VERSION 5.8 ;
BUSBITCHARS "[]" ;
DIVIDERCHAR "/" ;
UNITS
    DATABASE MICRONS 1000 ;
END UNITS

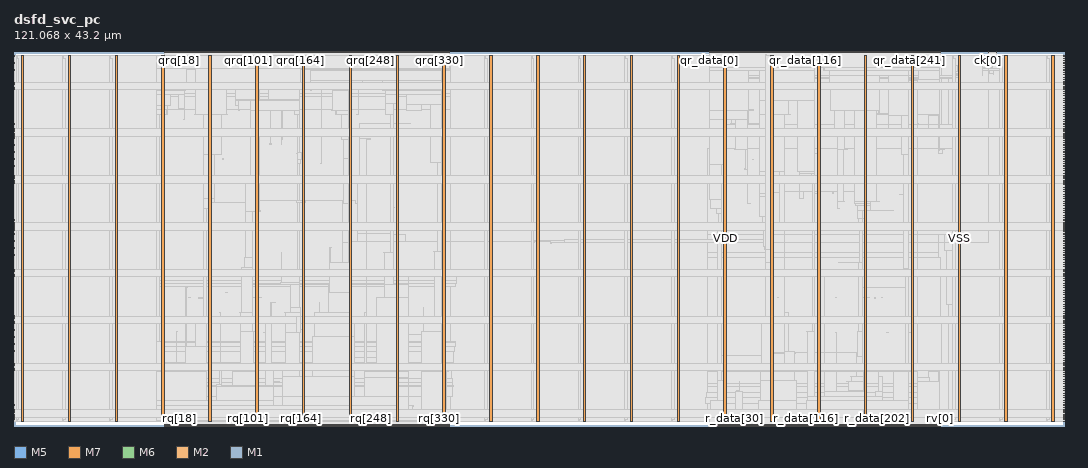
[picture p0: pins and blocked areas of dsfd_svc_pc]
MACRO dsfd_svc_pc
  FOREIGN dsfd_svc_pc 0 0 ;
  CLASS BLOCK ;
  SIZE 121.068 BY 43.2 ;
  PIN ck[0]
    DIRECTION INPUT ;
    USE SIGNAL ;
    PORT
      LAYER M5 ;
        RECT  112.32 43.008 112.344 43.2 ;
    END
  END ck[0]
  PIN qr_beat[0]
    DIRECTION OUTPUT ;
    USE SIGNAL ;
    PORT
      LAYER M5 ;
        RECT  106.368 43.008 106.392 43.2 ;
    END
  END qr_beat[0]
  PIN qr_beat[1]
    DIRECTION OUTPUT ;
    USE SIGNAL ;
    PORT
      LAYER M5 ;
        RECT  106.464 43.008 106.488 43.2 ;
    END
  END qr_beat[1]
  PIN qr_beat[2]
    DIRECTION OUTPUT ;
    USE SIGNAL ;
    PORT
      LAYER M5 ;
        RECT  106.56 43.008 106.584 43.2 ;
    END
  END qr_beat[2]
  PIN qr_beat[3]
    DIRECTION OUTPUT ;
    USE SIGNAL ;
    PORT
      LAYER M5 ;
        RECT  106.656 43.008 106.68 43.2 ;
    END
  END qr_beat[3]
  PIN qr_data[0]
    DIRECTION OUTPUT ;
    USE SIGNAL ;
    PORT
      LAYER M5 ;
        RECT  80.16 43.008 80.184 43.2 ;
    END
  END qr_data[0]
  PIN qr_data[100]
    DIRECTION OUTPUT ;
    USE SIGNAL ;
    PORT
      LAYER M5 ;
        RECT  89.76 43.008 89.784 43.2 ;
    END
  END qr_data[100]
  PIN qr_data[101]
    DIRECTION OUTPUT ;
    USE SIGNAL ;
    PORT
      LAYER M5 ;
        RECT  89.856 43.008 89.88 43.2 ;
    END
  END qr_data[101]
  PIN qr_data[102]
    DIRECTION OUTPUT ;
    USE SIGNAL ;
    PORT
      LAYER M5 ;
        RECT  89.952 43.008 89.976 43.2 ;
    END
  END qr_data[102]
  PIN qr_data[103]
    DIRECTION OUTPUT ;
    USE SIGNAL ;
    PORT
      LAYER M5 ;
        RECT  90.048 43.008 90.072 43.2 ;
    END
  END qr_data[103]
  PIN qr_data[104]
    DIRECTION OUTPUT ;
    USE SIGNAL ;
    PORT
      LAYER M5 ;
        RECT  90.144 43.008 90.168 43.2 ;
    END
  END qr_data[104]
  PIN qr_data[105]
    DIRECTION OUTPUT ;
    USE SIGNAL ;
    PORT
      LAYER M5 ;
        RECT  90.24 43.008 90.264 43.2 ;
    END
  END qr_data[105]
  PIN qr_data[106]
    DIRECTION OUTPUT ;
    USE SIGNAL ;
    PORT
      LAYER M5 ;
        RECT  90.336 43.008 90.36 43.2 ;
    END
  END qr_data[106]
  PIN qr_data[107]
    DIRECTION OUTPUT ;
    USE SIGNAL ;
    PORT
      LAYER M5 ;
        RECT  90.432 43.008 90.456 43.2 ;
    END
  END qr_data[107]
  PIN qr_data[108]
    DIRECTION OUTPUT ;
    USE SIGNAL ;
    PORT
      LAYER M5 ;
        RECT  90.528 43.008 90.552 43.2 ;
    END
  END qr_data[108]
  PIN qr_data[109]
    DIRECTION OUTPUT ;
    USE SIGNAL ;
    PORT
      LAYER M5 ;
        RECT  90.624 43.008 90.648 43.2 ;
    END
  END qr_data[109]
  PIN qr_data[10]
    DIRECTION OUTPUT ;
    USE SIGNAL ;
    PORT
      LAYER M5 ;
        RECT  81.12 43.008 81.144 43.2 ;
    END
  END qr_data[10]
  PIN qr_data[110]
    DIRECTION OUTPUT ;
    USE SIGNAL ;
    PORT
      LAYER M5 ;
        RECT  90.72 43.008 90.744 43.2 ;
    END
  END qr_data[110]
  PIN qr_data[111]
    DIRECTION OUTPUT ;
    USE SIGNAL ;
    PORT
      LAYER M5 ;
        RECT  90.816 43.008 90.84 43.2 ;
    END
  END qr_data[111]
  PIN qr_data[112]
    DIRECTION OUTPUT ;
    USE SIGNAL ;
    PORT
      LAYER M5 ;
        RECT  90.912 43.008 90.936 43.2 ;
    END
  END qr_data[112]
  PIN qr_data[113]
    DIRECTION OUTPUT ;
    USE SIGNAL ;
    PORT
      LAYER M5 ;
        RECT  91.008 43.008 91.032 43.2 ;
    END
  END qr_data[113]
  PIN qr_data[114]
    DIRECTION OUTPUT ;
    USE SIGNAL ;
    PORT
      LAYER M5 ;
        RECT  91.104 43.008 91.128 43.2 ;
    END
  END qr_data[114]
  PIN qr_data[115]
    DIRECTION OUTPUT ;
    USE SIGNAL ;
    PORT
      LAYER M5 ;
        RECT  91.2 43.008 91.224 43.2 ;
    END
  END qr_data[115]
  PIN qr_data[116]
    DIRECTION OUTPUT ;
    USE SIGNAL ;
    PORT
      LAYER M5 ;
        RECT  91.296 43.008 91.32 43.2 ;
    END
  END qr_data[116]
  PIN qr_data[117]
    DIRECTION OUTPUT ;
    USE SIGNAL ;
    PORT
      LAYER M5 ;
        RECT  91.392 43.008 91.416 43.2 ;
    END
  END qr_data[117]
  PIN qr_data[118]
    DIRECTION OUTPUT ;
    USE SIGNAL ;
    PORT
      LAYER M5 ;
        RECT  91.488 43.008 91.512 43.2 ;
    END
  END qr_data[118]
  PIN qr_data[119]
    DIRECTION OUTPUT ;
    USE SIGNAL ;
    PORT
      LAYER M5 ;
        RECT  91.584 43.008 91.608 43.2 ;
    END
  END qr_data[119]
  PIN qr_data[11]
    DIRECTION OUTPUT ;
    USE SIGNAL ;
    PORT
      LAYER M5 ;
        RECT  81.216 43.008 81.24 43.2 ;
    END
  END qr_data[11]
  PIN qr_data[120]
    DIRECTION OUTPUT ;
    USE SIGNAL ;
    PORT
      LAYER M5 ;
        RECT  91.68 43.008 91.704 43.2 ;
    END
  END qr_data[120]
  PIN qr_data[121]
    DIRECTION OUTPUT ;
    USE SIGNAL ;
    PORT
      LAYER M5 ;
        RECT  91.776 43.008 91.8 43.2 ;
    END
  END qr_data[121]
  PIN qr_data[122]
    DIRECTION OUTPUT ;
    USE SIGNAL ;
    PORT
      LAYER M5 ;
        RECT  91.872 43.008 91.896 43.2 ;
    END
  END qr_data[122]
  PIN qr_data[123]
    DIRECTION OUTPUT ;
    USE SIGNAL ;
    PORT
      LAYER M5 ;
        RECT  91.968 43.008 91.992 43.2 ;
    END
  END qr_data[123]
  PIN qr_data[124]
    DIRECTION OUTPUT ;
    USE SIGNAL ;
    PORT
      LAYER M5 ;
        RECT  92.064 43.008 92.088 43.2 ;
    END
  END qr_data[124]
  PIN qr_data[125]
    DIRECTION OUTPUT ;
    USE SIGNAL ;
    PORT
      LAYER M5 ;
        RECT  92.16 43.008 92.184 43.2 ;
    END
  END qr_data[125]
  PIN qr_data[126]
    DIRECTION OUTPUT ;
    USE SIGNAL ;
    PORT
      LAYER M5 ;
        RECT  92.256 43.008 92.28 43.2 ;
    END
  END qr_data[126]
  PIN qr_data[127]
    DIRECTION OUTPUT ;
    USE SIGNAL ;
    PORT
      LAYER M5 ;
        RECT  92.352 43.008 92.376 43.2 ;
    END
  END qr_data[127]
  PIN qr_data[128]
    DIRECTION OUTPUT ;
    USE SIGNAL ;
    PORT
      LAYER M5 ;
        RECT  92.448 43.008 92.472 43.2 ;
    END
  END qr_data[128]
  PIN qr_data[129]
    DIRECTION OUTPUT ;
    USE SIGNAL ;
    PORT
      LAYER M5 ;
        RECT  92.544 43.008 92.568 43.2 ;
    END
  END qr_data[129]
  PIN qr_data[12]
    DIRECTION OUTPUT ;
    USE SIGNAL ;
    PORT
      LAYER M5 ;
        RECT  81.312 43.008 81.336 43.2 ;
    END
  END qr_data[12]
  PIN qr_data[130]
    DIRECTION OUTPUT ;
    USE SIGNAL ;
    PORT
      LAYER M5 ;
        RECT  92.64 43.008 92.664 43.2 ;
    END
  END qr_data[130]
  PIN qr_data[131]
    DIRECTION OUTPUT ;
    USE SIGNAL ;
    PORT
      LAYER M5 ;
        RECT  92.736 43.008 92.76 43.2 ;
    END
  END qr_data[131]
  PIN qr_data[132]
    DIRECTION OUTPUT ;
    USE SIGNAL ;
    PORT
      LAYER M5 ;
        RECT  92.832 43.008 92.856 43.2 ;
    END
  END qr_data[132]
  PIN qr_data[133]
    DIRECTION OUTPUT ;
    USE SIGNAL ;
    PORT
      LAYER M5 ;
        RECT  92.928 43.008 92.952 43.2 ;
    END
  END qr_data[133]
  PIN qr_data[134]
    DIRECTION OUTPUT ;
    USE SIGNAL ;
    PORT
      LAYER M5 ;
        RECT  93.024 43.008 93.048 43.2 ;
    END
  END qr_data[134]
  PIN qr_data[135]
    DIRECTION OUTPUT ;
    USE SIGNAL ;
    PORT
      LAYER M5 ;
        RECT  93.12 43.008 93.144 43.2 ;
    END
  END qr_data[135]
  PIN qr_data[136]
    DIRECTION OUTPUT ;
    USE SIGNAL ;
    PORT
      LAYER M5 ;
        RECT  93.216 43.008 93.24 43.2 ;
    END
  END qr_data[136]
  PIN qr_data[137]
    DIRECTION OUTPUT ;
    USE SIGNAL ;
    PORT
      LAYER M5 ;
        RECT  93.312 43.008 93.336 43.2 ;
    END
  END qr_data[137]
  PIN qr_data[138]
    DIRECTION OUTPUT ;
    USE SIGNAL ;
    PORT
      LAYER M5 ;
        RECT  93.408 43.008 93.432 43.2 ;
    END
  END qr_data[138]
  PIN qr_data[139]
    DIRECTION OUTPUT ;
    USE SIGNAL ;
    PORT
      LAYER M5 ;
        RECT  93.504 43.008 93.528 43.2 ;
    END
  END qr_data[139]
  PIN qr_data[13]
    DIRECTION OUTPUT ;
    USE SIGNAL ;
    PORT
      LAYER M5 ;
        RECT  81.408 43.008 81.432 43.2 ;
    END
  END qr_data[13]
  PIN qr_data[140]
    DIRECTION OUTPUT ;
    USE SIGNAL ;
    PORT
      LAYER M5 ;
        RECT  93.6 43.008 93.624 43.2 ;
    END
  END qr_data[140]
  PIN qr_data[141]
    DIRECTION OUTPUT ;
    USE SIGNAL ;
    PORT
      LAYER M5 ;
        RECT  93.696 43.008 93.72 43.2 ;
    END
  END qr_data[141]
  PIN qr_data[142]
    DIRECTION OUTPUT ;
    USE SIGNAL ;
    PORT
      LAYER M5 ;
        RECT  93.792 43.008 93.816 43.2 ;
    END
  END qr_data[142]
  PIN qr_data[143]
    DIRECTION OUTPUT ;
    USE SIGNAL ;
    PORT
      LAYER M5 ;
        RECT  93.888 43.008 93.912 43.2 ;
    END
  END qr_data[143]
  PIN qr_data[144]
    DIRECTION OUTPUT ;
    USE SIGNAL ;
    PORT
      LAYER M5 ;
        RECT  93.984 43.008 94.008 43.2 ;
    END
  END qr_data[144]
  PIN qr_data[145]
    DIRECTION OUTPUT ;
    USE SIGNAL ;
    PORT
      LAYER M5 ;
        RECT  94.08 43.008 94.104 43.2 ;
    END
  END qr_data[145]
  PIN qr_data[146]
    DIRECTION OUTPUT ;
    USE SIGNAL ;
    PORT
      LAYER M5 ;
        RECT  94.176 43.008 94.2 43.2 ;
    END
  END qr_data[146]
  PIN qr_data[147]
    DIRECTION OUTPUT ;
    USE SIGNAL ;
    PORT
      LAYER M5 ;
        RECT  94.272 43.008 94.296 43.2 ;
    END
  END qr_data[147]
  PIN qr_data[148]
    DIRECTION OUTPUT ;
    USE SIGNAL ;
    PORT
      LAYER M5 ;
        RECT  94.368 43.008 94.392 43.2 ;
    END
  END qr_data[148]
  PIN qr_data[149]
    DIRECTION OUTPUT ;
    USE SIGNAL ;
    PORT
      LAYER M5 ;
        RECT  94.464 43.008 94.488 43.2 ;
    END
  END qr_data[149]
  PIN qr_data[14]
    DIRECTION OUTPUT ;
    USE SIGNAL ;
    PORT
      LAYER M5 ;
        RECT  81.504 43.008 81.528 43.2 ;
    END
  END qr_data[14]
  PIN qr_data[150]
    DIRECTION OUTPUT ;
    USE SIGNAL ;
    PORT
      LAYER M5 ;
        RECT  94.56 43.008 94.584 43.2 ;
    END
  END qr_data[150]
  PIN qr_data[151]
    DIRECTION OUTPUT ;
    USE SIGNAL ;
    PORT
      LAYER M5 ;
        RECT  94.656 43.008 94.68 43.2 ;
    END
  END qr_data[151]
  PIN qr_data[152]
    DIRECTION OUTPUT ;
    USE SIGNAL ;
    PORT
      LAYER M5 ;
        RECT  94.752 43.008 94.776 43.2 ;
    END
  END qr_data[152]
  PIN qr_data[153]
    DIRECTION OUTPUT ;
    USE SIGNAL ;
    PORT
      LAYER M5 ;
        RECT  94.848 43.008 94.872 43.2 ;
    END
  END qr_data[153]
  PIN qr_data[154]
    DIRECTION OUTPUT ;
    USE SIGNAL ;
    PORT
      LAYER M5 ;
        RECT  94.944 43.008 94.968 43.2 ;
    END
  END qr_data[154]
  PIN qr_data[155]
    DIRECTION OUTPUT ;
    USE SIGNAL ;
    PORT
      LAYER M5 ;
        RECT  95.04 43.008 95.064 43.2 ;
    END
  END qr_data[155]
  PIN qr_data[156]
    DIRECTION OUTPUT ;
    USE SIGNAL ;
    PORT
      LAYER M5 ;
        RECT  95.136 43.008 95.16 43.2 ;
    END
  END qr_data[156]
  PIN qr_data[157]
    DIRECTION OUTPUT ;
    USE SIGNAL ;
    PORT
      LAYER M5 ;
        RECT  95.232 43.008 95.256 43.2 ;
    END
  END qr_data[157]
  PIN qr_data[158]
    DIRECTION OUTPUT ;
    USE SIGNAL ;
    PORT
      LAYER M5 ;
        RECT  95.328 43.008 95.352 43.2 ;
    END
  END qr_data[158]
  PIN qr_data[159]
    DIRECTION OUTPUT ;
    USE SIGNAL ;
    PORT
      LAYER M5 ;
        RECT  95.424 43.008 95.448 43.2 ;
    END
  END qr_data[159]
  PIN qr_data[15]
    DIRECTION OUTPUT ;
    USE SIGNAL ;
    PORT
      LAYER M5 ;
        RECT  81.6 43.008 81.624 43.2 ;
    END
  END qr_data[15]
  PIN qr_data[160]
    DIRECTION OUTPUT ;
    USE SIGNAL ;
    PORT
      LAYER M5 ;
        RECT  95.52 43.008 95.544 43.2 ;
    END
  END qr_data[160]
  PIN qr_data[161]
    DIRECTION OUTPUT ;
    USE SIGNAL ;
    PORT
      LAYER M5 ;
        RECT  95.616 43.008 95.64 43.2 ;
    END
  END qr_data[161]
  PIN qr_data[162]
    DIRECTION OUTPUT ;
    USE SIGNAL ;
    PORT
      LAYER M5 ;
        RECT  95.712 43.008 95.736 43.2 ;
    END
  END qr_data[162]
  PIN qr_data[163]
    DIRECTION OUTPUT ;
    USE SIGNAL ;
    PORT
      LAYER M5 ;
        RECT  95.808 43.008 95.832 43.2 ;
    END
  END qr_data[163]
  PIN qr_data[164]
    DIRECTION OUTPUT ;
    USE SIGNAL ;
    PORT
      LAYER M5 ;
        RECT  95.904 43.008 95.928 43.2 ;
    END
  END qr_data[164]
  PIN qr_data[165]
    DIRECTION OUTPUT ;
    USE SIGNAL ;
    PORT
      LAYER M5 ;
        RECT  96 43.008 96.024 43.2 ;
    END
  END qr_data[165]
  PIN qr_data[166]
    DIRECTION OUTPUT ;
    USE SIGNAL ;
    PORT
      LAYER M5 ;
        RECT  96.096 43.008 96.12 43.2 ;
    END
  END qr_data[166]
  PIN qr_data[167]
    DIRECTION OUTPUT ;
    USE SIGNAL ;
    PORT
      LAYER M5 ;
        RECT  96.192 43.008 96.216 43.2 ;
    END
  END qr_data[167]
  PIN qr_data[168]
    DIRECTION OUTPUT ;
    USE SIGNAL ;
    PORT
      LAYER M5 ;
        RECT  96.288 43.008 96.312 43.2 ;
    END
  END qr_data[168]
  PIN qr_data[169]
    DIRECTION OUTPUT ;
    USE SIGNAL ;
    PORT
      LAYER M5 ;
        RECT  96.384 43.008 96.408 43.2 ;
    END
  END qr_data[169]
  PIN qr_data[16]
    DIRECTION OUTPUT ;
    USE SIGNAL ;
    PORT
      LAYER M5 ;
        RECT  81.696 43.008 81.72 43.2 ;
    END
  END qr_data[16]
  PIN qr_data[170]
    DIRECTION OUTPUT ;
    USE SIGNAL ;
    PORT
      LAYER M5 ;
        RECT  96.48 43.008 96.504 43.2 ;
    END
  END qr_data[170]
  PIN qr_data[171]
    DIRECTION OUTPUT ;
    USE SIGNAL ;
    PORT
      LAYER M5 ;
        RECT  96.576 43.008 96.6 43.2 ;
    END
  END qr_data[171]
  PIN qr_data[172]
    DIRECTION OUTPUT ;
    USE SIGNAL ;
    PORT
      LAYER M5 ;
        RECT  96.672 43.008 96.696 43.2 ;
    END
  END qr_data[172]
  PIN qr_data[173]
    DIRECTION OUTPUT ;
    USE SIGNAL ;
    PORT
      LAYER M5 ;
        RECT  96.768 43.008 96.792 43.2 ;
    END
  END qr_data[173]
  PIN qr_data[174]
    DIRECTION OUTPUT ;
    USE SIGNAL ;
    PORT
      LAYER M5 ;
        RECT  96.864 43.008 96.888 43.2 ;
    END
  END qr_data[174]
  PIN qr_data[175]
    DIRECTION OUTPUT ;
    USE SIGNAL ;
    PORT
      LAYER M5 ;
        RECT  96.96 43.008 96.984 43.2 ;
    END
  END qr_data[175]
  PIN qr_data[176]
    DIRECTION OUTPUT ;
    USE SIGNAL ;
    PORT
      LAYER M5 ;
        RECT  97.056 43.008 97.08 43.2 ;
    END
  END qr_data[176]
  PIN qr_data[177]
    DIRECTION OUTPUT ;
    USE SIGNAL ;
    PORT
      LAYER M5 ;
        RECT  97.152 43.008 97.176 43.2 ;
    END
  END qr_data[177]
  PIN qr_data[178]
    DIRECTION OUTPUT ;
    USE SIGNAL ;
    PORT
      LAYER M5 ;
        RECT  97.248 43.008 97.272 43.2 ;
    END
  END qr_data[178]
  PIN qr_data[179]
    DIRECTION OUTPUT ;
    USE SIGNAL ;
    PORT
      LAYER M5 ;
        RECT  97.344 43.008 97.368 43.2 ;
    END
  END qr_data[179]
  PIN qr_data[17]
    DIRECTION OUTPUT ;
    USE SIGNAL ;
    PORT
      LAYER M5 ;
        RECT  81.792 43.008 81.816 43.2 ;
    END
  END qr_data[17]
  PIN qr_data[180]
    DIRECTION OUTPUT ;
    USE SIGNAL ;
    PORT
      LAYER M5 ;
        RECT  97.44 43.008 97.464 43.2 ;
    END
  END qr_data[180]
  PIN qr_data[181]
    DIRECTION OUTPUT ;
    USE SIGNAL ;
    PORT
      LAYER M5 ;
        RECT  97.536 43.008 97.56 43.2 ;
    END
  END qr_data[181]
  PIN qr_data[182]
    DIRECTION OUTPUT ;
    USE SIGNAL ;
    PORT
      LAYER M5 ;
        RECT  97.632 43.008 97.656 43.2 ;
    END
  END qr_data[182]
  PIN qr_data[183]
    DIRECTION OUTPUT ;
    USE SIGNAL ;
    PORT
      LAYER M5 ;
        RECT  97.728 43.008 97.752 43.2 ;
    END
  END qr_data[183]
  PIN qr_data[184]
    DIRECTION OUTPUT ;
    USE SIGNAL ;
    PORT
      LAYER M5 ;
        RECT  97.824 43.008 97.848 43.2 ;
    END
  END qr_data[184]
  PIN qr_data[185]
    DIRECTION OUTPUT ;
    USE SIGNAL ;
    PORT
      LAYER M5 ;
        RECT  97.92 43.008 97.944 43.2 ;
    END
  END qr_data[185]
  PIN qr_data[186]
    DIRECTION OUTPUT ;
    USE SIGNAL ;
    PORT
      LAYER M5 ;
        RECT  98.016 43.008 98.04 43.2 ;
    END
  END qr_data[186]
  PIN qr_data[187]
    DIRECTION OUTPUT ;
    USE SIGNAL ;
    PORT
      LAYER M5 ;
        RECT  98.112 43.008 98.136 43.2 ;
    END
  END qr_data[187]
  PIN qr_data[188]
    DIRECTION OUTPUT ;
    USE SIGNAL ;
    PORT
      LAYER M5 ;
        RECT  98.208 43.008 98.232 43.2 ;
    END
  END qr_data[188]
  PIN qr_data[189]
    DIRECTION OUTPUT ;
    USE SIGNAL ;
    PORT
      LAYER M5 ;
        RECT  98.304 43.008 98.328 43.2 ;
    END
  END qr_data[189]
  PIN qr_data[18]
    DIRECTION OUTPUT ;
    USE SIGNAL ;
    PORT
      LAYER M5 ;
        RECT  81.888 43.008 81.912 43.2 ;
    END
  END qr_data[18]
  PIN qr_data[190]
    DIRECTION OUTPUT ;
    USE SIGNAL ;
    PORT
      LAYER M5 ;
        RECT  98.4 43.008 98.424 43.2 ;
    END
  END qr_data[190]
  PIN qr_data[191]
    DIRECTION OUTPUT ;
    USE SIGNAL ;
    PORT
      LAYER M5 ;
        RECT  98.496 43.008 98.52 43.2 ;
    END
  END qr_data[191]
  PIN qr_data[192]
    DIRECTION OUTPUT ;
    USE SIGNAL ;
    PORT
      LAYER M5 ;
        RECT  98.592 43.008 98.616 43.2 ;
    END
  END qr_data[192]
  PIN qr_data[193]
    DIRECTION OUTPUT ;
    USE SIGNAL ;
    PORT
      LAYER M5 ;
        RECT  98.688 43.008 98.712 43.2 ;
    END
  END qr_data[193]
  PIN qr_data[194]
    DIRECTION OUTPUT ;
    USE SIGNAL ;
    PORT
      LAYER M5 ;
        RECT  98.784 43.008 98.808 43.2 ;
    END
  END qr_data[194]
  PIN qr_data[195]
    DIRECTION OUTPUT ;
    USE SIGNAL ;
    PORT
      LAYER M5 ;
        RECT  98.88 43.008 98.904 43.2 ;
    END
  END qr_data[195]
  PIN qr_data[196]
    DIRECTION OUTPUT ;
    USE SIGNAL ;
    PORT
      LAYER M5 ;
        RECT  98.976 43.008 99 43.2 ;
    END
  END qr_data[196]
  PIN qr_data[197]
    DIRECTION OUTPUT ;
    USE SIGNAL ;
    PORT
      LAYER M5 ;
        RECT  99.072 43.008 99.096 43.2 ;
    END
  END qr_data[197]
  PIN qr_data[198]
    DIRECTION OUTPUT ;
    USE SIGNAL ;
    PORT
      LAYER M5 ;
        RECT  99.168 43.008 99.192 43.2 ;
    END
  END qr_data[198]
  PIN qr_data[199]
    DIRECTION OUTPUT ;
    USE SIGNAL ;
    PORT
      LAYER M5 ;
        RECT  99.264 43.008 99.288 43.2 ;
    END
  END qr_data[199]
  PIN qr_data[19]
    DIRECTION OUTPUT ;
    USE SIGNAL ;
    PORT
      LAYER M5 ;
        RECT  81.984 43.008 82.008 43.2 ;
    END
  END qr_data[19]
  PIN qr_data[1]
    DIRECTION OUTPUT ;
    USE SIGNAL ;
    PORT
      LAYER M5 ;
        RECT  80.256 43.008 80.28 43.2 ;
    END
  END qr_data[1]
  PIN qr_data[200]
    DIRECTION OUTPUT ;
    USE SIGNAL ;
    PORT
      LAYER M5 ;
        RECT  99.36 43.008 99.384 43.2 ;
    END
  END qr_data[200]
  PIN qr_data[201]
    DIRECTION OUTPUT ;
    USE SIGNAL ;
    PORT
      LAYER M5 ;
        RECT  99.456 43.008 99.48 43.2 ;
    END
  END qr_data[201]
  PIN qr_data[202]
    DIRECTION OUTPUT ;
    USE SIGNAL ;
    PORT
      LAYER M5 ;
        RECT  99.552 43.008 99.576 43.2 ;
    END
  END qr_data[202]
  PIN qr_data[203]
    DIRECTION OUTPUT ;
    USE SIGNAL ;
    PORT
      LAYER M5 ;
        RECT  99.648 43.008 99.672 43.2 ;
    END
  END qr_data[203]
  PIN qr_data[204]
    DIRECTION OUTPUT ;
    USE SIGNAL ;
    PORT
      LAYER M5 ;
        RECT  99.744 43.008 99.768 43.2 ;
    END
  END qr_data[204]
  PIN qr_data[205]
    DIRECTION OUTPUT ;
    USE SIGNAL ;
    PORT
      LAYER M5 ;
        RECT  99.84 43.008 99.864 43.2 ;
    END
  END qr_data[205]
  PIN qr_data[206]
    DIRECTION OUTPUT ;
    USE SIGNAL ;
    PORT
      LAYER M5 ;
        RECT  99.936 43.008 99.96 43.2 ;
    END
  END qr_data[206]
  PIN qr_data[207]
    DIRECTION OUTPUT ;
    USE SIGNAL ;
    PORT
      LAYER M5 ;
        RECT  100.032 43.008 100.056 43.2 ;
    END
  END qr_data[207]
  PIN qr_data[208]
    DIRECTION OUTPUT ;
    USE SIGNAL ;
    PORT
      LAYER M5 ;
        RECT  100.128 43.008 100.152 43.2 ;
    END
  END qr_data[208]
  PIN qr_data[209]
    DIRECTION OUTPUT ;
    USE SIGNAL ;
    PORT
      LAYER M5 ;
        RECT  100.224 43.008 100.248 43.2 ;
    END
  END qr_data[209]
  PIN qr_data[20]
    DIRECTION OUTPUT ;
    USE SIGNAL ;
    PORT
      LAYER M5 ;
        RECT  82.08 43.008 82.104 43.2 ;
    END
  END qr_data[20]
  PIN qr_data[210]
    DIRECTION OUTPUT ;
    USE SIGNAL ;
    PORT
      LAYER M5 ;
        RECT  100.32 43.008 100.344 43.2 ;
    END
  END qr_data[210]
  PIN qr_data[211]
    DIRECTION OUTPUT ;
    USE SIGNAL ;
    PORT
      LAYER M5 ;
        RECT  100.416 43.008 100.44 43.2 ;
    END
  END qr_data[211]
  PIN qr_data[212]
    DIRECTION OUTPUT ;
    USE SIGNAL ;
    PORT
      LAYER M5 ;
        RECT  100.512 43.008 100.536 43.2 ;
    END
  END qr_data[212]
  PIN qr_data[213]
    DIRECTION OUTPUT ;
    USE SIGNAL ;
    PORT
      LAYER M5 ;
        RECT  100.608 43.008 100.632 43.2 ;
    END
  END qr_data[213]
  PIN qr_data[214]
    DIRECTION OUTPUT ;
    USE SIGNAL ;
    PORT
      LAYER M5 ;
        RECT  100.704 43.008 100.728 43.2 ;
    END
  END qr_data[214]
  PIN qr_data[215]
    DIRECTION OUTPUT ;
    USE SIGNAL ;
    PORT
      LAYER M5 ;
        RECT  100.8 43.008 100.824 43.2 ;
    END
  END qr_data[215]
  PIN qr_data[216]
    DIRECTION OUTPUT ;
    USE SIGNAL ;
    PORT
      LAYER M5 ;
        RECT  100.896 43.008 100.92 43.2 ;
    END
  END qr_data[216]
  PIN qr_data[217]
    DIRECTION OUTPUT ;
    USE SIGNAL ;
    PORT
      LAYER M5 ;
        RECT  100.992 43.008 101.016 43.2 ;
    END
  END qr_data[217]
  PIN qr_data[218]
    DIRECTION OUTPUT ;
    USE SIGNAL ;
    PORT
      LAYER M5 ;
        RECT  101.088 43.008 101.112 43.2 ;
    END
  END qr_data[218]
  PIN qr_data[219]
    DIRECTION OUTPUT ;
    USE SIGNAL ;
    PORT
      LAYER M5 ;
        RECT  101.184 43.008 101.208 43.2 ;
    END
  END qr_data[219]
  PIN qr_data[21]
    DIRECTION OUTPUT ;
    USE SIGNAL ;
    PORT
      LAYER M5 ;
        RECT  82.176 43.008 82.2 43.2 ;
    END
  END qr_data[21]
  PIN qr_data[220]
    DIRECTION OUTPUT ;
    USE SIGNAL ;
    PORT
      LAYER M5 ;
        RECT  101.28 43.008 101.304 43.2 ;
    END
  END qr_data[220]
  PIN qr_data[221]
    DIRECTION OUTPUT ;
    USE SIGNAL ;
    PORT
      LAYER M5 ;
        RECT  101.376 43.008 101.4 43.2 ;
    END
  END qr_data[221]
  PIN qr_data[222]
    DIRECTION OUTPUT ;
    USE SIGNAL ;
    PORT
      LAYER M5 ;
        RECT  101.472 43.008 101.496 43.2 ;
    END
  END qr_data[222]
  PIN qr_data[223]
    DIRECTION OUTPUT ;
    USE SIGNAL ;
    PORT
      LAYER M5 ;
        RECT  101.568 43.008 101.592 43.2 ;
    END
  END qr_data[223]
  PIN qr_data[224]
    DIRECTION OUTPUT ;
    USE SIGNAL ;
    PORT
      LAYER M5 ;
        RECT  101.664 43.008 101.688 43.2 ;
    END
  END qr_data[224]
  PIN qr_data[225]
    DIRECTION OUTPUT ;
    USE SIGNAL ;
    PORT
      LAYER M5 ;
        RECT  101.76 43.008 101.784 43.2 ;
    END
  END qr_data[225]
  PIN qr_data[226]
    DIRECTION OUTPUT ;
    USE SIGNAL ;
    PORT
      LAYER M5 ;
        RECT  101.856 43.008 101.88 43.2 ;
    END
  END qr_data[226]
  PIN qr_data[227]
    DIRECTION OUTPUT ;
    USE SIGNAL ;
    PORT
      LAYER M5 ;
        RECT  101.952 43.008 101.976 43.2 ;
    END
  END qr_data[227]
  PIN qr_data[228]
    DIRECTION OUTPUT ;
    USE SIGNAL ;
    PORT
      LAYER M5 ;
        RECT  102.048 43.008 102.072 43.2 ;
    END
  END qr_data[228]
  PIN qr_data[229]
    DIRECTION OUTPUT ;
    USE SIGNAL ;
    PORT
      LAYER M5 ;
        RECT  102.144 43.008 102.168 43.2 ;
    END
  END qr_data[229]
  PIN qr_data[22]
    DIRECTION OUTPUT ;
    USE SIGNAL ;
    PORT
      LAYER M5 ;
        RECT  82.272 43.008 82.296 43.2 ;
    END
  END qr_data[22]
  PIN qr_data[230]
    DIRECTION OUTPUT ;
    USE SIGNAL ;
    PORT
      LAYER M5 ;
        RECT  102.24 43.008 102.264 43.2 ;
    END
  END qr_data[230]
  PIN qr_data[231]
    DIRECTION OUTPUT ;
    USE SIGNAL ;
    PORT
      LAYER M5 ;
        RECT  102.336 43.008 102.36 43.2 ;
    END
  END qr_data[231]
  PIN qr_data[232]
    DIRECTION OUTPUT ;
    USE SIGNAL ;
    PORT
      LAYER M5 ;
        RECT  102.432 43.008 102.456 43.2 ;
    END
  END qr_data[232]
  PIN qr_data[233]
    DIRECTION OUTPUT ;
    USE SIGNAL ;
    PORT
      LAYER M5 ;
        RECT  102.528 43.008 102.552 43.2 ;
    END
  END qr_data[233]
  PIN qr_data[234]
    DIRECTION OUTPUT ;
    USE SIGNAL ;
    PORT
      LAYER M5 ;
        RECT  102.624 43.008 102.648 43.2 ;
    END
  END qr_data[234]
  PIN qr_data[235]
    DIRECTION OUTPUT ;
    USE SIGNAL ;
    PORT
      LAYER M5 ;
        RECT  102.72 43.008 102.744 43.2 ;
    END
  END qr_data[235]
  PIN qr_data[236]
    DIRECTION OUTPUT ;
    USE SIGNAL ;
    PORT
      LAYER M5 ;
        RECT  102.816 43.008 102.84 43.2 ;
    END
  END qr_data[236]
  PIN qr_data[237]
    DIRECTION OUTPUT ;
    USE SIGNAL ;
    PORT
      LAYER M5 ;
        RECT  102.912 43.008 102.936 43.2 ;
    END
  END qr_data[237]
  PIN qr_data[238]
    DIRECTION OUTPUT ;
    USE SIGNAL ;
    PORT
      LAYER M5 ;
        RECT  103.008 43.008 103.032 43.2 ;
    END
  END qr_data[238]
  PIN qr_data[239]
    DIRECTION OUTPUT ;
    USE SIGNAL ;
    PORT
      LAYER M5 ;
        RECT  103.104 43.008 103.128 43.2 ;
    END
  END qr_data[239]
  PIN qr_data[23]
    DIRECTION OUTPUT ;
    USE SIGNAL ;
    PORT
      LAYER M5 ;
        RECT  82.368 43.008 82.392 43.2 ;
    END
  END qr_data[23]
  PIN qr_data[240]
    DIRECTION OUTPUT ;
    USE SIGNAL ;
    PORT
      LAYER M5 ;
        RECT  103.2 43.008 103.224 43.2 ;
    END
  END qr_data[240]
  PIN qr_data[241]
    DIRECTION OUTPUT ;
    USE SIGNAL ;
    PORT
      LAYER M5 ;
        RECT  103.296 43.008 103.32 43.2 ;
    END
  END qr_data[241]
  PIN qr_data[242]
    DIRECTION OUTPUT ;
    USE SIGNAL ;
    PORT
      LAYER M5 ;
        RECT  103.392 43.008 103.416 43.2 ;
    END
  END qr_data[242]
  PIN qr_data[243]
    DIRECTION OUTPUT ;
    USE SIGNAL ;
    PORT
      LAYER M5 ;
        RECT  103.488 43.008 103.512 43.2 ;
    END
  END qr_data[243]
  PIN qr_data[244]
    DIRECTION OUTPUT ;
    USE SIGNAL ;
    PORT
      LAYER M5 ;
        RECT  103.584 43.008 103.608 43.2 ;
    END
  END qr_data[244]
  PIN qr_data[245]
    DIRECTION OUTPUT ;
    USE SIGNAL ;
    PORT
      LAYER M5 ;
        RECT  103.68 43.008 103.704 43.2 ;
    END
  END qr_data[245]
  PIN qr_data[246]
    DIRECTION OUTPUT ;
    USE SIGNAL ;
    PORT
      LAYER M5 ;
        RECT  103.776 43.008 103.8 43.2 ;
    END
  END qr_data[246]
  PIN qr_data[247]
    DIRECTION OUTPUT ;
    USE SIGNAL ;
    PORT
      LAYER M5 ;
        RECT  103.872 43.008 103.896 43.2 ;
    END
  END qr_data[247]
  PIN qr_data[248]
    DIRECTION OUTPUT ;
    USE SIGNAL ;
    PORT
      LAYER M5 ;
        RECT  103.968 43.008 103.992 43.2 ;
    END
  END qr_data[248]
  PIN qr_data[249]
    DIRECTION OUTPUT ;
    USE SIGNAL ;
    PORT
      LAYER M5 ;
        RECT  104.064 43.008 104.088 43.2 ;
    END
  END qr_data[249]
  PIN qr_data[24]
    DIRECTION OUTPUT ;
    USE SIGNAL ;
    PORT
      LAYER M5 ;
        RECT  82.464 43.008 82.488 43.2 ;
    END
  END qr_data[24]
  PIN qr_data[250]
    DIRECTION OUTPUT ;
    USE SIGNAL ;
    PORT
      LAYER M5 ;
        RECT  104.16 43.008 104.184 43.2 ;
    END
  END qr_data[250]
  PIN qr_data[251]
    DIRECTION OUTPUT ;
    USE SIGNAL ;
    PORT
      LAYER M5 ;
        RECT  104.256 43.008 104.28 43.2 ;
    END
  END qr_data[251]
  PIN qr_data[252]
    DIRECTION OUTPUT ;
    USE SIGNAL ;
    PORT
      LAYER M5 ;
        RECT  104.352 43.008 104.376 43.2 ;
    END
  END qr_data[252]
  PIN qr_data[253]
    DIRECTION OUTPUT ;
    USE SIGNAL ;
    PORT
      LAYER M5 ;
        RECT  104.448 43.008 104.472 43.2 ;
    END
  END qr_data[253]
  PIN qr_data[254]
    DIRECTION OUTPUT ;
    USE SIGNAL ;
    PORT
      LAYER M5 ;
        RECT  104.544 43.008 104.568 43.2 ;
    END
  END qr_data[254]
  PIN qr_data[255]
    DIRECTION OUTPUT ;
    USE SIGNAL ;
    PORT
      LAYER M5 ;
        RECT  104.64 43.008 104.664 43.2 ;
    END
  END qr_data[255]
  PIN qr_data[25]
    DIRECTION OUTPUT ;
    USE SIGNAL ;
    PORT
      LAYER M5 ;
        RECT  82.56 43.008 82.584 43.2 ;
    END
  END qr_data[25]
  PIN qr_data[26]
    DIRECTION OUTPUT ;
    USE SIGNAL ;
    PORT
      LAYER M5 ;
        RECT  82.656 43.008 82.68 43.2 ;
    END
  END qr_data[26]
  PIN qr_data[27]
    DIRECTION OUTPUT ;
    USE SIGNAL ;
    PORT
      LAYER M5 ;
        RECT  82.752 43.008 82.776 43.2 ;
    END
  END qr_data[27]
  PIN qr_data[28]
    DIRECTION OUTPUT ;
    USE SIGNAL ;
    PORT
      LAYER M5 ;
        RECT  82.848 43.008 82.872 43.2 ;
    END
  END qr_data[28]
  PIN qr_data[29]
    DIRECTION OUTPUT ;
    USE SIGNAL ;
    PORT
      LAYER M5 ;
        RECT  82.944 43.008 82.968 43.2 ;
    END
  END qr_data[29]
  PIN qr_data[2]
    DIRECTION OUTPUT ;
    USE SIGNAL ;
    PORT
      LAYER M5 ;
        RECT  80.352 43.008 80.376 43.2 ;
    END
  END qr_data[2]
  PIN qr_data[30]
    DIRECTION OUTPUT ;
    USE SIGNAL ;
    PORT
      LAYER M5 ;
        RECT  83.04 43.008 83.064 43.2 ;
    END
  END qr_data[30]
  PIN qr_data[31]
    DIRECTION OUTPUT ;
    USE SIGNAL ;
    PORT
      LAYER M5 ;
        RECT  83.136 43.008 83.16 43.2 ;
    END
  END qr_data[31]
  PIN qr_data[32]
    DIRECTION OUTPUT ;
    USE SIGNAL ;
    PORT
      LAYER M5 ;
        RECT  83.232 43.008 83.256 43.2 ;
    END
  END qr_data[32]
  PIN qr_data[33]
    DIRECTION OUTPUT ;
    USE SIGNAL ;
    PORT
      LAYER M5 ;
        RECT  83.328 43.008 83.352 43.2 ;
    END
  END qr_data[33]
  PIN qr_data[34]
    DIRECTION OUTPUT ;
    USE SIGNAL ;
    PORT
      LAYER M5 ;
        RECT  83.424 43.008 83.448 43.2 ;
    END
  END qr_data[34]
  PIN qr_data[35]
    DIRECTION OUTPUT ;
    USE SIGNAL ;
    PORT
      LAYER M5 ;
        RECT  83.52 43.008 83.544 43.2 ;
    END
  END qr_data[35]
  PIN qr_data[36]
    DIRECTION OUTPUT ;
    USE SIGNAL ;
    PORT
      LAYER M5 ;
        RECT  83.616 43.008 83.64 43.2 ;
    END
  END qr_data[36]
  PIN qr_data[37]
    DIRECTION OUTPUT ;
    USE SIGNAL ;
    PORT
      LAYER M5 ;
        RECT  83.712 43.008 83.736 43.2 ;
    END
  END qr_data[37]
  PIN qr_data[38]
    DIRECTION OUTPUT ;
    USE SIGNAL ;
    PORT
      LAYER M5 ;
        RECT  83.808 43.008 83.832 43.2 ;
    END
  END qr_data[38]
  PIN qr_data[39]
    DIRECTION OUTPUT ;
    USE SIGNAL ;
    PORT
      LAYER M5 ;
        RECT  83.904 43.008 83.928 43.2 ;
    END
  END qr_data[39]
  PIN qr_data[3]
    DIRECTION OUTPUT ;
    USE SIGNAL ;
    PORT
      LAYER M5 ;
        RECT  80.448 43.008 80.472 43.2 ;
    END
  END qr_data[3]
  PIN qr_data[40]
    DIRECTION OUTPUT ;
    USE SIGNAL ;
    PORT
      LAYER M5 ;
        RECT  84 43.008 84.024 43.2 ;
    END
  END qr_data[40]
  PIN qr_data[41]
    DIRECTION OUTPUT ;
    USE SIGNAL ;
    PORT
      LAYER M5 ;
        RECT  84.096 43.008 84.12 43.2 ;
    END
  END qr_data[41]
  PIN qr_data[42]
    DIRECTION OUTPUT ;
    USE SIGNAL ;
    PORT
      LAYER M5 ;
        RECT  84.192 43.008 84.216 43.2 ;
    END
  END qr_data[42]
  PIN qr_data[43]
    DIRECTION OUTPUT ;
    USE SIGNAL ;
    PORT
      LAYER M5 ;
        RECT  84.288 43.008 84.312 43.2 ;
    END
  END qr_data[43]
  PIN qr_data[44]
    DIRECTION OUTPUT ;
    USE SIGNAL ;
    PORT
      LAYER M5 ;
        RECT  84.384 43.008 84.408 43.2 ;
    END
  END qr_data[44]
  PIN qr_data[45]
    DIRECTION OUTPUT ;
    USE SIGNAL ;
    PORT
      LAYER M5 ;
        RECT  84.48 43.008 84.504 43.2 ;
    END
  END qr_data[45]
  PIN qr_data[46]
    DIRECTION OUTPUT ;
    USE SIGNAL ;
    PORT
      LAYER M5 ;
        RECT  84.576 43.008 84.6 43.2 ;
    END
  END qr_data[46]
  PIN qr_data[47]
    DIRECTION OUTPUT ;
    USE SIGNAL ;
    PORT
      LAYER M5 ;
        RECT  84.672 43.008 84.696 43.2 ;
    END
  END qr_data[47]
  PIN qr_data[48]
    DIRECTION OUTPUT ;
    USE SIGNAL ;
    PORT
      LAYER M5 ;
        RECT  84.768 43.008 84.792 43.2 ;
    END
  END qr_data[48]
  PIN qr_data[49]
    DIRECTION OUTPUT ;
    USE SIGNAL ;
    PORT
      LAYER M5 ;
        RECT  84.864 43.008 84.888 43.2 ;
    END
  END qr_data[49]
  PIN qr_data[4]
    DIRECTION OUTPUT ;
    USE SIGNAL ;
    PORT
      LAYER M5 ;
        RECT  80.544 43.008 80.568 43.2 ;
    END
  END qr_data[4]
  PIN qr_data[50]
    DIRECTION OUTPUT ;
    USE SIGNAL ;
    PORT
      LAYER M5 ;
        RECT  84.96 43.008 84.984 43.2 ;
    END
  END qr_data[50]
  PIN qr_data[51]
    DIRECTION OUTPUT ;
    USE SIGNAL ;
    PORT
      LAYER M5 ;
        RECT  85.056 43.008 85.08 43.2 ;
    END
  END qr_data[51]
  PIN qr_data[52]
    DIRECTION OUTPUT ;
    USE SIGNAL ;
    PORT
      LAYER M5 ;
        RECT  85.152 43.008 85.176 43.2 ;
    END
  END qr_data[52]
  PIN qr_data[53]
    DIRECTION OUTPUT ;
    USE SIGNAL ;
    PORT
      LAYER M5 ;
        RECT  85.248 43.008 85.272 43.2 ;
    END
  END qr_data[53]
  PIN qr_data[54]
    DIRECTION OUTPUT ;
    USE SIGNAL ;
    PORT
      LAYER M5 ;
        RECT  85.344 43.008 85.368 43.2 ;
    END
  END qr_data[54]
  PIN qr_data[55]
    DIRECTION OUTPUT ;
    USE SIGNAL ;
    PORT
      LAYER M5 ;
        RECT  85.44 43.008 85.464 43.2 ;
    END
  END qr_data[55]
  PIN qr_data[56]
    DIRECTION OUTPUT ;
    USE SIGNAL ;
    PORT
      LAYER M5 ;
        RECT  85.536 43.008 85.56 43.2 ;
    END
  END qr_data[56]
  PIN qr_data[57]
    DIRECTION OUTPUT ;
    USE SIGNAL ;
    PORT
      LAYER M5 ;
        RECT  85.632 43.008 85.656 43.2 ;
    END
  END qr_data[57]
  PIN qr_data[58]
    DIRECTION OUTPUT ;
    USE SIGNAL ;
    PORT
      LAYER M5 ;
        RECT  85.728 43.008 85.752 43.2 ;
    END
  END qr_data[58]
  PIN qr_data[59]
    DIRECTION OUTPUT ;
    USE SIGNAL ;
    PORT
      LAYER M5 ;
        RECT  85.824 43.008 85.848 43.2 ;
    END
  END qr_data[59]
  PIN qr_data[5]
    DIRECTION OUTPUT ;
    USE SIGNAL ;
    PORT
      LAYER M5 ;
        RECT  80.64 43.008 80.664 43.2 ;
    END
  END qr_data[5]
  PIN qr_data[60]
    DIRECTION OUTPUT ;
    USE SIGNAL ;
    PORT
      LAYER M5 ;
        RECT  85.92 43.008 85.944 43.2 ;
    END
  END qr_data[60]
  PIN qr_data[61]
    DIRECTION OUTPUT ;
    USE SIGNAL ;
    PORT
      LAYER M5 ;
        RECT  86.016 43.008 86.04 43.2 ;
    END
  END qr_data[61]
  PIN qr_data[62]
    DIRECTION OUTPUT ;
    USE SIGNAL ;
    PORT
      LAYER M5 ;
        RECT  86.112 43.008 86.136 43.2 ;
    END
  END qr_data[62]
  PIN qr_data[63]
    DIRECTION OUTPUT ;
    USE SIGNAL ;
    PORT
      LAYER M5 ;
        RECT  86.208 43.008 86.232 43.2 ;
    END
  END qr_data[63]
  PIN qr_data[64]
    DIRECTION OUTPUT ;
    USE SIGNAL ;
    PORT
      LAYER M5 ;
        RECT  86.304 43.008 86.328 43.2 ;
    END
  END qr_data[64]
  PIN qr_data[65]
    DIRECTION OUTPUT ;
    USE SIGNAL ;
    PORT
      LAYER M5 ;
        RECT  86.4 43.008 86.424 43.2 ;
    END
  END qr_data[65]
  PIN qr_data[66]
    DIRECTION OUTPUT ;
    USE SIGNAL ;
    PORT
      LAYER M5 ;
        RECT  86.496 43.008 86.52 43.2 ;
    END
  END qr_data[66]
  PIN qr_data[67]
    DIRECTION OUTPUT ;
    USE SIGNAL ;
    PORT
      LAYER M5 ;
        RECT  86.592 43.008 86.616 43.2 ;
    END
  END qr_data[67]
  PIN qr_data[68]
    DIRECTION OUTPUT ;
    USE SIGNAL ;
    PORT
      LAYER M5 ;
        RECT  86.688 43.008 86.712 43.2 ;
    END
  END qr_data[68]
  PIN qr_data[69]
    DIRECTION OUTPUT ;
    USE SIGNAL ;
    PORT
      LAYER M5 ;
        RECT  86.784 43.008 86.808 43.2 ;
    END
  END qr_data[69]
  PIN qr_data[6]
    DIRECTION OUTPUT ;
    USE SIGNAL ;
    PORT
      LAYER M5 ;
        RECT  80.736 43.008 80.76 43.2 ;
    END
  END qr_data[6]
  PIN qr_data[70]
    DIRECTION OUTPUT ;
    USE SIGNAL ;
    PORT
      LAYER M5 ;
        RECT  86.88 43.008 86.904 43.2 ;
    END
  END qr_data[70]
  PIN qr_data[71]
    DIRECTION OUTPUT ;
    USE SIGNAL ;
    PORT
      LAYER M5 ;
        RECT  86.976 43.008 87 43.2 ;
    END
  END qr_data[71]
  PIN qr_data[72]
    DIRECTION OUTPUT ;
    USE SIGNAL ;
    PORT
      LAYER M5 ;
        RECT  87.072 43.008 87.096 43.2 ;
    END
  END qr_data[72]
  PIN qr_data[73]
    DIRECTION OUTPUT ;
    USE SIGNAL ;
    PORT
      LAYER M5 ;
        RECT  87.168 43.008 87.192 43.2 ;
    END
  END qr_data[73]
  PIN qr_data[74]
    DIRECTION OUTPUT ;
    USE SIGNAL ;
    PORT
      LAYER M5 ;
        RECT  87.264 43.008 87.288 43.2 ;
    END
  END qr_data[74]
  PIN qr_data[75]
    DIRECTION OUTPUT ;
    USE SIGNAL ;
    PORT
      LAYER M5 ;
        RECT  87.36 43.008 87.384 43.2 ;
    END
  END qr_data[75]
  PIN qr_data[76]
    DIRECTION OUTPUT ;
    USE SIGNAL ;
    PORT
      LAYER M5 ;
        RECT  87.456 43.008 87.48 43.2 ;
    END
  END qr_data[76]
  PIN qr_data[77]
    DIRECTION OUTPUT ;
    USE SIGNAL ;
    PORT
      LAYER M5 ;
        RECT  87.552 43.008 87.576 43.2 ;
    END
  END qr_data[77]
  PIN qr_data[78]
    DIRECTION OUTPUT ;
    USE SIGNAL ;
    PORT
      LAYER M5 ;
        RECT  87.648 43.008 87.672 43.2 ;
    END
  END qr_data[78]
  PIN qr_data[79]
    DIRECTION OUTPUT ;
    USE SIGNAL ;
    PORT
      LAYER M5 ;
        RECT  87.744 43.008 87.768 43.2 ;
    END
  END qr_data[79]
  PIN qr_data[7]
    DIRECTION OUTPUT ;
    USE SIGNAL ;
    PORT
      LAYER M5 ;
        RECT  80.832 43.008 80.856 43.2 ;
    END
  END qr_data[7]
  PIN qr_data[80]
    DIRECTION OUTPUT ;
    USE SIGNAL ;
    PORT
      LAYER M5 ;
        RECT  87.84 43.008 87.864 43.2 ;
    END
  END qr_data[80]
  PIN qr_data[81]
    DIRECTION OUTPUT ;
    USE SIGNAL ;
    PORT
      LAYER M5 ;
        RECT  87.936 43.008 87.96 43.2 ;
    END
  END qr_data[81]
  PIN qr_data[82]
    DIRECTION OUTPUT ;
    USE SIGNAL ;
    PORT
      LAYER M5 ;
        RECT  88.032 43.008 88.056 43.2 ;
    END
  END qr_data[82]
  PIN qr_data[83]
    DIRECTION OUTPUT ;
    USE SIGNAL ;
    PORT
      LAYER M5 ;
        RECT  88.128 43.008 88.152 43.2 ;
    END
  END qr_data[83]
  PIN qr_data[84]
    DIRECTION OUTPUT ;
    USE SIGNAL ;
    PORT
      LAYER M5 ;
        RECT  88.224 43.008 88.248 43.2 ;
    END
  END qr_data[84]
  PIN qr_data[85]
    DIRECTION OUTPUT ;
    USE SIGNAL ;
    PORT
      LAYER M5 ;
        RECT  88.32 43.008 88.344 43.2 ;
    END
  END qr_data[85]
  PIN qr_data[86]
    DIRECTION OUTPUT ;
    USE SIGNAL ;
    PORT
      LAYER M5 ;
        RECT  88.416 43.008 88.44 43.2 ;
    END
  END qr_data[86]
  PIN qr_data[87]
    DIRECTION OUTPUT ;
    USE SIGNAL ;
    PORT
      LAYER M5 ;
        RECT  88.512 43.008 88.536 43.2 ;
    END
  END qr_data[87]
  PIN qr_data[88]
    DIRECTION OUTPUT ;
    USE SIGNAL ;
    PORT
      LAYER M5 ;
        RECT  88.608 43.008 88.632 43.2 ;
    END
  END qr_data[88]
  PIN qr_data[89]
    DIRECTION OUTPUT ;
    USE SIGNAL ;
    PORT
      LAYER M5 ;
        RECT  88.704 43.008 88.728 43.2 ;
    END
  END qr_data[89]
  PIN qr_data[8]
    DIRECTION OUTPUT ;
    USE SIGNAL ;
    PORT
      LAYER M5 ;
        RECT  80.928 43.008 80.952 43.2 ;
    END
  END qr_data[8]
  PIN qr_data[90]
    DIRECTION OUTPUT ;
    USE SIGNAL ;
    PORT
      LAYER M5 ;
        RECT  88.8 43.008 88.824 43.2 ;
    END
  END qr_data[90]
  PIN qr_data[91]
    DIRECTION OUTPUT ;
    USE SIGNAL ;
    PORT
      LAYER M5 ;
        RECT  88.896 43.008 88.92 43.2 ;
    END
  END qr_data[91]
  PIN qr_data[92]
    DIRECTION OUTPUT ;
    USE SIGNAL ;
    PORT
      LAYER M5 ;
        RECT  88.992 43.008 89.016 43.2 ;
    END
  END qr_data[92]
  PIN qr_data[93]
    DIRECTION OUTPUT ;
    USE SIGNAL ;
    PORT
      LAYER M5 ;
        RECT  89.088 43.008 89.112 43.2 ;
    END
  END qr_data[93]
  PIN qr_data[94]
    DIRECTION OUTPUT ;
    USE SIGNAL ;
    PORT
      LAYER M5 ;
        RECT  89.184 43.008 89.208 43.2 ;
    END
  END qr_data[94]
  PIN qr_data[95]
    DIRECTION OUTPUT ;
    USE SIGNAL ;
    PORT
      LAYER M5 ;
        RECT  89.28 43.008 89.304 43.2 ;
    END
  END qr_data[95]
  PIN qr_data[96]
    DIRECTION OUTPUT ;
    USE SIGNAL ;
    PORT
      LAYER M5 ;
        RECT  89.376 43.008 89.4 43.2 ;
    END
  END qr_data[96]
  PIN qr_data[97]
    DIRECTION OUTPUT ;
    USE SIGNAL ;
    PORT
      LAYER M5 ;
        RECT  89.472 43.008 89.496 43.2 ;
    END
  END qr_data[97]
  PIN qr_data[98]
    DIRECTION OUTPUT ;
    USE SIGNAL ;
    PORT
      LAYER M5 ;
        RECT  89.568 43.008 89.592 43.2 ;
    END
  END qr_data[98]
  PIN qr_data[99]
    DIRECTION OUTPUT ;
    USE SIGNAL ;
    PORT
      LAYER M5 ;
        RECT  89.664 43.008 89.688 43.2 ;
    END
  END qr_data[99]
  PIN qr_data[9]
    DIRECTION OUTPUT ;
    USE SIGNAL ;
    PORT
      LAYER M5 ;
        RECT  81.024 43.008 81.048 43.2 ;
    END
  END qr_data[9]
  PIN qr_tag[0]
    DIRECTION OUTPUT ;
    USE SIGNAL ;
    PORT
      LAYER M5 ;
        RECT  104.736 43.008 104.76 43.2 ;
    END
  END qr_tag[0]
  PIN qr_tag[10]
    DIRECTION OUTPUT ;
    USE SIGNAL ;
    PORT
      LAYER M5 ;
        RECT  105.696 43.008 105.72 43.2 ;
    END
  END qr_tag[10]
  PIN qr_tag[11]
    DIRECTION OUTPUT ;
    USE SIGNAL ;
    PORT
      LAYER M5 ;
        RECT  105.792 43.008 105.816 43.2 ;
    END
  END qr_tag[11]
  PIN qr_tag[12]
    DIRECTION OUTPUT ;
    USE SIGNAL ;
    PORT
      LAYER M5 ;
        RECT  105.888 43.008 105.912 43.2 ;
    END
  END qr_tag[12]
  PIN qr_tag[13]
    DIRECTION OUTPUT ;
    USE SIGNAL ;
    PORT
      LAYER M5 ;
        RECT  105.984 43.008 106.008 43.2 ;
    END
  END qr_tag[13]
  PIN qr_tag[14]
    DIRECTION OUTPUT ;
    USE SIGNAL ;
    PORT
      LAYER M5 ;
        RECT  106.08 43.008 106.104 43.2 ;
    END
  END qr_tag[14]
  PIN qr_tag[15]
    DIRECTION OUTPUT ;
    USE SIGNAL ;
    PORT
      LAYER M5 ;
        RECT  106.176 43.008 106.2 43.2 ;
    END
  END qr_tag[15]
  PIN qr_tag[16]
    DIRECTION OUTPUT ;
    USE SIGNAL ;
    PORT
      LAYER M5 ;
        RECT  106.272 43.008 106.296 43.2 ;
    END
  END qr_tag[16]
  PIN qr_tag[1]
    DIRECTION OUTPUT ;
    USE SIGNAL ;
    PORT
      LAYER M5 ;
        RECT  104.832 43.008 104.856 43.2 ;
    END
  END qr_tag[1]
  PIN qr_tag[2]
    DIRECTION OUTPUT ;
    USE SIGNAL ;
    PORT
      LAYER M5 ;
        RECT  104.928 43.008 104.952 43.2 ;
    END
  END qr_tag[2]
  PIN qr_tag[3]
    DIRECTION OUTPUT ;
    USE SIGNAL ;
    PORT
      LAYER M5 ;
        RECT  105.024 43.008 105.048 43.2 ;
    END
  END qr_tag[3]
  PIN qr_tag[4]
    DIRECTION OUTPUT ;
    USE SIGNAL ;
    PORT
      LAYER M5 ;
        RECT  105.12 43.008 105.144 43.2 ;
    END
  END qr_tag[4]
  PIN qr_tag[5]
    DIRECTION OUTPUT ;
    USE SIGNAL ;
    PORT
      LAYER M5 ;
        RECT  105.216 43.008 105.24 43.2 ;
    END
  END qr_tag[5]
  PIN qr_tag[6]
    DIRECTION OUTPUT ;
    USE SIGNAL ;
    PORT
      LAYER M5 ;
        RECT  105.312 43.008 105.336 43.2 ;
    END
  END qr_tag[6]
  PIN qr_tag[7]
    DIRECTION OUTPUT ;
    USE SIGNAL ;
    PORT
      LAYER M5 ;
        RECT  105.408 43.008 105.432 43.2 ;
    END
  END qr_tag[7]
  PIN qr_tag[8]
    DIRECTION OUTPUT ;
    USE SIGNAL ;
    PORT
      LAYER M5 ;
        RECT  105.504 43.008 105.528 43.2 ;
    END
  END qr_tag[8]
  PIN qr_tag[9]
    DIRECTION OUTPUT ;
    USE SIGNAL ;
    PORT
      LAYER M5 ;
        RECT  105.6 43.008 105.624 43.2 ;
    END
  END qr_tag[9]
  PIN qrk[0]
    DIRECTION OUTPUT ;
    USE SIGNAL ;
    PORT
      LAYER M5 ;
        RECT  50.064 43.008 50.088 43.2 ;
    END
  END qrk[0]
  PIN qrq[0]
    DIRECTION INPUT ;
    USE SIGNAL ;
    PORT
      LAYER M5 ;
        RECT  17.328 43.008 17.352 43.2 ;
    END
  END qrq[0]
  PIN qrq[100]
    DIRECTION INPUT ;
    USE SIGNAL ;
    PORT
      LAYER M5 ;
        RECT  26.928 43.008 26.952 43.2 ;
    END
  END qrq[100]
  PIN qrq[101]
    DIRECTION INPUT ;
    USE SIGNAL ;
    PORT
      LAYER M5 ;
        RECT  27.024 43.008 27.048 43.2 ;
    END
  END qrq[101]
  PIN qrq[102]
    DIRECTION INPUT ;
    USE SIGNAL ;
    PORT
      LAYER M5 ;
        RECT  27.12 43.008 27.144 43.2 ;
    END
  END qrq[102]
  PIN qrq[103]
    DIRECTION INPUT ;
    USE SIGNAL ;
    PORT
      LAYER M5 ;
        RECT  27.216 43.008 27.24 43.2 ;
    END
  END qrq[103]
  PIN qrq[104]
    DIRECTION INPUT ;
    USE SIGNAL ;
    PORT
      LAYER M5 ;
        RECT  27.312 43.008 27.336 43.2 ;
    END
  END qrq[104]
  PIN qrq[105]
    DIRECTION INPUT ;
    USE SIGNAL ;
    PORT
      LAYER M5 ;
        RECT  27.408 43.008 27.432 43.2 ;
    END
  END qrq[105]
  PIN qrq[106]
    DIRECTION INPUT ;
    USE SIGNAL ;
    PORT
      LAYER M5 ;
        RECT  27.504 43.008 27.528 43.2 ;
    END
  END qrq[106]
  PIN qrq[107]
    DIRECTION INPUT ;
    USE SIGNAL ;
    PORT
      LAYER M5 ;
        RECT  27.6 43.008 27.624 43.2 ;
    END
  END qrq[107]
  PIN qrq[108]
    DIRECTION INPUT ;
    USE SIGNAL ;
    PORT
      LAYER M5 ;
        RECT  27.696 43.008 27.72 43.2 ;
    END
  END qrq[108]
  PIN qrq[109]
    DIRECTION INPUT ;
    USE SIGNAL ;
    PORT
      LAYER M5 ;
        RECT  27.792 43.008 27.816 43.2 ;
    END
  END qrq[109]
  PIN qrq[10]
    DIRECTION INPUT ;
    USE SIGNAL ;
    PORT
      LAYER M5 ;
        RECT  18.288 43.008 18.312 43.2 ;
    END
  END qrq[10]
  PIN qrq[110]
    DIRECTION INPUT ;
    USE SIGNAL ;
    PORT
      LAYER M5 ;
        RECT  27.888 43.008 27.912 43.2 ;
    END
  END qrq[110]
  PIN qrq[111]
    DIRECTION INPUT ;
    USE SIGNAL ;
    PORT
      LAYER M5 ;
        RECT  27.984 43.008 28.008 43.2 ;
    END
  END qrq[111]
  PIN qrq[112]
    DIRECTION INPUT ;
    USE SIGNAL ;
    PORT
      LAYER M5 ;
        RECT  28.08 43.008 28.104 43.2 ;
    END
  END qrq[112]
  PIN qrq[113]
    DIRECTION INPUT ;
    USE SIGNAL ;
    PORT
      LAYER M5 ;
        RECT  28.176 43.008 28.2 43.2 ;
    END
  END qrq[113]
  PIN qrq[114]
    DIRECTION INPUT ;
    USE SIGNAL ;
    PORT
      LAYER M5 ;
        RECT  28.272 43.008 28.296 43.2 ;
    END
  END qrq[114]
  PIN qrq[115]
    DIRECTION INPUT ;
    USE SIGNAL ;
    PORT
      LAYER M5 ;
        RECT  28.368 43.008 28.392 43.2 ;
    END
  END qrq[115]
  PIN qrq[116]
    DIRECTION INPUT ;
    USE SIGNAL ;
    PORT
      LAYER M5 ;
        RECT  28.464 43.008 28.488 43.2 ;
    END
  END qrq[116]
  PIN qrq[117]
    DIRECTION INPUT ;
    USE SIGNAL ;
    PORT
      LAYER M5 ;
        RECT  28.56 43.008 28.584 43.2 ;
    END
  END qrq[117]
  PIN qrq[118]
    DIRECTION INPUT ;
    USE SIGNAL ;
    PORT
      LAYER M5 ;
        RECT  28.656 43.008 28.68 43.2 ;
    END
  END qrq[118]
  PIN qrq[119]
    DIRECTION INPUT ;
    USE SIGNAL ;
    PORT
      LAYER M5 ;
        RECT  28.752 43.008 28.776 43.2 ;
    END
  END qrq[119]
  PIN qrq[11]
    DIRECTION INPUT ;
    USE SIGNAL ;
    PORT
      LAYER M5 ;
        RECT  18.384 43.008 18.408 43.2 ;
    END
  END qrq[11]
  PIN qrq[120]
    DIRECTION INPUT ;
    USE SIGNAL ;
    PORT
      LAYER M5 ;
        RECT  28.848 43.008 28.872 43.2 ;
    END
  END qrq[120]
  PIN qrq[121]
    DIRECTION INPUT ;
    USE SIGNAL ;
    PORT
      LAYER M5 ;
        RECT  28.944 43.008 28.968 43.2 ;
    END
  END qrq[121]
  PIN qrq[122]
    DIRECTION INPUT ;
    USE SIGNAL ;
    PORT
      LAYER M5 ;
        RECT  29.04 43.008 29.064 43.2 ;
    END
  END qrq[122]
  PIN qrq[123]
    DIRECTION INPUT ;
    USE SIGNAL ;
    PORT
      LAYER M5 ;
        RECT  29.136 43.008 29.16 43.2 ;
    END
  END qrq[123]
  PIN qrq[124]
    DIRECTION INPUT ;
    USE SIGNAL ;
    PORT
      LAYER M5 ;
        RECT  29.232 43.008 29.256 43.2 ;
    END
  END qrq[124]
  PIN qrq[125]
    DIRECTION INPUT ;
    USE SIGNAL ;
    PORT
      LAYER M5 ;
        RECT  29.328 43.008 29.352 43.2 ;
    END
  END qrq[125]
  PIN qrq[126]
    DIRECTION INPUT ;
    USE SIGNAL ;
    PORT
      LAYER M5 ;
        RECT  29.424 43.008 29.448 43.2 ;
    END
  END qrq[126]
  PIN qrq[127]
    DIRECTION INPUT ;
    USE SIGNAL ;
    PORT
      LAYER M5 ;
        RECT  29.52 43.008 29.544 43.2 ;
    END
  END qrq[127]
  PIN qrq[128]
    DIRECTION INPUT ;
    USE SIGNAL ;
    PORT
      LAYER M5 ;
        RECT  29.616 43.008 29.64 43.2 ;
    END
  END qrq[128]
  PIN qrq[129]
    DIRECTION INPUT ;
    USE SIGNAL ;
    PORT
      LAYER M5 ;
        RECT  29.712 43.008 29.736 43.2 ;
    END
  END qrq[129]
  PIN qrq[12]
    DIRECTION INPUT ;
    USE SIGNAL ;
    PORT
      LAYER M5 ;
        RECT  18.48 43.008 18.504 43.2 ;
    END
  END qrq[12]
  PIN qrq[130]
    DIRECTION INPUT ;
    USE SIGNAL ;
    PORT
      LAYER M5 ;
        RECT  29.808 43.008 29.832 43.2 ;
    END
  END qrq[130]
  PIN qrq[131]
    DIRECTION INPUT ;
    USE SIGNAL ;
    PORT
      LAYER M5 ;
        RECT  29.904 43.008 29.928 43.2 ;
    END
  END qrq[131]
  PIN qrq[132]
    DIRECTION INPUT ;
    USE SIGNAL ;
    PORT
      LAYER M5 ;
        RECT  30 43.008 30.024 43.2 ;
    END
  END qrq[132]
  PIN qrq[133]
    DIRECTION INPUT ;
    USE SIGNAL ;
    PORT
      LAYER M5 ;
        RECT  30.096 43.008 30.12 43.2 ;
    END
  END qrq[133]
  PIN qrq[134]
    DIRECTION INPUT ;
    USE SIGNAL ;
    PORT
      LAYER M5 ;
        RECT  30.192 43.008 30.216 43.2 ;
    END
  END qrq[134]
  PIN qrq[135]
    DIRECTION INPUT ;
    USE SIGNAL ;
    PORT
      LAYER M5 ;
        RECT  30.288 43.008 30.312 43.2 ;
    END
  END qrq[135]
  PIN qrq[136]
    DIRECTION INPUT ;
    USE SIGNAL ;
    PORT
      LAYER M5 ;
        RECT  30.384 43.008 30.408 43.2 ;
    END
  END qrq[136]
  PIN qrq[137]
    DIRECTION INPUT ;
    USE SIGNAL ;
    PORT
      LAYER M5 ;
        RECT  30.48 43.008 30.504 43.2 ;
    END
  END qrq[137]
  PIN qrq[138]
    DIRECTION INPUT ;
    USE SIGNAL ;
    PORT
      LAYER M5 ;
        RECT  30.576 43.008 30.6 43.2 ;
    END
  END qrq[138]
  PIN qrq[139]
    DIRECTION INPUT ;
    USE SIGNAL ;
    PORT
      LAYER M5 ;
        RECT  30.672 43.008 30.696 43.2 ;
    END
  END qrq[139]
  PIN qrq[13]
    DIRECTION INPUT ;
    USE SIGNAL ;
    PORT
      LAYER M5 ;
        RECT  18.576 43.008 18.6 43.2 ;
    END
  END qrq[13]
  PIN qrq[140]
    DIRECTION INPUT ;
    USE SIGNAL ;
    PORT
      LAYER M5 ;
        RECT  30.768 43.008 30.792 43.2 ;
    END
  END qrq[140]
  PIN qrq[141]
    DIRECTION INPUT ;
    USE SIGNAL ;
    PORT
      LAYER M5 ;
        RECT  30.864 43.008 30.888 43.2 ;
    END
  END qrq[141]
  PIN qrq[142]
    DIRECTION INPUT ;
    USE SIGNAL ;
    PORT
      LAYER M5 ;
        RECT  30.96 43.008 30.984 43.2 ;
    END
  END qrq[142]
  PIN qrq[143]
    DIRECTION INPUT ;
    USE SIGNAL ;
    PORT
      LAYER M5 ;
        RECT  31.056 43.008 31.08 43.2 ;
    END
  END qrq[143]
  PIN qrq[144]
    DIRECTION INPUT ;
    USE SIGNAL ;
    PORT
      LAYER M5 ;
        RECT  31.152 43.008 31.176 43.2 ;
    END
  END qrq[144]
  PIN qrq[145]
    DIRECTION INPUT ;
    USE SIGNAL ;
    PORT
      LAYER M5 ;
        RECT  31.248 43.008 31.272 43.2 ;
    END
  END qrq[145]
  PIN qrq[146]
    DIRECTION INPUT ;
    USE SIGNAL ;
    PORT
      LAYER M5 ;
        RECT  31.344 43.008 31.368 43.2 ;
    END
  END qrq[146]
  PIN qrq[147]
    DIRECTION INPUT ;
    USE SIGNAL ;
    PORT
      LAYER M5 ;
        RECT  31.44 43.008 31.464 43.2 ;
    END
  END qrq[147]
  PIN qrq[148]
    DIRECTION INPUT ;
    USE SIGNAL ;
    PORT
      LAYER M5 ;
        RECT  31.536 43.008 31.56 43.2 ;
    END
  END qrq[148]
  PIN qrq[149]
    DIRECTION INPUT ;
    USE SIGNAL ;
    PORT
      LAYER M5 ;
        RECT  31.632 43.008 31.656 43.2 ;
    END
  END qrq[149]
  PIN qrq[14]
    DIRECTION INPUT ;
    USE SIGNAL ;
    PORT
      LAYER M5 ;
        RECT  18.672 43.008 18.696 43.2 ;
    END
  END qrq[14]
  PIN qrq[150]
    DIRECTION INPUT ;
    USE SIGNAL ;
    PORT
      LAYER M5 ;
        RECT  31.728 43.008 31.752 43.2 ;
    END
  END qrq[150]
  PIN qrq[151]
    DIRECTION INPUT ;
    USE SIGNAL ;
    PORT
      LAYER M5 ;
        RECT  31.824 43.008 31.848 43.2 ;
    END
  END qrq[151]
  PIN qrq[152]
    DIRECTION INPUT ;
    USE SIGNAL ;
    PORT
      LAYER M5 ;
        RECT  31.92 43.008 31.944 43.2 ;
    END
  END qrq[152]
  PIN qrq[153]
    DIRECTION INPUT ;
    USE SIGNAL ;
    PORT
      LAYER M5 ;
        RECT  32.016 43.008 32.04 43.2 ;
    END
  END qrq[153]
  PIN qrq[154]
    DIRECTION INPUT ;
    USE SIGNAL ;
    PORT
      LAYER M5 ;
        RECT  32.112 43.008 32.136 43.2 ;
    END
  END qrq[154]
  PIN qrq[155]
    DIRECTION INPUT ;
    USE SIGNAL ;
    PORT
      LAYER M5 ;
        RECT  32.208 43.008 32.232 43.2 ;
    END
  END qrq[155]
  PIN qrq[156]
    DIRECTION INPUT ;
    USE SIGNAL ;
    PORT
      LAYER M5 ;
        RECT  32.304 43.008 32.328 43.2 ;
    END
  END qrq[156]
  PIN qrq[157]
    DIRECTION INPUT ;
    USE SIGNAL ;
    PORT
      LAYER M5 ;
        RECT  32.4 43.008 32.424 43.2 ;
    END
  END qrq[157]
  PIN qrq[158]
    DIRECTION INPUT ;
    USE SIGNAL ;
    PORT
      LAYER M5 ;
        RECT  32.496 43.008 32.52 43.2 ;
    END
  END qrq[158]
  PIN qrq[159]
    DIRECTION INPUT ;
    USE SIGNAL ;
    PORT
      LAYER M5 ;
        RECT  32.592 43.008 32.616 43.2 ;
    END
  END qrq[159]
  PIN qrq[15]
    DIRECTION INPUT ;
    USE SIGNAL ;
    PORT
      LAYER M5 ;
        RECT  18.768 43.008 18.792 43.2 ;
    END
  END qrq[15]
  PIN qrq[160]
    DIRECTION INPUT ;
    USE SIGNAL ;
    PORT
      LAYER M5 ;
        RECT  32.688 43.008 32.712 43.2 ;
    END
  END qrq[160]
  PIN qrq[161]
    DIRECTION INPUT ;
    USE SIGNAL ;
    PORT
      LAYER M5 ;
        RECT  32.784 43.008 32.808 43.2 ;
    END
  END qrq[161]
  PIN qrq[162]
    DIRECTION INPUT ;
    USE SIGNAL ;
    PORT
      LAYER M5 ;
        RECT  32.88 43.008 32.904 43.2 ;
    END
  END qrq[162]
  PIN qrq[163]
    DIRECTION INPUT ;
    USE SIGNAL ;
    PORT
      LAYER M5 ;
        RECT  32.976 43.008 33 43.2 ;
    END
  END qrq[163]
  PIN qrq[164]
    DIRECTION INPUT ;
    USE SIGNAL ;
    PORT
      LAYER M5 ;
        RECT  33.072 43.008 33.096 43.2 ;
    END
  END qrq[164]
  PIN qrq[165]
    DIRECTION INPUT ;
    USE SIGNAL ;
    PORT
      LAYER M5 ;
        RECT  33.168 43.008 33.192 43.2 ;
    END
  END qrq[165]
  PIN qrq[166]
    DIRECTION INPUT ;
    USE SIGNAL ;
    PORT
      LAYER M5 ;
        RECT  33.264 43.008 33.288 43.2 ;
    END
  END qrq[166]
  PIN qrq[167]
    DIRECTION INPUT ;
    USE SIGNAL ;
    PORT
      LAYER M5 ;
        RECT  33.36 43.008 33.384 43.2 ;
    END
  END qrq[167]
  PIN qrq[168]
    DIRECTION INPUT ;
    USE SIGNAL ;
    PORT
      LAYER M5 ;
        RECT  33.456 43.008 33.48 43.2 ;
    END
  END qrq[168]
  PIN qrq[169]
    DIRECTION INPUT ;
    USE SIGNAL ;
    PORT
      LAYER M5 ;
        RECT  33.552 43.008 33.576 43.2 ;
    END
  END qrq[169]
  PIN qrq[16]
    DIRECTION INPUT ;
    USE SIGNAL ;
    PORT
      LAYER M5 ;
        RECT  18.864 43.008 18.888 43.2 ;
    END
  END qrq[16]
  PIN qrq[170]
    DIRECTION INPUT ;
    USE SIGNAL ;
    PORT
      LAYER M5 ;
        RECT  33.648 43.008 33.672 43.2 ;
    END
  END qrq[170]
  PIN qrq[171]
    DIRECTION INPUT ;
    USE SIGNAL ;
    PORT
      LAYER M5 ;
        RECT  33.744 43.008 33.768 43.2 ;
    END
  END qrq[171]
  PIN qrq[172]
    DIRECTION INPUT ;
    USE SIGNAL ;
    PORT
      LAYER M5 ;
        RECT  33.84 43.008 33.864 43.2 ;
    END
  END qrq[172]
  PIN qrq[173]
    DIRECTION INPUT ;
    USE SIGNAL ;
    PORT
      LAYER M5 ;
        RECT  33.936 43.008 33.96 43.2 ;
    END
  END qrq[173]
  PIN qrq[174]
    DIRECTION INPUT ;
    USE SIGNAL ;
    PORT
      LAYER M5 ;
        RECT  34.032 43.008 34.056 43.2 ;
    END
  END qrq[174]
  PIN qrq[175]
    DIRECTION INPUT ;
    USE SIGNAL ;
    PORT
      LAYER M5 ;
        RECT  34.128 43.008 34.152 43.2 ;
    END
  END qrq[175]
  PIN qrq[176]
    DIRECTION INPUT ;
    USE SIGNAL ;
    PORT
      LAYER M5 ;
        RECT  34.224 43.008 34.248 43.2 ;
    END
  END qrq[176]
  PIN qrq[177]
    DIRECTION INPUT ;
    USE SIGNAL ;
    PORT
      LAYER M5 ;
        RECT  34.32 43.008 34.344 43.2 ;
    END
  END qrq[177]
  PIN qrq[178]
    DIRECTION INPUT ;
    USE SIGNAL ;
    PORT
      LAYER M5 ;
        RECT  34.416 43.008 34.44 43.2 ;
    END
  END qrq[178]
  PIN qrq[179]
    DIRECTION INPUT ;
    USE SIGNAL ;
    PORT
      LAYER M5 ;
        RECT  34.512 43.008 34.536 43.2 ;
    END
  END qrq[179]
  PIN qrq[17]
    DIRECTION INPUT ;
    USE SIGNAL ;
    PORT
      LAYER M5 ;
        RECT  18.96 43.008 18.984 43.2 ;
    END
  END qrq[17]
  PIN qrq[180]
    DIRECTION INPUT ;
    USE SIGNAL ;
    PORT
      LAYER M5 ;
        RECT  34.608 43.008 34.632 43.2 ;
    END
  END qrq[180]
  PIN qrq[181]
    DIRECTION INPUT ;
    USE SIGNAL ;
    PORT
      LAYER M5 ;
        RECT  34.704 43.008 34.728 43.2 ;
    END
  END qrq[181]
  PIN qrq[182]
    DIRECTION INPUT ;
    USE SIGNAL ;
    PORT
      LAYER M5 ;
        RECT  34.8 43.008 34.824 43.2 ;
    END
  END qrq[182]
  PIN qrq[183]
    DIRECTION INPUT ;
    USE SIGNAL ;
    PORT
      LAYER M5 ;
        RECT  34.896 43.008 34.92 43.2 ;
    END
  END qrq[183]
  PIN qrq[184]
    DIRECTION INPUT ;
    USE SIGNAL ;
    PORT
      LAYER M5 ;
        RECT  34.992 43.008 35.016 43.2 ;
    END
  END qrq[184]
  PIN qrq[185]
    DIRECTION INPUT ;
    USE SIGNAL ;
    PORT
      LAYER M5 ;
        RECT  35.088 43.008 35.112 43.2 ;
    END
  END qrq[185]
  PIN qrq[186]
    DIRECTION INPUT ;
    USE SIGNAL ;
    PORT
      LAYER M5 ;
        RECT  35.184 43.008 35.208 43.2 ;
    END
  END qrq[186]
  PIN qrq[187]
    DIRECTION INPUT ;
    USE SIGNAL ;
    PORT
      LAYER M5 ;
        RECT  35.28 43.008 35.304 43.2 ;
    END
  END qrq[187]
  PIN qrq[188]
    DIRECTION INPUT ;
    USE SIGNAL ;
    PORT
      LAYER M5 ;
        RECT  35.376 43.008 35.4 43.2 ;
    END
  END qrq[188]
  PIN qrq[189]
    DIRECTION INPUT ;
    USE SIGNAL ;
    PORT
      LAYER M5 ;
        RECT  35.472 43.008 35.496 43.2 ;
    END
  END qrq[189]
  PIN qrq[18]
    DIRECTION INPUT ;
    USE SIGNAL ;
    PORT
      LAYER M5 ;
        RECT  19.056 43.008 19.08 43.2 ;
    END
  END qrq[18]
  PIN qrq[190]
    DIRECTION INPUT ;
    USE SIGNAL ;
    PORT
      LAYER M5 ;
        RECT  35.568 43.008 35.592 43.2 ;
    END
  END qrq[190]
  PIN qrq[191]
    DIRECTION INPUT ;
    USE SIGNAL ;
    PORT
      LAYER M5 ;
        RECT  35.664 43.008 35.688 43.2 ;
    END
  END qrq[191]
  PIN qrq[192]
    DIRECTION INPUT ;
    USE SIGNAL ;
    PORT
      LAYER M5 ;
        RECT  35.76 43.008 35.784 43.2 ;
    END
  END qrq[192]
  PIN qrq[193]
    DIRECTION INPUT ;
    USE SIGNAL ;
    PORT
      LAYER M5 ;
        RECT  35.856 43.008 35.88 43.2 ;
    END
  END qrq[193]
  PIN qrq[194]
    DIRECTION INPUT ;
    USE SIGNAL ;
    PORT
      LAYER M5 ;
        RECT  35.952 43.008 35.976 43.2 ;
    END
  END qrq[194]
  PIN qrq[195]
    DIRECTION INPUT ;
    USE SIGNAL ;
    PORT
      LAYER M5 ;
        RECT  36.048 43.008 36.072 43.2 ;
    END
  END qrq[195]
  PIN qrq[196]
    DIRECTION INPUT ;
    USE SIGNAL ;
    PORT
      LAYER M5 ;
        RECT  36.144 43.008 36.168 43.2 ;
    END
  END qrq[196]
  PIN qrq[197]
    DIRECTION INPUT ;
    USE SIGNAL ;
    PORT
      LAYER M5 ;
        RECT  36.24 43.008 36.264 43.2 ;
    END
  END qrq[197]
  PIN qrq[198]
    DIRECTION INPUT ;
    USE SIGNAL ;
    PORT
      LAYER M5 ;
        RECT  36.336 43.008 36.36 43.2 ;
    END
  END qrq[198]
  PIN qrq[199]
    DIRECTION INPUT ;
    USE SIGNAL ;
    PORT
      LAYER M5 ;
        RECT  36.432 43.008 36.456 43.2 ;
    END
  END qrq[199]
  PIN qrq[19]
    DIRECTION INPUT ;
    USE SIGNAL ;
    PORT
      LAYER M5 ;
        RECT  19.152 43.008 19.176 43.2 ;
    END
  END qrq[19]
  PIN qrq[1]
    DIRECTION INPUT ;
    USE SIGNAL ;
    PORT
      LAYER M5 ;
        RECT  17.424 43.008 17.448 43.2 ;
    END
  END qrq[1]
  PIN qrq[200]
    DIRECTION INPUT ;
    USE SIGNAL ;
    PORT
      LAYER M5 ;
        RECT  36.528 43.008 36.552 43.2 ;
    END
  END qrq[200]
  PIN qrq[201]
    DIRECTION INPUT ;
    USE SIGNAL ;
    PORT
      LAYER M5 ;
        RECT  36.624 43.008 36.648 43.2 ;
    END
  END qrq[201]
  PIN qrq[202]
    DIRECTION INPUT ;
    USE SIGNAL ;
    PORT
      LAYER M5 ;
        RECT  36.72 43.008 36.744 43.2 ;
    END
  END qrq[202]
  PIN qrq[203]
    DIRECTION INPUT ;
    USE SIGNAL ;
    PORT
      LAYER M5 ;
        RECT  36.816 43.008 36.84 43.2 ;
    END
  END qrq[203]
  PIN qrq[204]
    DIRECTION INPUT ;
    USE SIGNAL ;
    PORT
      LAYER M5 ;
        RECT  36.912 43.008 36.936 43.2 ;
    END
  END qrq[204]
  PIN qrq[205]
    DIRECTION INPUT ;
    USE SIGNAL ;
    PORT
      LAYER M5 ;
        RECT  37.008 43.008 37.032 43.2 ;
    END
  END qrq[205]
  PIN qrq[206]
    DIRECTION INPUT ;
    USE SIGNAL ;
    PORT
      LAYER M5 ;
        RECT  37.104 43.008 37.128 43.2 ;
    END
  END qrq[206]
  PIN qrq[207]
    DIRECTION INPUT ;
    USE SIGNAL ;
    PORT
      LAYER M5 ;
        RECT  37.2 43.008 37.224 43.2 ;
    END
  END qrq[207]
  PIN qrq[208]
    DIRECTION INPUT ;
    USE SIGNAL ;
    PORT
      LAYER M5 ;
        RECT  37.296 43.008 37.32 43.2 ;
    END
  END qrq[208]
  PIN qrq[209]
    DIRECTION INPUT ;
    USE SIGNAL ;
    PORT
      LAYER M5 ;
        RECT  37.392 43.008 37.416 43.2 ;
    END
  END qrq[209]
  PIN qrq[20]
    DIRECTION INPUT ;
    USE SIGNAL ;
    PORT
      LAYER M5 ;
        RECT  19.248 43.008 19.272 43.2 ;
    END
  END qrq[20]
  PIN qrq[210]
    DIRECTION INPUT ;
    USE SIGNAL ;
    PORT
      LAYER M5 ;
        RECT  37.488 43.008 37.512 43.2 ;
    END
  END qrq[210]
  PIN qrq[211]
    DIRECTION INPUT ;
    USE SIGNAL ;
    PORT
      LAYER M5 ;
        RECT  37.584 43.008 37.608 43.2 ;
    END
  END qrq[211]
  PIN qrq[212]
    DIRECTION INPUT ;
    USE SIGNAL ;
    PORT
      LAYER M5 ;
        RECT  37.68 43.008 37.704 43.2 ;
    END
  END qrq[212]
  PIN qrq[213]
    DIRECTION INPUT ;
    USE SIGNAL ;
    PORT
      LAYER M5 ;
        RECT  37.776 43.008 37.8 43.2 ;
    END
  END qrq[213]
  PIN qrq[214]
    DIRECTION INPUT ;
    USE SIGNAL ;
    PORT
      LAYER M5 ;
        RECT  37.872 43.008 37.896 43.2 ;
    END
  END qrq[214]
  PIN qrq[215]
    DIRECTION INPUT ;
    USE SIGNAL ;
    PORT
      LAYER M5 ;
        RECT  37.968 43.008 37.992 43.2 ;
    END
  END qrq[215]
  PIN qrq[216]
    DIRECTION INPUT ;
    USE SIGNAL ;
    PORT
      LAYER M5 ;
        RECT  38.064 43.008 38.088 43.2 ;
    END
  END qrq[216]
  PIN qrq[217]
    DIRECTION INPUT ;
    USE SIGNAL ;
    PORT
      LAYER M5 ;
        RECT  38.16 43.008 38.184 43.2 ;
    END
  END qrq[217]
  PIN qrq[218]
    DIRECTION INPUT ;
    USE SIGNAL ;
    PORT
      LAYER M5 ;
        RECT  38.256 43.008 38.28 43.2 ;
    END
  END qrq[218]
  PIN qrq[219]
    DIRECTION INPUT ;
    USE SIGNAL ;
    PORT
      LAYER M5 ;
        RECT  38.352 43.008 38.376 43.2 ;
    END
  END qrq[219]
  PIN qrq[21]
    DIRECTION INPUT ;
    USE SIGNAL ;
    PORT
      LAYER M5 ;
        RECT  19.344 43.008 19.368 43.2 ;
    END
  END qrq[21]
  PIN qrq[220]
    DIRECTION INPUT ;
    USE SIGNAL ;
    PORT
      LAYER M5 ;
        RECT  38.448 43.008 38.472 43.2 ;
    END
  END qrq[220]
  PIN qrq[221]
    DIRECTION INPUT ;
    USE SIGNAL ;
    PORT
      LAYER M5 ;
        RECT  38.544 43.008 38.568 43.2 ;
    END
  END qrq[221]
  PIN qrq[222]
    DIRECTION INPUT ;
    USE SIGNAL ;
    PORT
      LAYER M5 ;
        RECT  38.64 43.008 38.664 43.2 ;
    END
  END qrq[222]
  PIN qrq[223]
    DIRECTION INPUT ;
    USE SIGNAL ;
    PORT
      LAYER M5 ;
        RECT  38.736 43.008 38.76 43.2 ;
    END
  END qrq[223]
  PIN qrq[224]
    DIRECTION INPUT ;
    USE SIGNAL ;
    PORT
      LAYER M5 ;
        RECT  38.832 43.008 38.856 43.2 ;
    END
  END qrq[224]
  PIN qrq[225]
    DIRECTION INPUT ;
    USE SIGNAL ;
    PORT
      LAYER M5 ;
        RECT  38.928 43.008 38.952 43.2 ;
    END
  END qrq[225]
  PIN qrq[226]
    DIRECTION INPUT ;
    USE SIGNAL ;
    PORT
      LAYER M5 ;
        RECT  39.024 43.008 39.048 43.2 ;
    END
  END qrq[226]
  PIN qrq[227]
    DIRECTION INPUT ;
    USE SIGNAL ;
    PORT
      LAYER M5 ;
        RECT  39.12 43.008 39.144 43.2 ;
    END
  END qrq[227]
  PIN qrq[228]
    DIRECTION INPUT ;
    USE SIGNAL ;
    PORT
      LAYER M5 ;
        RECT  39.216 43.008 39.24 43.2 ;
    END
  END qrq[228]
  PIN qrq[229]
    DIRECTION INPUT ;
    USE SIGNAL ;
    PORT
      LAYER M5 ;
        RECT  39.312 43.008 39.336 43.2 ;
    END
  END qrq[229]
  PIN qrq[22]
    DIRECTION INPUT ;
    USE SIGNAL ;
    PORT
      LAYER M5 ;
        RECT  19.44 43.008 19.464 43.2 ;
    END
  END qrq[22]
  PIN qrq[230]
    DIRECTION INPUT ;
    USE SIGNAL ;
    PORT
      LAYER M5 ;
        RECT  39.408 43.008 39.432 43.2 ;
    END
  END qrq[230]
  PIN qrq[231]
    DIRECTION INPUT ;
    USE SIGNAL ;
    PORT
      LAYER M5 ;
        RECT  39.504 43.008 39.528 43.2 ;
    END
  END qrq[231]
  PIN qrq[232]
    DIRECTION INPUT ;
    USE SIGNAL ;
    PORT
      LAYER M5 ;
        RECT  39.6 43.008 39.624 43.2 ;
    END
  END qrq[232]
  PIN qrq[233]
    DIRECTION INPUT ;
    USE SIGNAL ;
    PORT
      LAYER M5 ;
        RECT  39.696 43.008 39.72 43.2 ;
    END
  END qrq[233]
  PIN qrq[234]
    DIRECTION INPUT ;
    USE SIGNAL ;
    PORT
      LAYER M5 ;
        RECT  39.792 43.008 39.816 43.2 ;
    END
  END qrq[234]
  PIN qrq[235]
    DIRECTION INPUT ;
    USE SIGNAL ;
    PORT
      LAYER M5 ;
        RECT  39.888 43.008 39.912 43.2 ;
    END
  END qrq[235]
  PIN qrq[236]
    DIRECTION INPUT ;
    USE SIGNAL ;
    PORT
      LAYER M5 ;
        RECT  39.984 43.008 40.008 43.2 ;
    END
  END qrq[236]
  PIN qrq[237]
    DIRECTION INPUT ;
    USE SIGNAL ;
    PORT
      LAYER M5 ;
        RECT  40.08 43.008 40.104 43.2 ;
    END
  END qrq[237]
  PIN qrq[238]
    DIRECTION INPUT ;
    USE SIGNAL ;
    PORT
      LAYER M5 ;
        RECT  40.176 43.008 40.2 43.2 ;
    END
  END qrq[238]
  PIN qrq[239]
    DIRECTION INPUT ;
    USE SIGNAL ;
    PORT
      LAYER M5 ;
        RECT  40.272 43.008 40.296 43.2 ;
    END
  END qrq[239]
  PIN qrq[23]
    DIRECTION INPUT ;
    USE SIGNAL ;
    PORT
      LAYER M5 ;
        RECT  19.536 43.008 19.56 43.2 ;
    END
  END qrq[23]
  PIN qrq[240]
    DIRECTION INPUT ;
    USE SIGNAL ;
    PORT
      LAYER M5 ;
        RECT  40.368 43.008 40.392 43.2 ;
    END
  END qrq[240]
  PIN qrq[241]
    DIRECTION INPUT ;
    USE SIGNAL ;
    PORT
      LAYER M5 ;
        RECT  40.464 43.008 40.488 43.2 ;
    END
  END qrq[241]
  PIN qrq[242]
    DIRECTION INPUT ;
    USE SIGNAL ;
    PORT
      LAYER M5 ;
        RECT  40.56 43.008 40.584 43.2 ;
    END
  END qrq[242]
  PIN qrq[243]
    DIRECTION INPUT ;
    USE SIGNAL ;
    PORT
      LAYER M5 ;
        RECT  40.656 43.008 40.68 43.2 ;
    END
  END qrq[243]
  PIN qrq[244]
    DIRECTION INPUT ;
    USE SIGNAL ;
    PORT
      LAYER M5 ;
        RECT  40.752 43.008 40.776 43.2 ;
    END
  END qrq[244]
  PIN qrq[245]
    DIRECTION INPUT ;
    USE SIGNAL ;
    PORT
      LAYER M5 ;
        RECT  40.848 43.008 40.872 43.2 ;
    END
  END qrq[245]
  PIN qrq[246]
    DIRECTION INPUT ;
    USE SIGNAL ;
    PORT
      LAYER M5 ;
        RECT  40.944 43.008 40.968 43.2 ;
    END
  END qrq[246]
  PIN qrq[247]
    DIRECTION INPUT ;
    USE SIGNAL ;
    PORT
      LAYER M5 ;
        RECT  41.04 43.008 41.064 43.2 ;
    END
  END qrq[247]
  PIN qrq[248]
    DIRECTION INPUT ;
    USE SIGNAL ;
    PORT
      LAYER M5 ;
        RECT  41.136 43.008 41.16 43.2 ;
    END
  END qrq[248]
  PIN qrq[249]
    DIRECTION INPUT ;
    USE SIGNAL ;
    PORT
      LAYER M5 ;
        RECT  41.232 43.008 41.256 43.2 ;
    END
  END qrq[249]
  PIN qrq[24]
    DIRECTION INPUT ;
    USE SIGNAL ;
    PORT
      LAYER M5 ;
        RECT  19.632 43.008 19.656 43.2 ;
    END
  END qrq[24]
  PIN qrq[250]
    DIRECTION INPUT ;
    USE SIGNAL ;
    PORT
      LAYER M5 ;
        RECT  41.328 43.008 41.352 43.2 ;
    END
  END qrq[250]
  PIN qrq[251]
    DIRECTION INPUT ;
    USE SIGNAL ;
    PORT
      LAYER M5 ;
        RECT  41.424 43.008 41.448 43.2 ;
    END
  END qrq[251]
  PIN qrq[252]
    DIRECTION INPUT ;
    USE SIGNAL ;
    PORT
      LAYER M5 ;
        RECT  41.52 43.008 41.544 43.2 ;
    END
  END qrq[252]
  PIN qrq[253]
    DIRECTION INPUT ;
    USE SIGNAL ;
    PORT
      LAYER M5 ;
        RECT  41.616 43.008 41.64 43.2 ;
    END
  END qrq[253]
  PIN qrq[254]
    DIRECTION INPUT ;
    USE SIGNAL ;
    PORT
      LAYER M5 ;
        RECT  41.712 43.008 41.736 43.2 ;
    END
  END qrq[254]
  PIN qrq[255]
    DIRECTION INPUT ;
    USE SIGNAL ;
    PORT
      LAYER M5 ;
        RECT  41.808 43.008 41.832 43.2 ;
    END
  END qrq[255]
  PIN qrq[256]
    DIRECTION INPUT ;
    USE SIGNAL ;
    PORT
      LAYER M5 ;
        RECT  41.904 43.008 41.928 43.2 ;
    END
  END qrq[256]
  PIN qrq[257]
    DIRECTION INPUT ;
    USE SIGNAL ;
    PORT
      LAYER M5 ;
        RECT  42 43.008 42.024 43.2 ;
    END
  END qrq[257]
  PIN qrq[258]
    DIRECTION INPUT ;
    USE SIGNAL ;
    PORT
      LAYER M5 ;
        RECT  42.096 43.008 42.12 43.2 ;
    END
  END qrq[258]
  PIN qrq[259]
    DIRECTION INPUT ;
    USE SIGNAL ;
    PORT
      LAYER M5 ;
        RECT  42.192 43.008 42.216 43.2 ;
    END
  END qrq[259]
  PIN qrq[25]
    DIRECTION INPUT ;
    USE SIGNAL ;
    PORT
      LAYER M5 ;
        RECT  19.728 43.008 19.752 43.2 ;
    END
  END qrq[25]
  PIN qrq[260]
    DIRECTION INPUT ;
    USE SIGNAL ;
    PORT
      LAYER M5 ;
        RECT  42.288 43.008 42.312 43.2 ;
    END
  END qrq[260]
  PIN qrq[261]
    DIRECTION INPUT ;
    USE SIGNAL ;
    PORT
      LAYER M5 ;
        RECT  42.384 43.008 42.408 43.2 ;
    END
  END qrq[261]
  PIN qrq[262]
    DIRECTION INPUT ;
    USE SIGNAL ;
    PORT
      LAYER M5 ;
        RECT  42.48 43.008 42.504 43.2 ;
    END
  END qrq[262]
  PIN qrq[263]
    DIRECTION INPUT ;
    USE SIGNAL ;
    PORT
      LAYER M5 ;
        RECT  42.576 43.008 42.6 43.2 ;
    END
  END qrq[263]
  PIN qrq[264]
    DIRECTION INPUT ;
    USE SIGNAL ;
    PORT
      LAYER M5 ;
        RECT  42.672 43.008 42.696 43.2 ;
    END
  END qrq[264]
  PIN qrq[265]
    DIRECTION INPUT ;
    USE SIGNAL ;
    PORT
      LAYER M5 ;
        RECT  42.768 43.008 42.792 43.2 ;
    END
  END qrq[265]
  PIN qrq[266]
    DIRECTION INPUT ;
    USE SIGNAL ;
    PORT
      LAYER M5 ;
        RECT  42.864 43.008 42.888 43.2 ;
    END
  END qrq[266]
  PIN qrq[267]
    DIRECTION INPUT ;
    USE SIGNAL ;
    PORT
      LAYER M5 ;
        RECT  42.96 43.008 42.984 43.2 ;
    END
  END qrq[267]
  PIN qrq[268]
    DIRECTION INPUT ;
    USE SIGNAL ;
    PORT
      LAYER M5 ;
        RECT  43.056 43.008 43.08 43.2 ;
    END
  END qrq[268]
  PIN qrq[269]
    DIRECTION INPUT ;
    USE SIGNAL ;
    PORT
      LAYER M5 ;
        RECT  43.152 43.008 43.176 43.2 ;
    END
  END qrq[269]
  PIN qrq[26]
    DIRECTION INPUT ;
    USE SIGNAL ;
    PORT
      LAYER M5 ;
        RECT  19.824 43.008 19.848 43.2 ;
    END
  END qrq[26]
  PIN qrq[270]
    DIRECTION INPUT ;
    USE SIGNAL ;
    PORT
      LAYER M5 ;
        RECT  43.248 43.008 43.272 43.2 ;
    END
  END qrq[270]
  PIN qrq[271]
    DIRECTION INPUT ;
    USE SIGNAL ;
    PORT
      LAYER M5 ;
        RECT  43.344 43.008 43.368 43.2 ;
    END
  END qrq[271]
  PIN qrq[272]
    DIRECTION INPUT ;
    USE SIGNAL ;
    PORT
      LAYER M5 ;
        RECT  43.44 43.008 43.464 43.2 ;
    END
  END qrq[272]
  PIN qrq[273]
    DIRECTION INPUT ;
    USE SIGNAL ;
    PORT
      LAYER M5 ;
        RECT  43.536 43.008 43.56 43.2 ;
    END
  END qrq[273]
  PIN qrq[274]
    DIRECTION INPUT ;
    USE SIGNAL ;
    PORT
      LAYER M5 ;
        RECT  43.632 43.008 43.656 43.2 ;
    END
  END qrq[274]
  PIN qrq[275]
    DIRECTION INPUT ;
    USE SIGNAL ;
    PORT
      LAYER M5 ;
        RECT  43.728 43.008 43.752 43.2 ;
    END
  END qrq[275]
  PIN qrq[276]
    DIRECTION INPUT ;
    USE SIGNAL ;
    PORT
      LAYER M5 ;
        RECT  43.824 43.008 43.848 43.2 ;
    END
  END qrq[276]
  PIN qrq[277]
    DIRECTION INPUT ;
    USE SIGNAL ;
    PORT
      LAYER M5 ;
        RECT  43.92 43.008 43.944 43.2 ;
    END
  END qrq[277]
  PIN qrq[278]
    DIRECTION INPUT ;
    USE SIGNAL ;
    PORT
      LAYER M5 ;
        RECT  44.016 43.008 44.04 43.2 ;
    END
  END qrq[278]
  PIN qrq[279]
    DIRECTION INPUT ;
    USE SIGNAL ;
    PORT
      LAYER M5 ;
        RECT  44.112 43.008 44.136 43.2 ;
    END
  END qrq[279]
  PIN qrq[27]
    DIRECTION INPUT ;
    USE SIGNAL ;
    PORT
      LAYER M5 ;
        RECT  19.92 43.008 19.944 43.2 ;
    END
  END qrq[27]
  PIN qrq[280]
    DIRECTION INPUT ;
    USE SIGNAL ;
    PORT
      LAYER M5 ;
        RECT  44.208 43.008 44.232 43.2 ;
    END
  END qrq[280]
  PIN qrq[281]
    DIRECTION INPUT ;
    USE SIGNAL ;
    PORT
      LAYER M5 ;
        RECT  44.304 43.008 44.328 43.2 ;
    END
  END qrq[281]
  PIN qrq[282]
    DIRECTION INPUT ;
    USE SIGNAL ;
    PORT
      LAYER M5 ;
        RECT  44.4 43.008 44.424 43.2 ;
    END
  END qrq[282]
  PIN qrq[283]
    DIRECTION INPUT ;
    USE SIGNAL ;
    PORT
      LAYER M5 ;
        RECT  44.496 43.008 44.52 43.2 ;
    END
  END qrq[283]
  PIN qrq[284]
    DIRECTION INPUT ;
    USE SIGNAL ;
    PORT
      LAYER M5 ;
        RECT  44.592 43.008 44.616 43.2 ;
    END
  END qrq[284]
  PIN qrq[285]
    DIRECTION INPUT ;
    USE SIGNAL ;
    PORT
      LAYER M5 ;
        RECT  44.688 43.008 44.712 43.2 ;
    END
  END qrq[285]
  PIN qrq[286]
    DIRECTION INPUT ;
    USE SIGNAL ;
    PORT
      LAYER M5 ;
        RECT  44.784 43.008 44.808 43.2 ;
    END
  END qrq[286]
  PIN qrq[287]
    DIRECTION INPUT ;
    USE SIGNAL ;
    PORT
      LAYER M5 ;
        RECT  44.88 43.008 44.904 43.2 ;
    END
  END qrq[287]
  PIN qrq[288]
    DIRECTION INPUT ;
    USE SIGNAL ;
    PORT
      LAYER M5 ;
        RECT  44.976 43.008 45 43.2 ;
    END
  END qrq[288]
  PIN qrq[289]
    DIRECTION INPUT ;
    USE SIGNAL ;
    PORT
      LAYER M5 ;
        RECT  45.072 43.008 45.096 43.2 ;
    END
  END qrq[289]
  PIN qrq[28]
    DIRECTION INPUT ;
    USE SIGNAL ;
    PORT
      LAYER M5 ;
        RECT  20.016 43.008 20.04 43.2 ;
    END
  END qrq[28]
  PIN qrq[290]
    DIRECTION INPUT ;
    USE SIGNAL ;
    PORT
      LAYER M5 ;
        RECT  45.168 43.008 45.192 43.2 ;
    END
  END qrq[290]
  PIN qrq[291]
    DIRECTION INPUT ;
    USE SIGNAL ;
    PORT
      LAYER M5 ;
        RECT  45.264 43.008 45.288 43.2 ;
    END
  END qrq[291]
  PIN qrq[292]
    DIRECTION INPUT ;
    USE SIGNAL ;
    PORT
      LAYER M5 ;
        RECT  45.36 43.008 45.384 43.2 ;
    END
  END qrq[292]
  PIN qrq[293]
    DIRECTION INPUT ;
    USE SIGNAL ;
    PORT
      LAYER M5 ;
        RECT  45.456 43.008 45.48 43.2 ;
    END
  END qrq[293]
  PIN qrq[294]
    DIRECTION INPUT ;
    USE SIGNAL ;
    PORT
      LAYER M5 ;
        RECT  45.552 43.008 45.576 43.2 ;
    END
  END qrq[294]
  PIN qrq[295]
    DIRECTION INPUT ;
    USE SIGNAL ;
    PORT
      LAYER M5 ;
        RECT  45.648 43.008 45.672 43.2 ;
    END
  END qrq[295]
  PIN qrq[296]
    DIRECTION INPUT ;
    USE SIGNAL ;
    PORT
      LAYER M5 ;
        RECT  45.744 43.008 45.768 43.2 ;
    END
  END qrq[296]
  PIN qrq[297]
    DIRECTION INPUT ;
    USE SIGNAL ;
    PORT
      LAYER M5 ;
        RECT  45.84 43.008 45.864 43.2 ;
    END
  END qrq[297]
  PIN qrq[298]
    DIRECTION INPUT ;
    USE SIGNAL ;
    PORT
      LAYER M5 ;
        RECT  45.936 43.008 45.96 43.2 ;
    END
  END qrq[298]
  PIN qrq[299]
    DIRECTION INPUT ;
    USE SIGNAL ;
    PORT
      LAYER M5 ;
        RECT  46.032 43.008 46.056 43.2 ;
    END
  END qrq[299]
  PIN qrq[29]
    DIRECTION INPUT ;
    USE SIGNAL ;
    PORT
      LAYER M5 ;
        RECT  20.112 43.008 20.136 43.2 ;
    END
  END qrq[29]
  PIN qrq[2]
    DIRECTION INPUT ;
    USE SIGNAL ;
    PORT
      LAYER M5 ;
        RECT  17.52 43.008 17.544 43.2 ;
    END
  END qrq[2]
  PIN qrq[300]
    DIRECTION INPUT ;
    USE SIGNAL ;
    PORT
      LAYER M5 ;
        RECT  46.128 43.008 46.152 43.2 ;
    END
  END qrq[300]
  PIN qrq[301]
    DIRECTION INPUT ;
    USE SIGNAL ;
    PORT
      LAYER M5 ;
        RECT  46.224 43.008 46.248 43.2 ;
    END
  END qrq[301]
  PIN qrq[302]
    DIRECTION INPUT ;
    USE SIGNAL ;
    PORT
      LAYER M5 ;
        RECT  46.32 43.008 46.344 43.2 ;
    END
  END qrq[302]
  PIN qrq[303]
    DIRECTION INPUT ;
    USE SIGNAL ;
    PORT
      LAYER M5 ;
        RECT  46.416 43.008 46.44 43.2 ;
    END
  END qrq[303]
  PIN qrq[304]
    DIRECTION INPUT ;
    USE SIGNAL ;
    PORT
      LAYER M5 ;
        RECT  46.512 43.008 46.536 43.2 ;
    END
  END qrq[304]
  PIN qrq[305]
    DIRECTION INPUT ;
    USE SIGNAL ;
    PORT
      LAYER M5 ;
        RECT  46.608 43.008 46.632 43.2 ;
    END
  END qrq[305]
  PIN qrq[306]
    DIRECTION INPUT ;
    USE SIGNAL ;
    PORT
      LAYER M5 ;
        RECT  46.704 43.008 46.728 43.2 ;
    END
  END qrq[306]
  PIN qrq[307]
    DIRECTION INPUT ;
    USE SIGNAL ;
    PORT
      LAYER M5 ;
        RECT  46.8 43.008 46.824 43.2 ;
    END
  END qrq[307]
  PIN qrq[308]
    DIRECTION INPUT ;
    USE SIGNAL ;
    PORT
      LAYER M5 ;
        RECT  46.896 43.008 46.92 43.2 ;
    END
  END qrq[308]
  PIN qrq[309]
    DIRECTION INPUT ;
    USE SIGNAL ;
    PORT
      LAYER M5 ;
        RECT  46.992 43.008 47.016 43.2 ;
    END
  END qrq[309]
  PIN qrq[30]
    DIRECTION INPUT ;
    USE SIGNAL ;
    PORT
      LAYER M5 ;
        RECT  20.208 43.008 20.232 43.2 ;
    END
  END qrq[30]
  PIN qrq[310]
    DIRECTION INPUT ;
    USE SIGNAL ;
    PORT
      LAYER M5 ;
        RECT  47.088 43.008 47.112 43.2 ;
    END
  END qrq[310]
  PIN qrq[311]
    DIRECTION INPUT ;
    USE SIGNAL ;
    PORT
      LAYER M5 ;
        RECT  47.184 43.008 47.208 43.2 ;
    END
  END qrq[311]
  PIN qrq[312]
    DIRECTION INPUT ;
    USE SIGNAL ;
    PORT
      LAYER M5 ;
        RECT  47.28 43.008 47.304 43.2 ;
    END
  END qrq[312]
  PIN qrq[313]
    DIRECTION INPUT ;
    USE SIGNAL ;
    PORT
      LAYER M5 ;
        RECT  47.376 43.008 47.4 43.2 ;
    END
  END qrq[313]
  PIN qrq[314]
    DIRECTION INPUT ;
    USE SIGNAL ;
    PORT
      LAYER M5 ;
        RECT  47.472 43.008 47.496 43.2 ;
    END
  END qrq[314]
  PIN qrq[315]
    DIRECTION INPUT ;
    USE SIGNAL ;
    PORT
      LAYER M5 ;
        RECT  47.568 43.008 47.592 43.2 ;
    END
  END qrq[315]
  PIN qrq[316]
    DIRECTION INPUT ;
    USE SIGNAL ;
    PORT
      LAYER M5 ;
        RECT  47.664 43.008 47.688 43.2 ;
    END
  END qrq[316]
  PIN qrq[317]
    DIRECTION INPUT ;
    USE SIGNAL ;
    PORT
      LAYER M5 ;
        RECT  47.76 43.008 47.784 43.2 ;
    END
  END qrq[317]
  PIN qrq[318]
    DIRECTION INPUT ;
    USE SIGNAL ;
    PORT
      LAYER M5 ;
        RECT  47.856 43.008 47.88 43.2 ;
    END
  END qrq[318]
  PIN qrq[319]
    DIRECTION INPUT ;
    USE SIGNAL ;
    PORT
      LAYER M5 ;
        RECT  47.952 43.008 47.976 43.2 ;
    END
  END qrq[319]
  PIN qrq[31]
    DIRECTION INPUT ;
    USE SIGNAL ;
    PORT
      LAYER M5 ;
        RECT  20.304 43.008 20.328 43.2 ;
    END
  END qrq[31]
  PIN qrq[320]
    DIRECTION INPUT ;
    USE SIGNAL ;
    PORT
      LAYER M5 ;
        RECT  48.048 43.008 48.072 43.2 ;
    END
  END qrq[320]
  PIN qrq[321]
    DIRECTION INPUT ;
    USE SIGNAL ;
    PORT
      LAYER M5 ;
        RECT  48.144 43.008 48.168 43.2 ;
    END
  END qrq[321]
  PIN qrq[322]
    DIRECTION INPUT ;
    USE SIGNAL ;
    PORT
      LAYER M5 ;
        RECT  48.24 43.008 48.264 43.2 ;
    END
  END qrq[322]
  PIN qrq[323]
    DIRECTION INPUT ;
    USE SIGNAL ;
    PORT
      LAYER M5 ;
        RECT  48.336 43.008 48.36 43.2 ;
    END
  END qrq[323]
  PIN qrq[324]
    DIRECTION INPUT ;
    USE SIGNAL ;
    PORT
      LAYER M5 ;
        RECT  48.432 43.008 48.456 43.2 ;
    END
  END qrq[324]
  PIN qrq[325]
    DIRECTION INPUT ;
    USE SIGNAL ;
    PORT
      LAYER M5 ;
        RECT  48.528 43.008 48.552 43.2 ;
    END
  END qrq[325]
  PIN qrq[326]
    DIRECTION INPUT ;
    USE SIGNAL ;
    PORT
      LAYER M5 ;
        RECT  48.624 43.008 48.648 43.2 ;
    END
  END qrq[326]
  PIN qrq[327]
    DIRECTION INPUT ;
    USE SIGNAL ;
    PORT
      LAYER M5 ;
        RECT  48.72 43.008 48.744 43.2 ;
    END
  END qrq[327]
  PIN qrq[328]
    DIRECTION INPUT ;
    USE SIGNAL ;
    PORT
      LAYER M5 ;
        RECT  48.816 43.008 48.84 43.2 ;
    END
  END qrq[328]
  PIN qrq[329]
    DIRECTION INPUT ;
    USE SIGNAL ;
    PORT
      LAYER M5 ;
        RECT  48.912 43.008 48.936 43.2 ;
    END
  END qrq[329]
  PIN qrq[32]
    DIRECTION INPUT ;
    USE SIGNAL ;
    PORT
      LAYER M5 ;
        RECT  20.4 43.008 20.424 43.2 ;
    END
  END qrq[32]
  PIN qrq[330]
    DIRECTION INPUT ;
    USE SIGNAL ;
    PORT
      LAYER M5 ;
        RECT  49.008 43.008 49.032 43.2 ;
    END
  END qrq[330]
  PIN qrq[331]
    DIRECTION INPUT ;
    USE SIGNAL ;
    PORT
      LAYER M5 ;
        RECT  49.104 43.008 49.128 43.2 ;
    END
  END qrq[331]
  PIN qrq[332]
    DIRECTION INPUT ;
    USE SIGNAL ;
    PORT
      LAYER M5 ;
        RECT  49.2 43.008 49.224 43.2 ;
    END
  END qrq[332]
  PIN qrq[333]
    DIRECTION INPUT ;
    USE SIGNAL ;
    PORT
      LAYER M5 ;
        RECT  49.296 43.008 49.32 43.2 ;
    END
  END qrq[333]
  PIN qrq[334]
    DIRECTION INPUT ;
    USE SIGNAL ;
    PORT
      LAYER M5 ;
        RECT  49.392 43.008 49.416 43.2 ;
    END
  END qrq[334]
  PIN qrq[335]
    DIRECTION INPUT ;
    USE SIGNAL ;
    PORT
      LAYER M5 ;
        RECT  49.488 43.008 49.512 43.2 ;
    END
  END qrq[335]
  PIN qrq[336]
    DIRECTION INPUT ;
    USE SIGNAL ;
    PORT
      LAYER M5 ;
        RECT  49.584 43.008 49.608 43.2 ;
    END
  END qrq[336]
  PIN qrq[337]
    DIRECTION INPUT ;
    USE SIGNAL ;
    PORT
      LAYER M5 ;
        RECT  49.68 43.008 49.704 43.2 ;
    END
  END qrq[337]
  PIN qrq[338]
    DIRECTION INPUT ;
    USE SIGNAL ;
    PORT
      LAYER M5 ;
        RECT  49.776 43.008 49.8 43.2 ;
    END
  END qrq[338]
  PIN qrq[339]
    DIRECTION INPUT ;
    USE SIGNAL ;
    PORT
      LAYER M5 ;
        RECT  49.872 43.008 49.896 43.2 ;
    END
  END qrq[339]
  PIN qrq[33]
    DIRECTION INPUT ;
    USE SIGNAL ;
    PORT
      LAYER M5 ;
        RECT  20.496 43.008 20.52 43.2 ;
    END
  END qrq[33]
  PIN qrq[340]
    DIRECTION INPUT ;
    USE SIGNAL ;
    PORT
      LAYER M5 ;
        RECT  49.968 43.008 49.992 43.2 ;
    END
  END qrq[340]
  PIN qrq[34]
    DIRECTION INPUT ;
    USE SIGNAL ;
    PORT
      LAYER M5 ;
        RECT  20.592 43.008 20.616 43.2 ;
    END
  END qrq[34]
  PIN qrq[35]
    DIRECTION INPUT ;
    USE SIGNAL ;
    PORT
      LAYER M5 ;
        RECT  20.688 43.008 20.712 43.2 ;
    END
  END qrq[35]
  PIN qrq[36]
    DIRECTION INPUT ;
    USE SIGNAL ;
    PORT
      LAYER M5 ;
        RECT  20.784 43.008 20.808 43.2 ;
    END
  END qrq[36]
  PIN qrq[37]
    DIRECTION INPUT ;
    USE SIGNAL ;
    PORT
      LAYER M5 ;
        RECT  20.88 43.008 20.904 43.2 ;
    END
  END qrq[37]
  PIN qrq[38]
    DIRECTION INPUT ;
    USE SIGNAL ;
    PORT
      LAYER M5 ;
        RECT  20.976 43.008 21 43.2 ;
    END
  END qrq[38]
  PIN qrq[39]
    DIRECTION INPUT ;
    USE SIGNAL ;
    PORT
      LAYER M5 ;
        RECT  21.072 43.008 21.096 43.2 ;
    END
  END qrq[39]
  PIN qrq[3]
    DIRECTION INPUT ;
    USE SIGNAL ;
    PORT
      LAYER M5 ;
        RECT  17.616 43.008 17.64 43.2 ;
    END
  END qrq[3]
  PIN qrq[40]
    DIRECTION INPUT ;
    USE SIGNAL ;
    PORT
      LAYER M5 ;
        RECT  21.168 43.008 21.192 43.2 ;
    END
  END qrq[40]
  PIN qrq[41]
    DIRECTION INPUT ;
    USE SIGNAL ;
    PORT
      LAYER M5 ;
        RECT  21.264 43.008 21.288 43.2 ;
    END
  END qrq[41]
  PIN qrq[42]
    DIRECTION INPUT ;
    USE SIGNAL ;
    PORT
      LAYER M5 ;
        RECT  21.36 43.008 21.384 43.2 ;
    END
  END qrq[42]
  PIN qrq[43]
    DIRECTION INPUT ;
    USE SIGNAL ;
    PORT
      LAYER M5 ;
        RECT  21.456 43.008 21.48 43.2 ;
    END
  END qrq[43]
  PIN qrq[44]
    DIRECTION INPUT ;
    USE SIGNAL ;
    PORT
      LAYER M5 ;
        RECT  21.552 43.008 21.576 43.2 ;
    END
  END qrq[44]
  PIN qrq[45]
    DIRECTION INPUT ;
    USE SIGNAL ;
    PORT
      LAYER M5 ;
        RECT  21.648 43.008 21.672 43.2 ;
    END
  END qrq[45]
  PIN qrq[46]
    DIRECTION INPUT ;
    USE SIGNAL ;
    PORT
      LAYER M5 ;
        RECT  21.744 43.008 21.768 43.2 ;
    END
  END qrq[46]
  PIN qrq[47]
    DIRECTION INPUT ;
    USE SIGNAL ;
    PORT
      LAYER M5 ;
        RECT  21.84 43.008 21.864 43.2 ;
    END
  END qrq[47]
  PIN qrq[48]
    DIRECTION INPUT ;
    USE SIGNAL ;
    PORT
      LAYER M5 ;
        RECT  21.936 43.008 21.96 43.2 ;
    END
  END qrq[48]
  PIN qrq[49]
    DIRECTION INPUT ;
    USE SIGNAL ;
    PORT
      LAYER M5 ;
        RECT  22.032 43.008 22.056 43.2 ;
    END
  END qrq[49]
  PIN qrq[4]
    DIRECTION INPUT ;
    USE SIGNAL ;
    PORT
      LAYER M5 ;
        RECT  17.712 43.008 17.736 43.2 ;
    END
  END qrq[4]
  PIN qrq[50]
    DIRECTION INPUT ;
    USE SIGNAL ;
    PORT
      LAYER M5 ;
        RECT  22.128 43.008 22.152 43.2 ;
    END
  END qrq[50]
  PIN qrq[51]
    DIRECTION INPUT ;
    USE SIGNAL ;
    PORT
      LAYER M5 ;
        RECT  22.224 43.008 22.248 43.2 ;
    END
  END qrq[51]
  PIN qrq[52]
    DIRECTION INPUT ;
    USE SIGNAL ;
    PORT
      LAYER M5 ;
        RECT  22.32 43.008 22.344 43.2 ;
    END
  END qrq[52]
  PIN qrq[53]
    DIRECTION INPUT ;
    USE SIGNAL ;
    PORT
      LAYER M5 ;
        RECT  22.416 43.008 22.44 43.2 ;
    END
  END qrq[53]
  PIN qrq[54]
    DIRECTION INPUT ;
    USE SIGNAL ;
    PORT
      LAYER M5 ;
        RECT  22.512 43.008 22.536 43.2 ;
    END
  END qrq[54]
  PIN qrq[55]
    DIRECTION INPUT ;
    USE SIGNAL ;
    PORT
      LAYER M5 ;
        RECT  22.608 43.008 22.632 43.2 ;
    END
  END qrq[55]
  PIN qrq[56]
    DIRECTION INPUT ;
    USE SIGNAL ;
    PORT
      LAYER M5 ;
        RECT  22.704 43.008 22.728 43.2 ;
    END
  END qrq[56]
  PIN qrq[57]
    DIRECTION INPUT ;
    USE SIGNAL ;
    PORT
      LAYER M5 ;
        RECT  22.8 43.008 22.824 43.2 ;
    END
  END qrq[57]
  PIN qrq[58]
    DIRECTION INPUT ;
    USE SIGNAL ;
    PORT
      LAYER M5 ;
        RECT  22.896 43.008 22.92 43.2 ;
    END
  END qrq[58]
  PIN qrq[59]
    DIRECTION INPUT ;
    USE SIGNAL ;
    PORT
      LAYER M5 ;
        RECT  22.992 43.008 23.016 43.2 ;
    END
  END qrq[59]
  PIN qrq[5]
    DIRECTION INPUT ;
    USE SIGNAL ;
    PORT
      LAYER M5 ;
        RECT  17.808 43.008 17.832 43.2 ;
    END
  END qrq[5]
  PIN qrq[60]
    DIRECTION INPUT ;
    USE SIGNAL ;
    PORT
      LAYER M5 ;
        RECT  23.088 43.008 23.112 43.2 ;
    END
  END qrq[60]
  PIN qrq[61]
    DIRECTION INPUT ;
    USE SIGNAL ;
    PORT
      LAYER M5 ;
        RECT  23.184 43.008 23.208 43.2 ;
    END
  END qrq[61]
  PIN qrq[62]
    DIRECTION INPUT ;
    USE SIGNAL ;
    PORT
      LAYER M5 ;
        RECT  23.28 43.008 23.304 43.2 ;
    END
  END qrq[62]
  PIN qrq[63]
    DIRECTION INPUT ;
    USE SIGNAL ;
    PORT
      LAYER M5 ;
        RECT  23.376 43.008 23.4 43.2 ;
    END
  END qrq[63]
  PIN qrq[64]
    DIRECTION INPUT ;
    USE SIGNAL ;
    PORT
      LAYER M5 ;
        RECT  23.472 43.008 23.496 43.2 ;
    END
  END qrq[64]
  PIN qrq[65]
    DIRECTION INPUT ;
    USE SIGNAL ;
    PORT
      LAYER M5 ;
        RECT  23.568 43.008 23.592 43.2 ;
    END
  END qrq[65]
  PIN qrq[66]
    DIRECTION INPUT ;
    USE SIGNAL ;
    PORT
      LAYER M5 ;
        RECT  23.664 43.008 23.688 43.2 ;
    END
  END qrq[66]
  PIN qrq[67]
    DIRECTION INPUT ;
    USE SIGNAL ;
    PORT
      LAYER M5 ;
        RECT  23.76 43.008 23.784 43.2 ;
    END
  END qrq[67]
  PIN qrq[68]
    DIRECTION INPUT ;
    USE SIGNAL ;
    PORT
      LAYER M5 ;
        RECT  23.856 43.008 23.88 43.2 ;
    END
  END qrq[68]
  PIN qrq[69]
    DIRECTION INPUT ;
    USE SIGNAL ;
    PORT
      LAYER M5 ;
        RECT  23.952 43.008 23.976 43.2 ;
    END
  END qrq[69]
  PIN qrq[6]
    DIRECTION INPUT ;
    USE SIGNAL ;
    PORT
      LAYER M5 ;
        RECT  17.904 43.008 17.928 43.2 ;
    END
  END qrq[6]
  PIN qrq[70]
    DIRECTION INPUT ;
    USE SIGNAL ;
    PORT
      LAYER M5 ;
        RECT  24.048 43.008 24.072 43.2 ;
    END
  END qrq[70]
  PIN qrq[71]
    DIRECTION INPUT ;
    USE SIGNAL ;
    PORT
      LAYER M5 ;
        RECT  24.144 43.008 24.168 43.2 ;
    END
  END qrq[71]
  PIN qrq[72]
    DIRECTION INPUT ;
    USE SIGNAL ;
    PORT
      LAYER M5 ;
        RECT  24.24 43.008 24.264 43.2 ;
    END
  END qrq[72]
  PIN qrq[73]
    DIRECTION INPUT ;
    USE SIGNAL ;
    PORT
      LAYER M5 ;
        RECT  24.336 43.008 24.36 43.2 ;
    END
  END qrq[73]
  PIN qrq[74]
    DIRECTION INPUT ;
    USE SIGNAL ;
    PORT
      LAYER M5 ;
        RECT  24.432 43.008 24.456 43.2 ;
    END
  END qrq[74]
  PIN qrq[75]
    DIRECTION INPUT ;
    USE SIGNAL ;
    PORT
      LAYER M5 ;
        RECT  24.528 43.008 24.552 43.2 ;
    END
  END qrq[75]
  PIN qrq[76]
    DIRECTION INPUT ;
    USE SIGNAL ;
    PORT
      LAYER M5 ;
        RECT  24.624 43.008 24.648 43.2 ;
    END
  END qrq[76]
  PIN qrq[77]
    DIRECTION INPUT ;
    USE SIGNAL ;
    PORT
      LAYER M5 ;
        RECT  24.72 43.008 24.744 43.2 ;
    END
  END qrq[77]
  PIN qrq[78]
    DIRECTION INPUT ;
    USE SIGNAL ;
    PORT
      LAYER M5 ;
        RECT  24.816 43.008 24.84 43.2 ;
    END
  END qrq[78]
  PIN qrq[79]
    DIRECTION INPUT ;
    USE SIGNAL ;
    PORT
      LAYER M5 ;
        RECT  24.912 43.008 24.936 43.2 ;
    END
  END qrq[79]
  PIN qrq[7]
    DIRECTION INPUT ;
    USE SIGNAL ;
    PORT
      LAYER M5 ;
        RECT  18 43.008 18.024 43.2 ;
    END
  END qrq[7]
  PIN qrq[80]
    DIRECTION INPUT ;
    USE SIGNAL ;
    PORT
      LAYER M5 ;
        RECT  25.008 43.008 25.032 43.2 ;
    END
  END qrq[80]
  PIN qrq[81]
    DIRECTION INPUT ;
    USE SIGNAL ;
    PORT
      LAYER M5 ;
        RECT  25.104 43.008 25.128 43.2 ;
    END
  END qrq[81]
  PIN qrq[82]
    DIRECTION INPUT ;
    USE SIGNAL ;
    PORT
      LAYER M5 ;
        RECT  25.2 43.008 25.224 43.2 ;
    END
  END qrq[82]
  PIN qrq[83]
    DIRECTION INPUT ;
    USE SIGNAL ;
    PORT
      LAYER M5 ;
        RECT  25.296 43.008 25.32 43.2 ;
    END
  END qrq[83]
  PIN qrq[84]
    DIRECTION INPUT ;
    USE SIGNAL ;
    PORT
      LAYER M5 ;
        RECT  25.392 43.008 25.416 43.2 ;
    END
  END qrq[84]
  PIN qrq[85]
    DIRECTION INPUT ;
    USE SIGNAL ;
    PORT
      LAYER M5 ;
        RECT  25.488 43.008 25.512 43.2 ;
    END
  END qrq[85]
  PIN qrq[86]
    DIRECTION INPUT ;
    USE SIGNAL ;
    PORT
      LAYER M5 ;
        RECT  25.584 43.008 25.608 43.2 ;
    END
  END qrq[86]
  PIN qrq[87]
    DIRECTION INPUT ;
    USE SIGNAL ;
    PORT
      LAYER M5 ;
        RECT  25.68 43.008 25.704 43.2 ;
    END
  END qrq[87]
  PIN qrq[88]
    DIRECTION INPUT ;
    USE SIGNAL ;
    PORT
      LAYER M5 ;
        RECT  25.776 43.008 25.8 43.2 ;
    END
  END qrq[88]
  PIN qrq[89]
    DIRECTION INPUT ;
    USE SIGNAL ;
    PORT
      LAYER M5 ;
        RECT  25.872 43.008 25.896 43.2 ;
    END
  END qrq[89]
  PIN qrq[8]
    DIRECTION INPUT ;
    USE SIGNAL ;
    PORT
      LAYER M5 ;
        RECT  18.096 43.008 18.12 43.2 ;
    END
  END qrq[8]
  PIN qrq[90]
    DIRECTION INPUT ;
    USE SIGNAL ;
    PORT
      LAYER M5 ;
        RECT  25.968 43.008 25.992 43.2 ;
    END
  END qrq[90]
  PIN qrq[91]
    DIRECTION INPUT ;
    USE SIGNAL ;
    PORT
      LAYER M5 ;
        RECT  26.064 43.008 26.088 43.2 ;
    END
  END qrq[91]
  PIN qrq[92]
    DIRECTION INPUT ;
    USE SIGNAL ;
    PORT
      LAYER M5 ;
        RECT  26.16 43.008 26.184 43.2 ;
    END
  END qrq[92]
  PIN qrq[93]
    DIRECTION INPUT ;
    USE SIGNAL ;
    PORT
      LAYER M5 ;
        RECT  26.256 43.008 26.28 43.2 ;
    END
  END qrq[93]
  PIN qrq[94]
    DIRECTION INPUT ;
    USE SIGNAL ;
    PORT
      LAYER M5 ;
        RECT  26.352 43.008 26.376 43.2 ;
    END
  END qrq[94]
  PIN qrq[95]
    DIRECTION INPUT ;
    USE SIGNAL ;
    PORT
      LAYER M5 ;
        RECT  26.448 43.008 26.472 43.2 ;
    END
  END qrq[95]
  PIN qrq[96]
    DIRECTION INPUT ;
    USE SIGNAL ;
    PORT
      LAYER M5 ;
        RECT  26.544 43.008 26.568 43.2 ;
    END
  END qrq[96]
  PIN qrq[97]
    DIRECTION INPUT ;
    USE SIGNAL ;
    PORT
      LAYER M5 ;
        RECT  26.64 43.008 26.664 43.2 ;
    END
  END qrq[97]
  PIN qrq[98]
    DIRECTION INPUT ;
    USE SIGNAL ;
    PORT
      LAYER M5 ;
        RECT  26.736 43.008 26.76 43.2 ;
    END
  END qrq[98]
  PIN qrq[99]
    DIRECTION INPUT ;
    USE SIGNAL ;
    PORT
      LAYER M5 ;
        RECT  26.832 43.008 26.856 43.2 ;
    END
  END qrq[99]
  PIN qrq[9]
    DIRECTION INPUT ;
    USE SIGNAL ;
    PORT
      LAYER M5 ;
        RECT  18.192 43.008 18.216 43.2 ;
    END
  END qrq[9]
  PIN qrv[0]
    DIRECTION OUTPUT ;
    USE SIGNAL ;
    PORT
      LAYER M5 ;
        RECT  106.752 43.008 106.776 43.2 ;
    END
  END qrv[0]
  PIN qwd[0]
    DIRECTION OUTPUT ;
    USE SIGNAL ;
    PORT
      LAYER M5 ;
        RECT  50.16 43.008 50.184 43.2 ;
    END
  END qwd[0]
  PIN r_beat[0]
    DIRECTION INPUT ;
    USE SIGNAL ;
    PORT
      LAYER M5 ;
        RECT  106.368 0 106.392 0.192 ;
    END
  END r_beat[0]
  PIN r_beat[1]
    DIRECTION INPUT ;
    USE SIGNAL ;
    PORT
      LAYER M5 ;
        RECT  106.464 0 106.488 0.192 ;
    END
  END r_beat[1]
  PIN r_beat[2]
    DIRECTION INPUT ;
    USE SIGNAL ;
    PORT
      LAYER M5 ;
        RECT  106.56 0 106.584 0.192 ;
    END
  END r_beat[2]
  PIN r_beat[3]
    DIRECTION INPUT ;
    USE SIGNAL ;
    PORT
      LAYER M5 ;
        RECT  106.656 0 106.68 0.192 ;
    END
  END r_beat[3]
  PIN r_data[0]
    DIRECTION INPUT ;
    USE SIGNAL ;
    PORT
      LAYER M5 ;
        RECT  80.16 0 80.184 0.192 ;
    END
  END r_data[0]
  PIN r_data[100]
    DIRECTION INPUT ;
    USE SIGNAL ;
    PORT
      LAYER M5 ;
        RECT  89.76 0 89.784 0.192 ;
    END
  END r_data[100]
  PIN r_data[101]
    DIRECTION INPUT ;
    USE SIGNAL ;
    PORT
      LAYER M5 ;
        RECT  89.856 0 89.88 0.192 ;
    END
  END r_data[101]
  PIN r_data[102]
    DIRECTION INPUT ;
    USE SIGNAL ;
    PORT
      LAYER M5 ;
        RECT  89.952 0 89.976 0.192 ;
    END
  END r_data[102]
  PIN r_data[103]
    DIRECTION INPUT ;
    USE SIGNAL ;
    PORT
      LAYER M5 ;
        RECT  90.048 0 90.072 0.192 ;
    END
  END r_data[103]
  PIN r_data[104]
    DIRECTION INPUT ;
    USE SIGNAL ;
    PORT
      LAYER M5 ;
        RECT  90.144 0 90.168 0.192 ;
    END
  END r_data[104]
  PIN r_data[105]
    DIRECTION INPUT ;
    USE SIGNAL ;
    PORT
      LAYER M5 ;
        RECT  90.24 0 90.264 0.192 ;
    END
  END r_data[105]
  PIN r_data[106]
    DIRECTION INPUT ;
    USE SIGNAL ;
    PORT
      LAYER M5 ;
        RECT  90.336 0 90.36 0.192 ;
    END
  END r_data[106]
  PIN r_data[107]
    DIRECTION INPUT ;
    USE SIGNAL ;
    PORT
      LAYER M5 ;
        RECT  90.432 0 90.456 0.192 ;
    END
  END r_data[107]
  PIN r_data[108]
    DIRECTION INPUT ;
    USE SIGNAL ;
    PORT
      LAYER M5 ;
        RECT  90.528 0 90.552 0.192 ;
    END
  END r_data[108]
  PIN r_data[109]
    DIRECTION INPUT ;
    USE SIGNAL ;
    PORT
      LAYER M5 ;
        RECT  90.624 0 90.648 0.192 ;
    END
  END r_data[109]
  PIN r_data[10]
    DIRECTION INPUT ;
    USE SIGNAL ;
    PORT
      LAYER M5 ;
        RECT  81.12 0 81.144 0.192 ;
    END
  END r_data[10]
  PIN r_data[110]
    DIRECTION INPUT ;
    USE SIGNAL ;
    PORT
      LAYER M5 ;
        RECT  90.72 0 90.744 0.192 ;
    END
  END r_data[110]
  PIN r_data[111]
    DIRECTION INPUT ;
    USE SIGNAL ;
    PORT
      LAYER M5 ;
        RECT  90.816 0 90.84 0.192 ;
    END
  END r_data[111]
  PIN r_data[112]
    DIRECTION INPUT ;
    USE SIGNAL ;
    PORT
      LAYER M5 ;
        RECT  90.912 0 90.936 0.192 ;
    END
  END r_data[112]
  PIN r_data[113]
    DIRECTION INPUT ;
    USE SIGNAL ;
    PORT
      LAYER M5 ;
        RECT  91.008 0 91.032 0.192 ;
    END
  END r_data[113]
  PIN r_data[114]
    DIRECTION INPUT ;
    USE SIGNAL ;
    PORT
      LAYER M5 ;
        RECT  91.104 0 91.128 0.192 ;
    END
  END r_data[114]
  PIN r_data[115]
    DIRECTION INPUT ;
    USE SIGNAL ;
    PORT
      LAYER M5 ;
        RECT  91.2 0 91.224 0.192 ;
    END
  END r_data[115]
  PIN r_data[116]
    DIRECTION INPUT ;
    USE SIGNAL ;
    PORT
      LAYER M5 ;
        RECT  91.296 0 91.32 0.192 ;
    END
  END r_data[116]
  PIN r_data[117]
    DIRECTION INPUT ;
    USE SIGNAL ;
    PORT
      LAYER M5 ;
        RECT  91.392 0 91.416 0.192 ;
    END
  END r_data[117]
  PIN r_data[118]
    DIRECTION INPUT ;
    USE SIGNAL ;
    PORT
      LAYER M5 ;
        RECT  91.488 0 91.512 0.192 ;
    END
  END r_data[118]
  PIN r_data[119]
    DIRECTION INPUT ;
    USE SIGNAL ;
    PORT
      LAYER M5 ;
        RECT  91.584 0 91.608 0.192 ;
    END
  END r_data[119]
  PIN r_data[11]
    DIRECTION INPUT ;
    USE SIGNAL ;
    PORT
      LAYER M5 ;
        RECT  81.216 0 81.24 0.192 ;
    END
  END r_data[11]
  PIN r_data[120]
    DIRECTION INPUT ;
    USE SIGNAL ;
    PORT
      LAYER M5 ;
        RECT  91.68 0 91.704 0.192 ;
    END
  END r_data[120]
  PIN r_data[121]
    DIRECTION INPUT ;
    USE SIGNAL ;
    PORT
      LAYER M5 ;
        RECT  91.776 0 91.8 0.192 ;
    END
  END r_data[121]
  PIN r_data[122]
    DIRECTION INPUT ;
    USE SIGNAL ;
    PORT
      LAYER M5 ;
        RECT  91.872 0 91.896 0.192 ;
    END
  END r_data[122]
  PIN r_data[123]
    DIRECTION INPUT ;
    USE SIGNAL ;
    PORT
      LAYER M5 ;
        RECT  91.968 0 91.992 0.192 ;
    END
  END r_data[123]
  PIN r_data[124]
    DIRECTION INPUT ;
    USE SIGNAL ;
    PORT
      LAYER M5 ;
        RECT  92.064 0 92.088 0.192 ;
    END
  END r_data[124]
  PIN r_data[125]
    DIRECTION INPUT ;
    USE SIGNAL ;
    PORT
      LAYER M5 ;
        RECT  92.16 0 92.184 0.192 ;
    END
  END r_data[125]
  PIN r_data[126]
    DIRECTION INPUT ;
    USE SIGNAL ;
    PORT
      LAYER M5 ;
        RECT  92.256 0 92.28 0.192 ;
    END
  END r_data[126]
  PIN r_data[127]
    DIRECTION INPUT ;
    USE SIGNAL ;
    PORT
      LAYER M5 ;
        RECT  92.352 0 92.376 0.192 ;
    END
  END r_data[127]
  PIN r_data[128]
    DIRECTION INPUT ;
    USE SIGNAL ;
    PORT
      LAYER M5 ;
        RECT  92.448 0 92.472 0.192 ;
    END
  END r_data[128]
  PIN r_data[129]
    DIRECTION INPUT ;
    USE SIGNAL ;
    PORT
      LAYER M5 ;
        RECT  92.544 0 92.568 0.192 ;
    END
  END r_data[129]
  PIN r_data[12]
    DIRECTION INPUT ;
    USE SIGNAL ;
    PORT
      LAYER M5 ;
        RECT  81.312 0 81.336 0.192 ;
    END
  END r_data[12]
  PIN r_data[130]
    DIRECTION INPUT ;
    USE SIGNAL ;
    PORT
      LAYER M5 ;
        RECT  92.64 0 92.664 0.192 ;
    END
  END r_data[130]
  PIN r_data[131]
    DIRECTION INPUT ;
    USE SIGNAL ;
    PORT
      LAYER M5 ;
        RECT  92.736 0 92.76 0.192 ;
    END
  END r_data[131]
  PIN r_data[132]
    DIRECTION INPUT ;
    USE SIGNAL ;
    PORT
      LAYER M5 ;
        RECT  92.832 0 92.856 0.192 ;
    END
  END r_data[132]
  PIN r_data[133]
    DIRECTION INPUT ;
    USE SIGNAL ;
    PORT
      LAYER M5 ;
        RECT  92.928 0 92.952 0.192 ;
    END
  END r_data[133]
  PIN r_data[134]
    DIRECTION INPUT ;
    USE SIGNAL ;
    PORT
      LAYER M5 ;
        RECT  93.024 0 93.048 0.192 ;
    END
  END r_data[134]
  PIN r_data[135]
    DIRECTION INPUT ;
    USE SIGNAL ;
    PORT
      LAYER M5 ;
        RECT  93.12 0 93.144 0.192 ;
    END
  END r_data[135]
  PIN r_data[136]
    DIRECTION INPUT ;
    USE SIGNAL ;
    PORT
      LAYER M5 ;
        RECT  93.216 0 93.24 0.192 ;
    END
  END r_data[136]
  PIN r_data[137]
    DIRECTION INPUT ;
    USE SIGNAL ;
    PORT
      LAYER M5 ;
        RECT  93.312 0 93.336 0.192 ;
    END
  END r_data[137]
  PIN r_data[138]
    DIRECTION INPUT ;
    USE SIGNAL ;
    PORT
      LAYER M5 ;
        RECT  93.408 0 93.432 0.192 ;
    END
  END r_data[138]
  PIN r_data[139]
    DIRECTION INPUT ;
    USE SIGNAL ;
    PORT
      LAYER M5 ;
        RECT  93.504 0 93.528 0.192 ;
    END
  END r_data[139]
  PIN r_data[13]
    DIRECTION INPUT ;
    USE SIGNAL ;
    PORT
      LAYER M5 ;
        RECT  81.408 0 81.432 0.192 ;
    END
  END r_data[13]
  PIN r_data[140]
    DIRECTION INPUT ;
    USE SIGNAL ;
    PORT
      LAYER M5 ;
        RECT  93.6 0 93.624 0.192 ;
    END
  END r_data[140]
  PIN r_data[141]
    DIRECTION INPUT ;
    USE SIGNAL ;
    PORT
      LAYER M5 ;
        RECT  93.696 0 93.72 0.192 ;
    END
  END r_data[141]
  PIN r_data[142]
    DIRECTION INPUT ;
    USE SIGNAL ;
    PORT
      LAYER M5 ;
        RECT  93.792 0 93.816 0.192 ;
    END
  END r_data[142]
  PIN r_data[143]
    DIRECTION INPUT ;
    USE SIGNAL ;
    PORT
      LAYER M5 ;
        RECT  93.888 0 93.912 0.192 ;
    END
  END r_data[143]
  PIN r_data[144]
    DIRECTION INPUT ;
    USE SIGNAL ;
    PORT
      LAYER M5 ;
        RECT  93.984 0 94.008 0.192 ;
    END
  END r_data[144]
  PIN r_data[145]
    DIRECTION INPUT ;
    USE SIGNAL ;
    PORT
      LAYER M5 ;
        RECT  94.08 0 94.104 0.192 ;
    END
  END r_data[145]
  PIN r_data[146]
    DIRECTION INPUT ;
    USE SIGNAL ;
    PORT
      LAYER M5 ;
        RECT  94.176 0 94.2 0.192 ;
    END
  END r_data[146]
  PIN r_data[147]
    DIRECTION INPUT ;
    USE SIGNAL ;
    PORT
      LAYER M5 ;
        RECT  94.272 0 94.296 0.192 ;
    END
  END r_data[147]
  PIN r_data[148]
    DIRECTION INPUT ;
    USE SIGNAL ;
    PORT
      LAYER M5 ;
        RECT  94.368 0 94.392 0.192 ;
    END
  END r_data[148]
  PIN r_data[149]
    DIRECTION INPUT ;
    USE SIGNAL ;
    PORT
      LAYER M5 ;
        RECT  94.464 0 94.488 0.192 ;
    END
  END r_data[149]
  PIN r_data[14]
    DIRECTION INPUT ;
    USE SIGNAL ;
    PORT
      LAYER M5 ;
        RECT  81.504 0 81.528 0.192 ;
    END
  END r_data[14]
  PIN r_data[150]
    DIRECTION INPUT ;
    USE SIGNAL ;
    PORT
      LAYER M5 ;
        RECT  94.56 0 94.584 0.192 ;
    END
  END r_data[150]
  PIN r_data[151]
    DIRECTION INPUT ;
    USE SIGNAL ;
    PORT
      LAYER M5 ;
        RECT  94.656 0 94.68 0.192 ;
    END
  END r_data[151]
  PIN r_data[152]
    DIRECTION INPUT ;
    USE SIGNAL ;
    PORT
      LAYER M5 ;
        RECT  94.752 0 94.776 0.192 ;
    END
  END r_data[152]
  PIN r_data[153]
    DIRECTION INPUT ;
    USE SIGNAL ;
    PORT
      LAYER M5 ;
        RECT  94.848 0 94.872 0.192 ;
    END
  END r_data[153]
  PIN r_data[154]
    DIRECTION INPUT ;
    USE SIGNAL ;
    PORT
      LAYER M5 ;
        RECT  94.944 0 94.968 0.192 ;
    END
  END r_data[154]
  PIN r_data[155]
    DIRECTION INPUT ;
    USE SIGNAL ;
    PORT
      LAYER M5 ;
        RECT  95.04 0 95.064 0.192 ;
    END
  END r_data[155]
  PIN r_data[156]
    DIRECTION INPUT ;
    USE SIGNAL ;
    PORT
      LAYER M5 ;
        RECT  95.136 0 95.16 0.192 ;
    END
  END r_data[156]
  PIN r_data[157]
    DIRECTION INPUT ;
    USE SIGNAL ;
    PORT
      LAYER M5 ;
        RECT  95.232 0 95.256 0.192 ;
    END
  END r_data[157]
  PIN r_data[158]
    DIRECTION INPUT ;
    USE SIGNAL ;
    PORT
      LAYER M5 ;
        RECT  95.328 0 95.352 0.192 ;
    END
  END r_data[158]
  PIN r_data[159]
    DIRECTION INPUT ;
    USE SIGNAL ;
    PORT
      LAYER M5 ;
        RECT  95.424 0 95.448 0.192 ;
    END
  END r_data[159]
  PIN r_data[15]
    DIRECTION INPUT ;
    USE SIGNAL ;
    PORT
      LAYER M5 ;
        RECT  81.6 0 81.624 0.192 ;
    END
  END r_data[15]
  PIN r_data[160]
    DIRECTION INPUT ;
    USE SIGNAL ;
    PORT
      LAYER M5 ;
        RECT  95.52 0 95.544 0.192 ;
    END
  END r_data[160]
  PIN r_data[161]
    DIRECTION INPUT ;
    USE SIGNAL ;
    PORT
      LAYER M5 ;
        RECT  95.616 0 95.64 0.192 ;
    END
  END r_data[161]
  PIN r_data[162]
    DIRECTION INPUT ;
    USE SIGNAL ;
    PORT
      LAYER M5 ;
        RECT  95.712 0 95.736 0.192 ;
    END
  END r_data[162]
  PIN r_data[163]
    DIRECTION INPUT ;
    USE SIGNAL ;
    PORT
      LAYER M5 ;
        RECT  95.808 0 95.832 0.192 ;
    END
  END r_data[163]
  PIN r_data[164]
    DIRECTION INPUT ;
    USE SIGNAL ;
    PORT
      LAYER M5 ;
        RECT  95.904 0 95.928 0.192 ;
    END
  END r_data[164]
  PIN r_data[165]
    DIRECTION INPUT ;
    USE SIGNAL ;
    PORT
      LAYER M5 ;
        RECT  96 0 96.024 0.192 ;
    END
  END r_data[165]
  PIN r_data[166]
    DIRECTION INPUT ;
    USE SIGNAL ;
    PORT
      LAYER M5 ;
        RECT  96.096 0 96.12 0.192 ;
    END
  END r_data[166]
  PIN r_data[167]
    DIRECTION INPUT ;
    USE SIGNAL ;
    PORT
      LAYER M5 ;
        RECT  96.192 0 96.216 0.192 ;
    END
  END r_data[167]
  PIN r_data[168]
    DIRECTION INPUT ;
    USE SIGNAL ;
    PORT
      LAYER M5 ;
        RECT  96.288 0 96.312 0.192 ;
    END
  END r_data[168]
  PIN r_data[169]
    DIRECTION INPUT ;
    USE SIGNAL ;
    PORT
      LAYER M5 ;
        RECT  96.384 0 96.408 0.192 ;
    END
  END r_data[169]
  PIN r_data[16]
    DIRECTION INPUT ;
    USE SIGNAL ;
    PORT
      LAYER M5 ;
        RECT  81.696 0 81.72 0.192 ;
    END
  END r_data[16]
  PIN r_data[170]
    DIRECTION INPUT ;
    USE SIGNAL ;
    PORT
      LAYER M5 ;
        RECT  96.48 0 96.504 0.192 ;
    END
  END r_data[170]
  PIN r_data[171]
    DIRECTION INPUT ;
    USE SIGNAL ;
    PORT
      LAYER M5 ;
        RECT  96.576 0 96.6 0.192 ;
    END
  END r_data[171]
  PIN r_data[172]
    DIRECTION INPUT ;
    USE SIGNAL ;
    PORT
      LAYER M5 ;
        RECT  96.672 0 96.696 0.192 ;
    END
  END r_data[172]
  PIN r_data[173]
    DIRECTION INPUT ;
    USE SIGNAL ;
    PORT
      LAYER M5 ;
        RECT  96.768 0 96.792 0.192 ;
    END
  END r_data[173]
  PIN r_data[174]
    DIRECTION INPUT ;
    USE SIGNAL ;
    PORT
      LAYER M5 ;
        RECT  96.864 0 96.888 0.192 ;
    END
  END r_data[174]
  PIN r_data[175]
    DIRECTION INPUT ;
    USE SIGNAL ;
    PORT
      LAYER M5 ;
        RECT  96.96 0 96.984 0.192 ;
    END
  END r_data[175]
  PIN r_data[176]
    DIRECTION INPUT ;
    USE SIGNAL ;
    PORT
      LAYER M5 ;
        RECT  97.056 0 97.08 0.192 ;
    END
  END r_data[176]
  PIN r_data[177]
    DIRECTION INPUT ;
    USE SIGNAL ;
    PORT
      LAYER M5 ;
        RECT  97.152 0 97.176 0.192 ;
    END
  END r_data[177]
  PIN r_data[178]
    DIRECTION INPUT ;
    USE SIGNAL ;
    PORT
      LAYER M5 ;
        RECT  97.248 0 97.272 0.192 ;
    END
  END r_data[178]
  PIN r_data[179]
    DIRECTION INPUT ;
    USE SIGNAL ;
    PORT
      LAYER M5 ;
        RECT  97.344 0 97.368 0.192 ;
    END
  END r_data[179]
  PIN r_data[17]
    DIRECTION INPUT ;
    USE SIGNAL ;
    PORT
      LAYER M5 ;
        RECT  81.792 0 81.816 0.192 ;
    END
  END r_data[17]
  PIN r_data[180]
    DIRECTION INPUT ;
    USE SIGNAL ;
    PORT
      LAYER M5 ;
        RECT  97.44 0 97.464 0.192 ;
    END
  END r_data[180]
  PIN r_data[181]
    DIRECTION INPUT ;
    USE SIGNAL ;
    PORT
      LAYER M5 ;
        RECT  97.536 0 97.56 0.192 ;
    END
  END r_data[181]
  PIN r_data[182]
    DIRECTION INPUT ;
    USE SIGNAL ;
    PORT
      LAYER M5 ;
        RECT  97.632 0 97.656 0.192 ;
    END
  END r_data[182]
  PIN r_data[183]
    DIRECTION INPUT ;
    USE SIGNAL ;
    PORT
      LAYER M5 ;
        RECT  97.728 0 97.752 0.192 ;
    END
  END r_data[183]
  PIN r_data[184]
    DIRECTION INPUT ;
    USE SIGNAL ;
    PORT
      LAYER M5 ;
        RECT  97.824 0 97.848 0.192 ;
    END
  END r_data[184]
  PIN r_data[185]
    DIRECTION INPUT ;
    USE SIGNAL ;
    PORT
      LAYER M5 ;
        RECT  97.92 0 97.944 0.192 ;
    END
  END r_data[185]
  PIN r_data[186]
    DIRECTION INPUT ;
    USE SIGNAL ;
    PORT
      LAYER M5 ;
        RECT  98.016 0 98.04 0.192 ;
    END
  END r_data[186]
  PIN r_data[187]
    DIRECTION INPUT ;
    USE SIGNAL ;
    PORT
      LAYER M5 ;
        RECT  98.112 0 98.136 0.192 ;
    END
  END r_data[187]
  PIN r_data[188]
    DIRECTION INPUT ;
    USE SIGNAL ;
    PORT
      LAYER M5 ;
        RECT  98.208 0 98.232 0.192 ;
    END
  END r_data[188]
  PIN r_data[189]
    DIRECTION INPUT ;
    USE SIGNAL ;
    PORT
      LAYER M5 ;
        RECT  98.304 0 98.328 0.192 ;
    END
  END r_data[189]
  PIN r_data[18]
    DIRECTION INPUT ;
    USE SIGNAL ;
    PORT
      LAYER M5 ;
        RECT  81.888 0 81.912 0.192 ;
    END
  END r_data[18]
  PIN r_data[190]
    DIRECTION INPUT ;
    USE SIGNAL ;
    PORT
      LAYER M5 ;
        RECT  98.4 0 98.424 0.192 ;
    END
  END r_data[190]
  PIN r_data[191]
    DIRECTION INPUT ;
    USE SIGNAL ;
    PORT
      LAYER M5 ;
        RECT  98.496 0 98.52 0.192 ;
    END
  END r_data[191]
  PIN r_data[192]
    DIRECTION INPUT ;
    USE SIGNAL ;
    PORT
      LAYER M5 ;
        RECT  98.592 0 98.616 0.192 ;
    END
  END r_data[192]
  PIN r_data[193]
    DIRECTION INPUT ;
    USE SIGNAL ;
    PORT
      LAYER M5 ;
        RECT  98.688 0 98.712 0.192 ;
    END
  END r_data[193]
  PIN r_data[194]
    DIRECTION INPUT ;
    USE SIGNAL ;
    PORT
      LAYER M5 ;
        RECT  98.784 0 98.808 0.192 ;
    END
  END r_data[194]
  PIN r_data[195]
    DIRECTION INPUT ;
    USE SIGNAL ;
    PORT
      LAYER M5 ;
        RECT  98.88 0 98.904 0.192 ;
    END
  END r_data[195]
  PIN r_data[196]
    DIRECTION INPUT ;
    USE SIGNAL ;
    PORT
      LAYER M5 ;
        RECT  98.976 0 99 0.192 ;
    END
  END r_data[196]
  PIN r_data[197]
    DIRECTION INPUT ;
    USE SIGNAL ;
    PORT
      LAYER M5 ;
        RECT  99.072 0 99.096 0.192 ;
    END
  END r_data[197]
  PIN r_data[198]
    DIRECTION INPUT ;
    USE SIGNAL ;
    PORT
      LAYER M5 ;
        RECT  99.168 0 99.192 0.192 ;
    END
  END r_data[198]
  PIN r_data[199]
    DIRECTION INPUT ;
    USE SIGNAL ;
    PORT
      LAYER M5 ;
        RECT  99.264 0 99.288 0.192 ;
    END
  END r_data[199]
  PIN r_data[19]
    DIRECTION INPUT ;
    USE SIGNAL ;
    PORT
      LAYER M5 ;
        RECT  81.984 0 82.008 0.192 ;
    END
  END r_data[19]
  PIN r_data[1]
    DIRECTION INPUT ;
    USE SIGNAL ;
    PORT
      LAYER M5 ;
        RECT  80.256 0 80.28 0.192 ;
    END
  END r_data[1]
  PIN r_data[200]
    DIRECTION INPUT ;
    USE SIGNAL ;
    PORT
      LAYER M5 ;
        RECT  99.36 0 99.384 0.192 ;
    END
  END r_data[200]
  PIN r_data[201]
    DIRECTION INPUT ;
    USE SIGNAL ;
    PORT
      LAYER M5 ;
        RECT  99.456 0 99.48 0.192 ;
    END
  END r_data[201]
  PIN r_data[202]
    DIRECTION INPUT ;
    USE SIGNAL ;
    PORT
      LAYER M5 ;
        RECT  99.552 0 99.576 0.192 ;
    END
  END r_data[202]
  PIN r_data[203]
    DIRECTION INPUT ;
    USE SIGNAL ;
    PORT
      LAYER M5 ;
        RECT  99.648 0 99.672 0.192 ;
    END
  END r_data[203]
  PIN r_data[204]
    DIRECTION INPUT ;
    USE SIGNAL ;
    PORT
      LAYER M5 ;
        RECT  99.744 0 99.768 0.192 ;
    END
  END r_data[204]
  PIN r_data[205]
    DIRECTION INPUT ;
    USE SIGNAL ;
    PORT
      LAYER M5 ;
        RECT  99.84 0 99.864 0.192 ;
    END
  END r_data[205]
  PIN r_data[206]
    DIRECTION INPUT ;
    USE SIGNAL ;
    PORT
      LAYER M5 ;
        RECT  99.936 0 99.96 0.192 ;
    END
  END r_data[206]
  PIN r_data[207]
    DIRECTION INPUT ;
    USE SIGNAL ;
    PORT
      LAYER M5 ;
        RECT  100.032 0 100.056 0.192 ;
    END
  END r_data[207]
  PIN r_data[208]
    DIRECTION INPUT ;
    USE SIGNAL ;
    PORT
      LAYER M5 ;
        RECT  100.128 0 100.152 0.192 ;
    END
  END r_data[208]
  PIN r_data[209]
    DIRECTION INPUT ;
    USE SIGNAL ;
    PORT
      LAYER M5 ;
        RECT  100.224 0 100.248 0.192 ;
    END
  END r_data[209]
  PIN r_data[20]
    DIRECTION INPUT ;
    USE SIGNAL ;
    PORT
      LAYER M5 ;
        RECT  82.08 0 82.104 0.192 ;
    END
  END r_data[20]
  PIN r_data[210]
    DIRECTION INPUT ;
    USE SIGNAL ;
    PORT
      LAYER M5 ;
        RECT  100.32 0 100.344 0.192 ;
    END
  END r_data[210]
  PIN r_data[211]
    DIRECTION INPUT ;
    USE SIGNAL ;
    PORT
      LAYER M5 ;
        RECT  100.416 0 100.44 0.192 ;
    END
  END r_data[211]
  PIN r_data[212]
    DIRECTION INPUT ;
    USE SIGNAL ;
    PORT
      LAYER M5 ;
        RECT  100.512 0 100.536 0.192 ;
    END
  END r_data[212]
  PIN r_data[213]
    DIRECTION INPUT ;
    USE SIGNAL ;
    PORT
      LAYER M5 ;
        RECT  100.608 0 100.632 0.192 ;
    END
  END r_data[213]
  PIN r_data[214]
    DIRECTION INPUT ;
    USE SIGNAL ;
    PORT
      LAYER M5 ;
        RECT  100.704 0 100.728 0.192 ;
    END
  END r_data[214]
  PIN r_data[215]
    DIRECTION INPUT ;
    USE SIGNAL ;
    PORT
      LAYER M5 ;
        RECT  100.8 0 100.824 0.192 ;
    END
  END r_data[215]
  PIN r_data[216]
    DIRECTION INPUT ;
    USE SIGNAL ;
    PORT
      LAYER M5 ;
        RECT  100.896 0 100.92 0.192 ;
    END
  END r_data[216]
  PIN r_data[217]
    DIRECTION INPUT ;
    USE SIGNAL ;
    PORT
      LAYER M5 ;
        RECT  100.992 0 101.016 0.192 ;
    END
  END r_data[217]
  PIN r_data[218]
    DIRECTION INPUT ;
    USE SIGNAL ;
    PORT
      LAYER M5 ;
        RECT  101.088 0 101.112 0.192 ;
    END
  END r_data[218]
  PIN r_data[219]
    DIRECTION INPUT ;
    USE SIGNAL ;
    PORT
      LAYER M5 ;
        RECT  101.184 0 101.208 0.192 ;
    END
  END r_data[219]
  PIN r_data[21]
    DIRECTION INPUT ;
    USE SIGNAL ;
    PORT
      LAYER M5 ;
        RECT  82.176 0 82.2 0.192 ;
    END
  END r_data[21]
  PIN r_data[220]
    DIRECTION INPUT ;
    USE SIGNAL ;
    PORT
      LAYER M5 ;
        RECT  101.28 0 101.304 0.192 ;
    END
  END r_data[220]
  PIN r_data[221]
    DIRECTION INPUT ;
    USE SIGNAL ;
    PORT
      LAYER M5 ;
        RECT  101.376 0 101.4 0.192 ;
    END
  END r_data[221]
  PIN r_data[222]
    DIRECTION INPUT ;
    USE SIGNAL ;
    PORT
      LAYER M5 ;
        RECT  101.472 0 101.496 0.192 ;
    END
  END r_data[222]
  PIN r_data[223]
    DIRECTION INPUT ;
    USE SIGNAL ;
    PORT
      LAYER M5 ;
        RECT  101.568 0 101.592 0.192 ;
    END
  END r_data[223]
  PIN r_data[224]
    DIRECTION INPUT ;
    USE SIGNAL ;
    PORT
      LAYER M5 ;
        RECT  101.664 0 101.688 0.192 ;
    END
  END r_data[224]
  PIN r_data[225]
    DIRECTION INPUT ;
    USE SIGNAL ;
    PORT
      LAYER M5 ;
        RECT  101.76 0 101.784 0.192 ;
    END
  END r_data[225]
  PIN r_data[226]
    DIRECTION INPUT ;
    USE SIGNAL ;
    PORT
      LAYER M5 ;
        RECT  101.856 0 101.88 0.192 ;
    END
  END r_data[226]
  PIN r_data[227]
    DIRECTION INPUT ;
    USE SIGNAL ;
    PORT
      LAYER M5 ;
        RECT  101.952 0 101.976 0.192 ;
    END
  END r_data[227]
  PIN r_data[228]
    DIRECTION INPUT ;
    USE SIGNAL ;
    PORT
      LAYER M5 ;
        RECT  102.048 0 102.072 0.192 ;
    END
  END r_data[228]
  PIN r_data[229]
    DIRECTION INPUT ;
    USE SIGNAL ;
    PORT
      LAYER M5 ;
        RECT  102.144 0 102.168 0.192 ;
    END
  END r_data[229]
  PIN r_data[22]
    DIRECTION INPUT ;
    USE SIGNAL ;
    PORT
      LAYER M5 ;
        RECT  82.272 0 82.296 0.192 ;
    END
  END r_data[22]
  PIN r_data[230]
    DIRECTION INPUT ;
    USE SIGNAL ;
    PORT
      LAYER M5 ;
        RECT  102.24 0 102.264 0.192 ;
    END
  END r_data[230]
  PIN r_data[231]
    DIRECTION INPUT ;
    USE SIGNAL ;
    PORT
      LAYER M5 ;
        RECT  102.336 0 102.36 0.192 ;
    END
  END r_data[231]
  PIN r_data[232]
    DIRECTION INPUT ;
    USE SIGNAL ;
    PORT
      LAYER M5 ;
        RECT  102.432 0 102.456 0.192 ;
    END
  END r_data[232]
  PIN r_data[233]
    DIRECTION INPUT ;
    USE SIGNAL ;
    PORT
      LAYER M5 ;
        RECT  102.528 0 102.552 0.192 ;
    END
  END r_data[233]
  PIN r_data[234]
    DIRECTION INPUT ;
    USE SIGNAL ;
    PORT
      LAYER M5 ;
        RECT  102.624 0 102.648 0.192 ;
    END
  END r_data[234]
  PIN r_data[235]
    DIRECTION INPUT ;
    USE SIGNAL ;
    PORT
      LAYER M5 ;
        RECT  102.72 0 102.744 0.192 ;
    END
  END r_data[235]
  PIN r_data[236]
    DIRECTION INPUT ;
    USE SIGNAL ;
    PORT
      LAYER M5 ;
        RECT  102.816 0 102.84 0.192 ;
    END
  END r_data[236]
  PIN r_data[237]
    DIRECTION INPUT ;
    USE SIGNAL ;
    PORT
      LAYER M5 ;
        RECT  102.912 0 102.936 0.192 ;
    END
  END r_data[237]
  PIN r_data[238]
    DIRECTION INPUT ;
    USE SIGNAL ;
    PORT
      LAYER M5 ;
        RECT  103.008 0 103.032 0.192 ;
    END
  END r_data[238]
  PIN r_data[239]
    DIRECTION INPUT ;
    USE SIGNAL ;
    PORT
      LAYER M5 ;
        RECT  103.104 0 103.128 0.192 ;
    END
  END r_data[239]
  PIN r_data[23]
    DIRECTION INPUT ;
    USE SIGNAL ;
    PORT
      LAYER M5 ;
        RECT  82.368 0 82.392 0.192 ;
    END
  END r_data[23]
  PIN r_data[240]
    DIRECTION INPUT ;
    USE SIGNAL ;
    PORT
      LAYER M5 ;
        RECT  103.2 0 103.224 0.192 ;
    END
  END r_data[240]
  PIN r_data[241]
    DIRECTION INPUT ;
    USE SIGNAL ;
    PORT
      LAYER M5 ;
        RECT  103.296 0 103.32 0.192 ;
    END
  END r_data[241]
  PIN r_data[242]
    DIRECTION INPUT ;
    USE SIGNAL ;
    PORT
      LAYER M5 ;
        RECT  103.392 0 103.416 0.192 ;
    END
  END r_data[242]
  PIN r_data[243]
    DIRECTION INPUT ;
    USE SIGNAL ;
    PORT
      LAYER M5 ;
        RECT  103.488 0 103.512 0.192 ;
    END
  END r_data[243]
  PIN r_data[244]
    DIRECTION INPUT ;
    USE SIGNAL ;
    PORT
      LAYER M5 ;
        RECT  103.584 0 103.608 0.192 ;
    END
  END r_data[244]
  PIN r_data[245]
    DIRECTION INPUT ;
    USE SIGNAL ;
    PORT
      LAYER M5 ;
        RECT  103.68 0 103.704 0.192 ;
    END
  END r_data[245]
  PIN r_data[246]
    DIRECTION INPUT ;
    USE SIGNAL ;
    PORT
      LAYER M5 ;
        RECT  103.776 0 103.8 0.192 ;
    END
  END r_data[246]
  PIN r_data[247]
    DIRECTION INPUT ;
    USE SIGNAL ;
    PORT
      LAYER M5 ;
        RECT  103.872 0 103.896 0.192 ;
    END
  END r_data[247]
  PIN r_data[248]
    DIRECTION INPUT ;
    USE SIGNAL ;
    PORT
      LAYER M5 ;
        RECT  103.968 0 103.992 0.192 ;
    END
  END r_data[248]
  PIN r_data[249]
    DIRECTION INPUT ;
    USE SIGNAL ;
    PORT
      LAYER M5 ;
        RECT  104.064 0 104.088 0.192 ;
    END
  END r_data[249]
  PIN r_data[24]
    DIRECTION INPUT ;
    USE SIGNAL ;
    PORT
      LAYER M5 ;
        RECT  82.464 0 82.488 0.192 ;
    END
  END r_data[24]
  PIN r_data[250]
    DIRECTION INPUT ;
    USE SIGNAL ;
    PORT
      LAYER M5 ;
        RECT  104.16 0 104.184 0.192 ;
    END
  END r_data[250]
  PIN r_data[251]
    DIRECTION INPUT ;
    USE SIGNAL ;
    PORT
      LAYER M5 ;
        RECT  104.256 0 104.28 0.192 ;
    END
  END r_data[251]
  PIN r_data[252]
    DIRECTION INPUT ;
    USE SIGNAL ;
    PORT
      LAYER M5 ;
        RECT  104.352 0 104.376 0.192 ;
    END
  END r_data[252]
  PIN r_data[253]
    DIRECTION INPUT ;
    USE SIGNAL ;
    PORT
      LAYER M5 ;
        RECT  104.448 0 104.472 0.192 ;
    END
  END r_data[253]
  PIN r_data[254]
    DIRECTION INPUT ;
    USE SIGNAL ;
    PORT
      LAYER M5 ;
        RECT  104.544 0 104.568 0.192 ;
    END
  END r_data[254]
  PIN r_data[255]
    DIRECTION INPUT ;
    USE SIGNAL ;
    PORT
      LAYER M5 ;
        RECT  104.64 0 104.664 0.192 ;
    END
  END r_data[255]
  PIN r_data[25]
    DIRECTION INPUT ;
    USE SIGNAL ;
    PORT
      LAYER M5 ;
        RECT  82.56 0 82.584 0.192 ;
    END
  END r_data[25]
  PIN r_data[26]
    DIRECTION INPUT ;
    USE SIGNAL ;
    PORT
      LAYER M5 ;
        RECT  82.656 0 82.68 0.192 ;
    END
  END r_data[26]
  PIN r_data[27]
    DIRECTION INPUT ;
    USE SIGNAL ;
    PORT
      LAYER M5 ;
        RECT  82.752 0 82.776 0.192 ;
    END
  END r_data[27]
  PIN r_data[28]
    DIRECTION INPUT ;
    USE SIGNAL ;
    PORT
      LAYER M5 ;
        RECT  82.848 0 82.872 0.192 ;
    END
  END r_data[28]
  PIN r_data[29]
    DIRECTION INPUT ;
    USE SIGNAL ;
    PORT
      LAYER M5 ;
        RECT  82.944 0 82.968 0.192 ;
    END
  END r_data[29]
  PIN r_data[2]
    DIRECTION INPUT ;
    USE SIGNAL ;
    PORT
      LAYER M5 ;
        RECT  80.352 0 80.376 0.192 ;
    END
  END r_data[2]
  PIN r_data[30]
    DIRECTION INPUT ;
    USE SIGNAL ;
    PORT
      LAYER M5 ;
        RECT  83.04 0 83.064 0.192 ;
    END
  END r_data[30]
  PIN r_data[31]
    DIRECTION INPUT ;
    USE SIGNAL ;
    PORT
      LAYER M5 ;
        RECT  83.136 0 83.16 0.192 ;
    END
  END r_data[31]
  PIN r_data[32]
    DIRECTION INPUT ;
    USE SIGNAL ;
    PORT
      LAYER M5 ;
        RECT  83.232 0 83.256 0.192 ;
    END
  END r_data[32]
  PIN r_data[33]
    DIRECTION INPUT ;
    USE SIGNAL ;
    PORT
      LAYER M5 ;
        RECT  83.328 0 83.352 0.192 ;
    END
  END r_data[33]
  PIN r_data[34]
    DIRECTION INPUT ;
    USE SIGNAL ;
    PORT
      LAYER M5 ;
        RECT  83.424 0 83.448 0.192 ;
    END
  END r_data[34]
  PIN r_data[35]
    DIRECTION INPUT ;
    USE SIGNAL ;
    PORT
      LAYER M5 ;
        RECT  83.52 0 83.544 0.192 ;
    END
  END r_data[35]
  PIN r_data[36]
    DIRECTION INPUT ;
    USE SIGNAL ;
    PORT
      LAYER M5 ;
        RECT  83.616 0 83.64 0.192 ;
    END
  END r_data[36]
  PIN r_data[37]
    DIRECTION INPUT ;
    USE SIGNAL ;
    PORT
      LAYER M5 ;
        RECT  83.712 0 83.736 0.192 ;
    END
  END r_data[37]
  PIN r_data[38]
    DIRECTION INPUT ;
    USE SIGNAL ;
    PORT
      LAYER M5 ;
        RECT  83.808 0 83.832 0.192 ;
    END
  END r_data[38]
  PIN r_data[39]
    DIRECTION INPUT ;
    USE SIGNAL ;
    PORT
      LAYER M5 ;
        RECT  83.904 0 83.928 0.192 ;
    END
  END r_data[39]
  PIN r_data[3]
    DIRECTION INPUT ;
    USE SIGNAL ;
    PORT
      LAYER M5 ;
        RECT  80.448 0 80.472 0.192 ;
    END
  END r_data[3]
  PIN r_data[40]
    DIRECTION INPUT ;
    USE SIGNAL ;
    PORT
      LAYER M5 ;
        RECT  84 0 84.024 0.192 ;
    END
  END r_data[40]
  PIN r_data[41]
    DIRECTION INPUT ;
    USE SIGNAL ;
    PORT
      LAYER M5 ;
        RECT  84.096 0 84.12 0.192 ;
    END
  END r_data[41]
  PIN r_data[42]
    DIRECTION INPUT ;
    USE SIGNAL ;
    PORT
      LAYER M5 ;
        RECT  84.192 0 84.216 0.192 ;
    END
  END r_data[42]
  PIN r_data[43]
    DIRECTION INPUT ;
    USE SIGNAL ;
    PORT
      LAYER M5 ;
        RECT  84.288 0 84.312 0.192 ;
    END
  END r_data[43]
  PIN r_data[44]
    DIRECTION INPUT ;
    USE SIGNAL ;
    PORT
      LAYER M5 ;
        RECT  84.384 0 84.408 0.192 ;
    END
  END r_data[44]
  PIN r_data[45]
    DIRECTION INPUT ;
    USE SIGNAL ;
    PORT
      LAYER M5 ;
        RECT  84.48 0 84.504 0.192 ;
    END
  END r_data[45]
  PIN r_data[46]
    DIRECTION INPUT ;
    USE SIGNAL ;
    PORT
      LAYER M5 ;
        RECT  84.576 0 84.6 0.192 ;
    END
  END r_data[46]
  PIN r_data[47]
    DIRECTION INPUT ;
    USE SIGNAL ;
    PORT
      LAYER M5 ;
        RECT  84.672 0 84.696 0.192 ;
    END
  END r_data[47]
  PIN r_data[48]
    DIRECTION INPUT ;
    USE SIGNAL ;
    PORT
      LAYER M5 ;
        RECT  84.768 0 84.792 0.192 ;
    END
  END r_data[48]
  PIN r_data[49]
    DIRECTION INPUT ;
    USE SIGNAL ;
    PORT
      LAYER M5 ;
        RECT  84.864 0 84.888 0.192 ;
    END
  END r_data[49]
  PIN r_data[4]
    DIRECTION INPUT ;
    USE SIGNAL ;
    PORT
      LAYER M5 ;
        RECT  80.544 0 80.568 0.192 ;
    END
  END r_data[4]
  PIN r_data[50]
    DIRECTION INPUT ;
    USE SIGNAL ;
    PORT
      LAYER M5 ;
        RECT  84.96 0 84.984 0.192 ;
    END
  END r_data[50]
  PIN r_data[51]
    DIRECTION INPUT ;
    USE SIGNAL ;
    PORT
      LAYER M5 ;
        RECT  85.056 0 85.08 0.192 ;
    END
  END r_data[51]
  PIN r_data[52]
    DIRECTION INPUT ;
    USE SIGNAL ;
    PORT
      LAYER M5 ;
        RECT  85.152 0 85.176 0.192 ;
    END
  END r_data[52]
  PIN r_data[53]
    DIRECTION INPUT ;
    USE SIGNAL ;
    PORT
      LAYER M5 ;
        RECT  85.248 0 85.272 0.192 ;
    END
  END r_data[53]
  PIN r_data[54]
    DIRECTION INPUT ;
    USE SIGNAL ;
    PORT
      LAYER M5 ;
        RECT  85.344 0 85.368 0.192 ;
    END
  END r_data[54]
  PIN r_data[55]
    DIRECTION INPUT ;
    USE SIGNAL ;
    PORT
      LAYER M5 ;
        RECT  85.44 0 85.464 0.192 ;
    END
  END r_data[55]
  PIN r_data[56]
    DIRECTION INPUT ;
    USE SIGNAL ;
    PORT
      LAYER M5 ;
        RECT  85.536 0 85.56 0.192 ;
    END
  END r_data[56]
  PIN r_data[57]
    DIRECTION INPUT ;
    USE SIGNAL ;
    PORT
      LAYER M5 ;
        RECT  85.632 0 85.656 0.192 ;
    END
  END r_data[57]
  PIN r_data[58]
    DIRECTION INPUT ;
    USE SIGNAL ;
    PORT
      LAYER M5 ;
        RECT  85.728 0 85.752 0.192 ;
    END
  END r_data[58]
  PIN r_data[59]
    DIRECTION INPUT ;
    USE SIGNAL ;
    PORT
      LAYER M5 ;
        RECT  85.824 0 85.848 0.192 ;
    END
  END r_data[59]
  PIN r_data[5]
    DIRECTION INPUT ;
    USE SIGNAL ;
    PORT
      LAYER M5 ;
        RECT  80.64 0 80.664 0.192 ;
    END
  END r_data[5]
  PIN r_data[60]
    DIRECTION INPUT ;
    USE SIGNAL ;
    PORT
      LAYER M5 ;
        RECT  85.92 0 85.944 0.192 ;
    END
  END r_data[60]
  PIN r_data[61]
    DIRECTION INPUT ;
    USE SIGNAL ;
    PORT
      LAYER M5 ;
        RECT  86.016 0 86.04 0.192 ;
    END
  END r_data[61]
  PIN r_data[62]
    DIRECTION INPUT ;
    USE SIGNAL ;
    PORT
      LAYER M5 ;
        RECT  86.112 0 86.136 0.192 ;
    END
  END r_data[62]
  PIN r_data[63]
    DIRECTION INPUT ;
    USE SIGNAL ;
    PORT
      LAYER M5 ;
        RECT  86.208 0 86.232 0.192 ;
    END
  END r_data[63]
  PIN r_data[64]
    DIRECTION INPUT ;
    USE SIGNAL ;
    PORT
      LAYER M5 ;
        RECT  86.304 0 86.328 0.192 ;
    END
  END r_data[64]
  PIN r_data[65]
    DIRECTION INPUT ;
    USE SIGNAL ;
    PORT
      LAYER M5 ;
        RECT  86.4 0 86.424 0.192 ;
    END
  END r_data[65]
  PIN r_data[66]
    DIRECTION INPUT ;
    USE SIGNAL ;
    PORT
      LAYER M5 ;
        RECT  86.496 0 86.52 0.192 ;
    END
  END r_data[66]
  PIN r_data[67]
    DIRECTION INPUT ;
    USE SIGNAL ;
    PORT
      LAYER M5 ;
        RECT  86.592 0 86.616 0.192 ;
    END
  END r_data[67]
  PIN r_data[68]
    DIRECTION INPUT ;
    USE SIGNAL ;
    PORT
      LAYER M5 ;
        RECT  86.688 0 86.712 0.192 ;
    END
  END r_data[68]
  PIN r_data[69]
    DIRECTION INPUT ;
    USE SIGNAL ;
    PORT
      LAYER M5 ;
        RECT  86.784 0 86.808 0.192 ;
    END
  END r_data[69]
  PIN r_data[6]
    DIRECTION INPUT ;
    USE SIGNAL ;
    PORT
      LAYER M5 ;
        RECT  80.736 0 80.76 0.192 ;
    END
  END r_data[6]
  PIN r_data[70]
    DIRECTION INPUT ;
    USE SIGNAL ;
    PORT
      LAYER M5 ;
        RECT  86.88 0 86.904 0.192 ;
    END
  END r_data[70]
  PIN r_data[71]
    DIRECTION INPUT ;
    USE SIGNAL ;
    PORT
      LAYER M5 ;
        RECT  86.976 0 87 0.192 ;
    END
  END r_data[71]
  PIN r_data[72]
    DIRECTION INPUT ;
    USE SIGNAL ;
    PORT
      LAYER M5 ;
        RECT  87.072 0 87.096 0.192 ;
    END
  END r_data[72]
  PIN r_data[73]
    DIRECTION INPUT ;
    USE SIGNAL ;
    PORT
      LAYER M5 ;
        RECT  87.168 0 87.192 0.192 ;
    END
  END r_data[73]
  PIN r_data[74]
    DIRECTION INPUT ;
    USE SIGNAL ;
    PORT
      LAYER M5 ;
        RECT  87.264 0 87.288 0.192 ;
    END
  END r_data[74]
  PIN r_data[75]
    DIRECTION INPUT ;
    USE SIGNAL ;
    PORT
      LAYER M5 ;
        RECT  87.36 0 87.384 0.192 ;
    END
  END r_data[75]
  PIN r_data[76]
    DIRECTION INPUT ;
    USE SIGNAL ;
    PORT
      LAYER M5 ;
        RECT  87.456 0 87.48 0.192 ;
    END
  END r_data[76]
  PIN r_data[77]
    DIRECTION INPUT ;
    USE SIGNAL ;
    PORT
      LAYER M5 ;
        RECT  87.552 0 87.576 0.192 ;
    END
  END r_data[77]
  PIN r_data[78]
    DIRECTION INPUT ;
    USE SIGNAL ;
    PORT
      LAYER M5 ;
        RECT  87.648 0 87.672 0.192 ;
    END
  END r_data[78]
  PIN r_data[79]
    DIRECTION INPUT ;
    USE SIGNAL ;
    PORT
      LAYER M5 ;
        RECT  87.744 0 87.768 0.192 ;
    END
  END r_data[79]
  PIN r_data[7]
    DIRECTION INPUT ;
    USE SIGNAL ;
    PORT
      LAYER M5 ;
        RECT  80.832 0 80.856 0.192 ;
    END
  END r_data[7]
  PIN r_data[80]
    DIRECTION INPUT ;
    USE SIGNAL ;
    PORT
      LAYER M5 ;
        RECT  87.84 0 87.864 0.192 ;
    END
  END r_data[80]
  PIN r_data[81]
    DIRECTION INPUT ;
    USE SIGNAL ;
    PORT
      LAYER M5 ;
        RECT  87.936 0 87.96 0.192 ;
    END
  END r_data[81]
  PIN r_data[82]
    DIRECTION INPUT ;
    USE SIGNAL ;
    PORT
      LAYER M5 ;
        RECT  88.032 0 88.056 0.192 ;
    END
  END r_data[82]
  PIN r_data[83]
    DIRECTION INPUT ;
    USE SIGNAL ;
    PORT
      LAYER M5 ;
        RECT  88.128 0 88.152 0.192 ;
    END
  END r_data[83]
  PIN r_data[84]
    DIRECTION INPUT ;
    USE SIGNAL ;
    PORT
      LAYER M5 ;
        RECT  88.224 0 88.248 0.192 ;
    END
  END r_data[84]
  PIN r_data[85]
    DIRECTION INPUT ;
    USE SIGNAL ;
    PORT
      LAYER M5 ;
        RECT  88.32 0 88.344 0.192 ;
    END
  END r_data[85]
  PIN r_data[86]
    DIRECTION INPUT ;
    USE SIGNAL ;
    PORT
      LAYER M5 ;
        RECT  88.416 0 88.44 0.192 ;
    END
  END r_data[86]
  PIN r_data[87]
    DIRECTION INPUT ;
    USE SIGNAL ;
    PORT
      LAYER M5 ;
        RECT  88.512 0 88.536 0.192 ;
    END
  END r_data[87]
  PIN r_data[88]
    DIRECTION INPUT ;
    USE SIGNAL ;
    PORT
      LAYER M5 ;
        RECT  88.608 0 88.632 0.192 ;
    END
  END r_data[88]
  PIN r_data[89]
    DIRECTION INPUT ;
    USE SIGNAL ;
    PORT
      LAYER M5 ;
        RECT  88.704 0 88.728 0.192 ;
    END
  END r_data[89]
  PIN r_data[8]
    DIRECTION INPUT ;
    USE SIGNAL ;
    PORT
      LAYER M5 ;
        RECT  80.928 0 80.952 0.192 ;
    END
  END r_data[8]
  PIN r_data[90]
    DIRECTION INPUT ;
    USE SIGNAL ;
    PORT
      LAYER M5 ;
        RECT  88.8 0 88.824 0.192 ;
    END
  END r_data[90]
  PIN r_data[91]
    DIRECTION INPUT ;
    USE SIGNAL ;
    PORT
      LAYER M5 ;
        RECT  88.896 0 88.92 0.192 ;
    END
  END r_data[91]
  PIN r_data[92]
    DIRECTION INPUT ;
    USE SIGNAL ;
    PORT
      LAYER M5 ;
        RECT  88.992 0 89.016 0.192 ;
    END
  END r_data[92]
  PIN r_data[93]
    DIRECTION INPUT ;
    USE SIGNAL ;
    PORT
      LAYER M5 ;
        RECT  89.088 0 89.112 0.192 ;
    END
  END r_data[93]
  PIN r_data[94]
    DIRECTION INPUT ;
    USE SIGNAL ;
    PORT
      LAYER M5 ;
        RECT  89.184 0 89.208 0.192 ;
    END
  END r_data[94]
  PIN r_data[95]
    DIRECTION INPUT ;
    USE SIGNAL ;
    PORT
      LAYER M5 ;
        RECT  89.28 0 89.304 0.192 ;
    END
  END r_data[95]
  PIN r_data[96]
    DIRECTION INPUT ;
    USE SIGNAL ;
    PORT
      LAYER M5 ;
        RECT  89.376 0 89.4 0.192 ;
    END
  END r_data[96]
  PIN r_data[97]
    DIRECTION INPUT ;
    USE SIGNAL ;
    PORT
      LAYER M5 ;
        RECT  89.472 0 89.496 0.192 ;
    END
  END r_data[97]
  PIN r_data[98]
    DIRECTION INPUT ;
    USE SIGNAL ;
    PORT
      LAYER M5 ;
        RECT  89.568 0 89.592 0.192 ;
    END
  END r_data[98]
  PIN r_data[99]
    DIRECTION INPUT ;
    USE SIGNAL ;
    PORT
      LAYER M5 ;
        RECT  89.664 0 89.688 0.192 ;
    END
  END r_data[99]
  PIN r_data[9]
    DIRECTION INPUT ;
    USE SIGNAL ;
    PORT
      LAYER M5 ;
        RECT  81.024 0 81.048 0.192 ;
    END
  END r_data[9]
  PIN r_tag[0]
    DIRECTION INPUT ;
    USE SIGNAL ;
    PORT
      LAYER M5 ;
        RECT  104.736 0 104.76 0.192 ;
    END
  END r_tag[0]
  PIN r_tag[10]
    DIRECTION INPUT ;
    USE SIGNAL ;
    PORT
      LAYER M5 ;
        RECT  105.696 0 105.72 0.192 ;
    END
  END r_tag[10]
  PIN r_tag[11]
    DIRECTION INPUT ;
    USE SIGNAL ;
    PORT
      LAYER M5 ;
        RECT  105.792 0 105.816 0.192 ;
    END
  END r_tag[11]
  PIN r_tag[12]
    DIRECTION INPUT ;
    USE SIGNAL ;
    PORT
      LAYER M5 ;
        RECT  105.888 0 105.912 0.192 ;
    END
  END r_tag[12]
  PIN r_tag[13]
    DIRECTION INPUT ;
    USE SIGNAL ;
    PORT
      LAYER M5 ;
        RECT  105.984 0 106.008 0.192 ;
    END
  END r_tag[13]
  PIN r_tag[14]
    DIRECTION INPUT ;
    USE SIGNAL ;
    PORT
      LAYER M5 ;
        RECT  106.08 0 106.104 0.192 ;
    END
  END r_tag[14]
  PIN r_tag[15]
    DIRECTION INPUT ;
    USE SIGNAL ;
    PORT
      LAYER M5 ;
        RECT  106.176 0 106.2 0.192 ;
    END
  END r_tag[15]
  PIN r_tag[16]
    DIRECTION INPUT ;
    USE SIGNAL ;
    PORT
      LAYER M5 ;
        RECT  106.272 0 106.296 0.192 ;
    END
  END r_tag[16]
  PIN r_tag[1]
    DIRECTION INPUT ;
    USE SIGNAL ;
    PORT
      LAYER M5 ;
        RECT  104.832 0 104.856 0.192 ;
    END
  END r_tag[1]
  PIN r_tag[2]
    DIRECTION INPUT ;
    USE SIGNAL ;
    PORT
      LAYER M5 ;
        RECT  104.928 0 104.952 0.192 ;
    END
  END r_tag[2]
  PIN r_tag[3]
    DIRECTION INPUT ;
    USE SIGNAL ;
    PORT
      LAYER M5 ;
        RECT  105.024 0 105.048 0.192 ;
    END
  END r_tag[3]
  PIN r_tag[4]
    DIRECTION INPUT ;
    USE SIGNAL ;
    PORT
      LAYER M5 ;
        RECT  105.12 0 105.144 0.192 ;
    END
  END r_tag[4]
  PIN r_tag[5]
    DIRECTION INPUT ;
    USE SIGNAL ;
    PORT
      LAYER M5 ;
        RECT  105.216 0 105.24 0.192 ;
    END
  END r_tag[5]
  PIN r_tag[6]
    DIRECTION INPUT ;
    USE SIGNAL ;
    PORT
      LAYER M5 ;
        RECT  105.312 0 105.336 0.192 ;
    END
  END r_tag[6]
  PIN r_tag[7]
    DIRECTION INPUT ;
    USE SIGNAL ;
    PORT
      LAYER M5 ;
        RECT  105.408 0 105.432 0.192 ;
    END
  END r_tag[7]
  PIN r_tag[8]
    DIRECTION INPUT ;
    USE SIGNAL ;
    PORT
      LAYER M5 ;
        RECT  105.504 0 105.528 0.192 ;
    END
  END r_tag[8]
  PIN r_tag[9]
    DIRECTION INPUT ;
    USE SIGNAL ;
    PORT
      LAYER M5 ;
        RECT  105.6 0 105.624 0.192 ;
    END
  END r_tag[9]
  PIN rk[0]
    DIRECTION INPUT ;
    USE SIGNAL ;
    PORT
      LAYER M5 ;
        RECT  50.064 0 50.088 0.192 ;
    END
  END rk[0]
  PIN rq[0]
    DIRECTION OUTPUT ;
    USE SIGNAL ;
    PORT
      LAYER M5 ;
        RECT  17.328 0 17.352 0.192 ;
    END
  END rq[0]
  PIN rq[100]
    DIRECTION OUTPUT ;
    USE SIGNAL ;
    PORT
      LAYER M5 ;
        RECT  26.928 0 26.952 0.192 ;
    END
  END rq[100]
  PIN rq[101]
    DIRECTION OUTPUT ;
    USE SIGNAL ;
    PORT
      LAYER M5 ;
        RECT  27.024 0 27.048 0.192 ;
    END
  END rq[101]
  PIN rq[102]
    DIRECTION OUTPUT ;
    USE SIGNAL ;
    PORT
      LAYER M5 ;
        RECT  27.12 0 27.144 0.192 ;
    END
  END rq[102]
  PIN rq[103]
    DIRECTION OUTPUT ;
    USE SIGNAL ;
    PORT
      LAYER M5 ;
        RECT  27.216 0 27.24 0.192 ;
    END
  END rq[103]
  PIN rq[104]
    DIRECTION OUTPUT ;
    USE SIGNAL ;
    PORT
      LAYER M5 ;
        RECT  27.312 0 27.336 0.192 ;
    END
  END rq[104]
  PIN rq[105]
    DIRECTION OUTPUT ;
    USE SIGNAL ;
    PORT
      LAYER M5 ;
        RECT  27.408 0 27.432 0.192 ;
    END
  END rq[105]
  PIN rq[106]
    DIRECTION OUTPUT ;
    USE SIGNAL ;
    PORT
      LAYER M5 ;
        RECT  27.504 0 27.528 0.192 ;
    END
  END rq[106]
  PIN rq[107]
    DIRECTION OUTPUT ;
    USE SIGNAL ;
    PORT
      LAYER M5 ;
        RECT  27.6 0 27.624 0.192 ;
    END
  END rq[107]
  PIN rq[108]
    DIRECTION OUTPUT ;
    USE SIGNAL ;
    PORT
      LAYER M5 ;
        RECT  27.696 0 27.72 0.192 ;
    END
  END rq[108]
  PIN rq[109]
    DIRECTION OUTPUT ;
    USE SIGNAL ;
    PORT
      LAYER M5 ;
        RECT  27.792 0 27.816 0.192 ;
    END
  END rq[109]
  PIN rq[10]
    DIRECTION OUTPUT ;
    USE SIGNAL ;
    PORT
      LAYER M5 ;
        RECT  18.288 0 18.312 0.192 ;
    END
  END rq[10]
  PIN rq[110]
    DIRECTION OUTPUT ;
    USE SIGNAL ;
    PORT
      LAYER M5 ;
        RECT  27.888 0 27.912 0.192 ;
    END
  END rq[110]
  PIN rq[111]
    DIRECTION OUTPUT ;
    USE SIGNAL ;
    PORT
      LAYER M5 ;
        RECT  27.984 0 28.008 0.192 ;
    END
  END rq[111]
  PIN rq[112]
    DIRECTION OUTPUT ;
    USE SIGNAL ;
    PORT
      LAYER M5 ;
        RECT  28.08 0 28.104 0.192 ;
    END
  END rq[112]
  PIN rq[113]
    DIRECTION OUTPUT ;
    USE SIGNAL ;
    PORT
      LAYER M5 ;
        RECT  28.176 0 28.2 0.192 ;
    END
  END rq[113]
  PIN rq[114]
    DIRECTION OUTPUT ;
    USE SIGNAL ;
    PORT
      LAYER M5 ;
        RECT  28.272 0 28.296 0.192 ;
    END
  END rq[114]
  PIN rq[115]
    DIRECTION OUTPUT ;
    USE SIGNAL ;
    PORT
      LAYER M5 ;
        RECT  28.368 0 28.392 0.192 ;
    END
  END rq[115]
  PIN rq[116]
    DIRECTION OUTPUT ;
    USE SIGNAL ;
    PORT
      LAYER M5 ;
        RECT  28.464 0 28.488 0.192 ;
    END
  END rq[116]
  PIN rq[117]
    DIRECTION OUTPUT ;
    USE SIGNAL ;
    PORT
      LAYER M5 ;
        RECT  28.56 0 28.584 0.192 ;
    END
  END rq[117]
  PIN rq[118]
    DIRECTION OUTPUT ;
    USE SIGNAL ;
    PORT
      LAYER M5 ;
        RECT  28.656 0 28.68 0.192 ;
    END
  END rq[118]
  PIN rq[119]
    DIRECTION OUTPUT ;
    USE SIGNAL ;
    PORT
      LAYER M5 ;
        RECT  28.752 0 28.776 0.192 ;
    END
  END rq[119]
  PIN rq[11]
    DIRECTION OUTPUT ;
    USE SIGNAL ;
    PORT
      LAYER M5 ;
        RECT  18.384 0 18.408 0.192 ;
    END
  END rq[11]
  PIN rq[120]
    DIRECTION OUTPUT ;
    USE SIGNAL ;
    PORT
      LAYER M5 ;
        RECT  28.848 0 28.872 0.192 ;
    END
  END rq[120]
  PIN rq[121]
    DIRECTION OUTPUT ;
    USE SIGNAL ;
    PORT
      LAYER M5 ;
        RECT  28.944 0 28.968 0.192 ;
    END
  END rq[121]
  PIN rq[122]
    DIRECTION OUTPUT ;
    USE SIGNAL ;
    PORT
      LAYER M5 ;
        RECT  29.04 0 29.064 0.192 ;
    END
  END rq[122]
  PIN rq[123]
    DIRECTION OUTPUT ;
    USE SIGNAL ;
    PORT
      LAYER M5 ;
        RECT  29.136 0 29.16 0.192 ;
    END
  END rq[123]
  PIN rq[124]
    DIRECTION OUTPUT ;
    USE SIGNAL ;
    PORT
      LAYER M5 ;
        RECT  29.232 0 29.256 0.192 ;
    END
  END rq[124]
  PIN rq[125]
    DIRECTION OUTPUT ;
    USE SIGNAL ;
    PORT
      LAYER M5 ;
        RECT  29.328 0 29.352 0.192 ;
    END
  END rq[125]
  PIN rq[126]
    DIRECTION OUTPUT ;
    USE SIGNAL ;
    PORT
      LAYER M5 ;
        RECT  29.424 0 29.448 0.192 ;
    END
  END rq[126]
  PIN rq[127]
    DIRECTION OUTPUT ;
    USE SIGNAL ;
    PORT
      LAYER M5 ;
        RECT  29.52 0 29.544 0.192 ;
    END
  END rq[127]
  PIN rq[128]
    DIRECTION OUTPUT ;
    USE SIGNAL ;
    PORT
      LAYER M5 ;
        RECT  29.616 0 29.64 0.192 ;
    END
  END rq[128]
  PIN rq[129]
    DIRECTION OUTPUT ;
    USE SIGNAL ;
    PORT
      LAYER M5 ;
        RECT  29.712 0 29.736 0.192 ;
    END
  END rq[129]
  PIN rq[12]
    DIRECTION OUTPUT ;
    USE SIGNAL ;
    PORT
      LAYER M5 ;
        RECT  18.48 0 18.504 0.192 ;
    END
  END rq[12]
  PIN rq[130]
    DIRECTION OUTPUT ;
    USE SIGNAL ;
    PORT
      LAYER M5 ;
        RECT  29.808 0 29.832 0.192 ;
    END
  END rq[130]
  PIN rq[131]
    DIRECTION OUTPUT ;
    USE SIGNAL ;
    PORT
      LAYER M5 ;
        RECT  29.904 0 29.928 0.192 ;
    END
  END rq[131]
  PIN rq[132]
    DIRECTION OUTPUT ;
    USE SIGNAL ;
    PORT
      LAYER M5 ;
        RECT  30 0 30.024 0.192 ;
    END
  END rq[132]
  PIN rq[133]
    DIRECTION OUTPUT ;
    USE SIGNAL ;
    PORT
      LAYER M5 ;
        RECT  30.096 0 30.12 0.192 ;
    END
  END rq[133]
  PIN rq[134]
    DIRECTION OUTPUT ;
    USE SIGNAL ;
    PORT
      LAYER M5 ;
        RECT  30.192 0 30.216 0.192 ;
    END
  END rq[134]
  PIN rq[135]
    DIRECTION OUTPUT ;
    USE SIGNAL ;
    PORT
      LAYER M5 ;
        RECT  30.288 0 30.312 0.192 ;
    END
  END rq[135]
  PIN rq[136]
    DIRECTION OUTPUT ;
    USE SIGNAL ;
    PORT
      LAYER M5 ;
        RECT  30.384 0 30.408 0.192 ;
    END
  END rq[136]
  PIN rq[137]
    DIRECTION OUTPUT ;
    USE SIGNAL ;
    PORT
      LAYER M5 ;
        RECT  30.48 0 30.504 0.192 ;
    END
  END rq[137]
  PIN rq[138]
    DIRECTION OUTPUT ;
    USE SIGNAL ;
    PORT
      LAYER M5 ;
        RECT  30.576 0 30.6 0.192 ;
    END
  END rq[138]
  PIN rq[139]
    DIRECTION OUTPUT ;
    USE SIGNAL ;
    PORT
      LAYER M5 ;
        RECT  30.672 0 30.696 0.192 ;
    END
  END rq[139]
  PIN rq[13]
    DIRECTION OUTPUT ;
    USE SIGNAL ;
    PORT
      LAYER M5 ;
        RECT  18.576 0 18.6 0.192 ;
    END
  END rq[13]
  PIN rq[140]
    DIRECTION OUTPUT ;
    USE SIGNAL ;
    PORT
      LAYER M5 ;
        RECT  30.768 0 30.792 0.192 ;
    END
  END rq[140]
  PIN rq[141]
    DIRECTION OUTPUT ;
    USE SIGNAL ;
    PORT
      LAYER M5 ;
        RECT  30.864 0 30.888 0.192 ;
    END
  END rq[141]
  PIN rq[142]
    DIRECTION OUTPUT ;
    USE SIGNAL ;
    PORT
      LAYER M5 ;
        RECT  30.96 0 30.984 0.192 ;
    END
  END rq[142]
  PIN rq[143]
    DIRECTION OUTPUT ;
    USE SIGNAL ;
    PORT
      LAYER M5 ;
        RECT  31.056 0 31.08 0.192 ;
    END
  END rq[143]
  PIN rq[144]
    DIRECTION OUTPUT ;
    USE SIGNAL ;
    PORT
      LAYER M5 ;
        RECT  31.152 0 31.176 0.192 ;
    END
  END rq[144]
  PIN rq[145]
    DIRECTION OUTPUT ;
    USE SIGNAL ;
    PORT
      LAYER M5 ;
        RECT  31.248 0 31.272 0.192 ;
    END
  END rq[145]
  PIN rq[146]
    DIRECTION OUTPUT ;
    USE SIGNAL ;
    PORT
      LAYER M5 ;
        RECT  31.344 0 31.368 0.192 ;
    END
  END rq[146]
  PIN rq[147]
    DIRECTION OUTPUT ;
    USE SIGNAL ;
    PORT
      LAYER M5 ;
        RECT  31.44 0 31.464 0.192 ;
    END
  END rq[147]
  PIN rq[148]
    DIRECTION OUTPUT ;
    USE SIGNAL ;
    PORT
      LAYER M5 ;
        RECT  31.536 0 31.56 0.192 ;
    END
  END rq[148]
  PIN rq[149]
    DIRECTION OUTPUT ;
    USE SIGNAL ;
    PORT
      LAYER M5 ;
        RECT  31.632 0 31.656 0.192 ;
    END
  END rq[149]
  PIN rq[14]
    DIRECTION OUTPUT ;
    USE SIGNAL ;
    PORT
      LAYER M5 ;
        RECT  18.672 0 18.696 0.192 ;
    END
  END rq[14]
  PIN rq[150]
    DIRECTION OUTPUT ;
    USE SIGNAL ;
    PORT
      LAYER M5 ;
        RECT  31.728 0 31.752 0.192 ;
    END
  END rq[150]
  PIN rq[151]
    DIRECTION OUTPUT ;
    USE SIGNAL ;
    PORT
      LAYER M5 ;
        RECT  31.824 0 31.848 0.192 ;
    END
  END rq[151]
  PIN rq[152]
    DIRECTION OUTPUT ;
    USE SIGNAL ;
    PORT
      LAYER M5 ;
        RECT  31.92 0 31.944 0.192 ;
    END
  END rq[152]
  PIN rq[153]
    DIRECTION OUTPUT ;
    USE SIGNAL ;
    PORT
      LAYER M5 ;
        RECT  32.016 0 32.04 0.192 ;
    END
  END rq[153]
  PIN rq[154]
    DIRECTION OUTPUT ;
    USE SIGNAL ;
    PORT
      LAYER M5 ;
        RECT  32.112 0 32.136 0.192 ;
    END
  END rq[154]
  PIN rq[155]
    DIRECTION OUTPUT ;
    USE SIGNAL ;
    PORT
      LAYER M5 ;
        RECT  32.208 0 32.232 0.192 ;
    END
  END rq[155]
  PIN rq[156]
    DIRECTION OUTPUT ;
    USE SIGNAL ;
    PORT
      LAYER M5 ;
        RECT  32.304 0 32.328 0.192 ;
    END
  END rq[156]
  PIN rq[157]
    DIRECTION OUTPUT ;
    USE SIGNAL ;
    PORT
      LAYER M5 ;
        RECT  32.4 0 32.424 0.192 ;
    END
  END rq[157]
  PIN rq[158]
    DIRECTION OUTPUT ;
    USE SIGNAL ;
    PORT
      LAYER M5 ;
        RECT  32.496 0 32.52 0.192 ;
    END
  END rq[158]
  PIN rq[159]
    DIRECTION OUTPUT ;
    USE SIGNAL ;
    PORT
      LAYER M5 ;
        RECT  32.592 0 32.616 0.192 ;
    END
  END rq[159]
  PIN rq[15]
    DIRECTION OUTPUT ;
    USE SIGNAL ;
    PORT
      LAYER M5 ;
        RECT  18.768 0 18.792 0.192 ;
    END
  END rq[15]
  PIN rq[160]
    DIRECTION OUTPUT ;
    USE SIGNAL ;
    PORT
      LAYER M5 ;
        RECT  32.688 0 32.712 0.192 ;
    END
  END rq[160]
  PIN rq[161]
    DIRECTION OUTPUT ;
    USE SIGNAL ;
    PORT
      LAYER M5 ;
        RECT  32.784 0 32.808 0.192 ;
    END
  END rq[161]
  PIN rq[162]
    DIRECTION OUTPUT ;
    USE SIGNAL ;
    PORT
      LAYER M5 ;
        RECT  32.88 0 32.904 0.192 ;
    END
  END rq[162]
  PIN rq[163]
    DIRECTION OUTPUT ;
    USE SIGNAL ;
    PORT
      LAYER M5 ;
        RECT  32.976 0 33 0.192 ;
    END
  END rq[163]
  PIN rq[164]
    DIRECTION OUTPUT ;
    USE SIGNAL ;
    PORT
      LAYER M5 ;
        RECT  33.072 0 33.096 0.192 ;
    END
  END rq[164]
  PIN rq[165]
    DIRECTION OUTPUT ;
    USE SIGNAL ;
    PORT
      LAYER M5 ;
        RECT  33.168 0 33.192 0.192 ;
    END
  END rq[165]
  PIN rq[166]
    DIRECTION OUTPUT ;
    USE SIGNAL ;
    PORT
      LAYER M5 ;
        RECT  33.264 0 33.288 0.192 ;
    END
  END rq[166]
  PIN rq[167]
    DIRECTION OUTPUT ;
    USE SIGNAL ;
    PORT
      LAYER M5 ;
        RECT  33.36 0 33.384 0.192 ;
    END
  END rq[167]
  PIN rq[168]
    DIRECTION OUTPUT ;
    USE SIGNAL ;
    PORT
      LAYER M5 ;
        RECT  33.456 0 33.48 0.192 ;
    END
  END rq[168]
  PIN rq[169]
    DIRECTION OUTPUT ;
    USE SIGNAL ;
    PORT
      LAYER M5 ;
        RECT  33.552 0 33.576 0.192 ;
    END
  END rq[169]
  PIN rq[16]
    DIRECTION OUTPUT ;
    USE SIGNAL ;
    PORT
      LAYER M5 ;
        RECT  18.864 0 18.888 0.192 ;
    END
  END rq[16]
  PIN rq[170]
    DIRECTION OUTPUT ;
    USE SIGNAL ;
    PORT
      LAYER M5 ;
        RECT  33.648 0 33.672 0.192 ;
    END
  END rq[170]
  PIN rq[171]
    DIRECTION OUTPUT ;
    USE SIGNAL ;
    PORT
      LAYER M5 ;
        RECT  33.744 0 33.768 0.192 ;
    END
  END rq[171]
  PIN rq[172]
    DIRECTION OUTPUT ;
    USE SIGNAL ;
    PORT
      LAYER M5 ;
        RECT  33.84 0 33.864 0.192 ;
    END
  END rq[172]
  PIN rq[173]
    DIRECTION OUTPUT ;
    USE SIGNAL ;
    PORT
      LAYER M5 ;
        RECT  33.936 0 33.96 0.192 ;
    END
  END rq[173]
  PIN rq[174]
    DIRECTION OUTPUT ;
    USE SIGNAL ;
    PORT
      LAYER M5 ;
        RECT  34.032 0 34.056 0.192 ;
    END
  END rq[174]
  PIN rq[175]
    DIRECTION OUTPUT ;
    USE SIGNAL ;
    PORT
      LAYER M5 ;
        RECT  34.128 0 34.152 0.192 ;
    END
  END rq[175]
  PIN rq[176]
    DIRECTION OUTPUT ;
    USE SIGNAL ;
    PORT
      LAYER M5 ;
        RECT  34.224 0 34.248 0.192 ;
    END
  END rq[176]
  PIN rq[177]
    DIRECTION OUTPUT ;
    USE SIGNAL ;
    PORT
      LAYER M5 ;
        RECT  34.32 0 34.344 0.192 ;
    END
  END rq[177]
  PIN rq[178]
    DIRECTION OUTPUT ;
    USE SIGNAL ;
    PORT
      LAYER M5 ;
        RECT  34.416 0 34.44 0.192 ;
    END
  END rq[178]
  PIN rq[179]
    DIRECTION OUTPUT ;
    USE SIGNAL ;
    PORT
      LAYER M5 ;
        RECT  34.512 0 34.536 0.192 ;
    END
  END rq[179]
  PIN rq[17]
    DIRECTION OUTPUT ;
    USE SIGNAL ;
    PORT
      LAYER M5 ;
        RECT  18.96 0 18.984 0.192 ;
    END
  END rq[17]
  PIN rq[180]
    DIRECTION OUTPUT ;
    USE SIGNAL ;
    PORT
      LAYER M5 ;
        RECT  34.608 0 34.632 0.192 ;
    END
  END rq[180]
  PIN rq[181]
    DIRECTION OUTPUT ;
    USE SIGNAL ;
    PORT
      LAYER M5 ;
        RECT  34.704 0 34.728 0.192 ;
    END
  END rq[181]
  PIN rq[182]
    DIRECTION OUTPUT ;
    USE SIGNAL ;
    PORT
      LAYER M5 ;
        RECT  34.8 0 34.824 0.192 ;
    END
  END rq[182]
  PIN rq[183]
    DIRECTION OUTPUT ;
    USE SIGNAL ;
    PORT
      LAYER M5 ;
        RECT  34.896 0 34.92 0.192 ;
    END
  END rq[183]
  PIN rq[184]
    DIRECTION OUTPUT ;
    USE SIGNAL ;
    PORT
      LAYER M5 ;
        RECT  34.992 0 35.016 0.192 ;
    END
  END rq[184]
  PIN rq[185]
    DIRECTION OUTPUT ;
    USE SIGNAL ;
    PORT
      LAYER M5 ;
        RECT  35.088 0 35.112 0.192 ;
    END
  END rq[185]
  PIN rq[186]
    DIRECTION OUTPUT ;
    USE SIGNAL ;
    PORT
      LAYER M5 ;
        RECT  35.184 0 35.208 0.192 ;
    END
  END rq[186]
  PIN rq[187]
    DIRECTION OUTPUT ;
    USE SIGNAL ;
    PORT
      LAYER M5 ;
        RECT  35.28 0 35.304 0.192 ;
    END
  END rq[187]
  PIN rq[188]
    DIRECTION OUTPUT ;
    USE SIGNAL ;
    PORT
      LAYER M5 ;
        RECT  35.376 0 35.4 0.192 ;
    END
  END rq[188]
  PIN rq[189]
    DIRECTION OUTPUT ;
    USE SIGNAL ;
    PORT
      LAYER M5 ;
        RECT  35.472 0 35.496 0.192 ;
    END
  END rq[189]
  PIN rq[18]
    DIRECTION OUTPUT ;
    USE SIGNAL ;
    PORT
      LAYER M5 ;
        RECT  19.056 0 19.08 0.192 ;
    END
  END rq[18]
  PIN rq[190]
    DIRECTION OUTPUT ;
    USE SIGNAL ;
    PORT
      LAYER M5 ;
        RECT  35.568 0 35.592 0.192 ;
    END
  END rq[190]
  PIN rq[191]
    DIRECTION OUTPUT ;
    USE SIGNAL ;
    PORT
      LAYER M5 ;
        RECT  35.664 0 35.688 0.192 ;
    END
  END rq[191]
  PIN rq[192]
    DIRECTION OUTPUT ;
    USE SIGNAL ;
    PORT
      LAYER M5 ;
        RECT  35.76 0 35.784 0.192 ;
    END
  END rq[192]
  PIN rq[193]
    DIRECTION OUTPUT ;
    USE SIGNAL ;
    PORT
      LAYER M5 ;
        RECT  35.856 0 35.88 0.192 ;
    END
  END rq[193]
  PIN rq[194]
    DIRECTION OUTPUT ;
    USE SIGNAL ;
    PORT
      LAYER M5 ;
        RECT  35.952 0 35.976 0.192 ;
    END
  END rq[194]
  PIN rq[195]
    DIRECTION OUTPUT ;
    USE SIGNAL ;
    PORT
      LAYER M5 ;
        RECT  36.048 0 36.072 0.192 ;
    END
  END rq[195]
  PIN rq[196]
    DIRECTION OUTPUT ;
    USE SIGNAL ;
    PORT
      LAYER M5 ;
        RECT  36.144 0 36.168 0.192 ;
    END
  END rq[196]
  PIN rq[197]
    DIRECTION OUTPUT ;
    USE SIGNAL ;
    PORT
      LAYER M5 ;
        RECT  36.24 0 36.264 0.192 ;
    END
  END rq[197]
  PIN rq[198]
    DIRECTION OUTPUT ;
    USE SIGNAL ;
    PORT
      LAYER M5 ;
        RECT  36.336 0 36.36 0.192 ;
    END
  END rq[198]
  PIN rq[199]
    DIRECTION OUTPUT ;
    USE SIGNAL ;
    PORT
      LAYER M5 ;
        RECT  36.432 0 36.456 0.192 ;
    END
  END rq[199]
  PIN rq[19]
    DIRECTION OUTPUT ;
    USE SIGNAL ;
    PORT
      LAYER M5 ;
        RECT  19.152 0 19.176 0.192 ;
    END
  END rq[19]
  PIN rq[1]
    DIRECTION OUTPUT ;
    USE SIGNAL ;
    PORT
      LAYER M5 ;
        RECT  17.424 0 17.448 0.192 ;
    END
  END rq[1]
  PIN rq[200]
    DIRECTION OUTPUT ;
    USE SIGNAL ;
    PORT
      LAYER M5 ;
        RECT  36.528 0 36.552 0.192 ;
    END
  END rq[200]
  PIN rq[201]
    DIRECTION OUTPUT ;
    USE SIGNAL ;
    PORT
      LAYER M5 ;
        RECT  36.624 0 36.648 0.192 ;
    END
  END rq[201]
  PIN rq[202]
    DIRECTION OUTPUT ;
    USE SIGNAL ;
    PORT
      LAYER M5 ;
        RECT  36.72 0 36.744 0.192 ;
    END
  END rq[202]
  PIN rq[203]
    DIRECTION OUTPUT ;
    USE SIGNAL ;
    PORT
      LAYER M5 ;
        RECT  36.816 0 36.84 0.192 ;
    END
  END rq[203]
  PIN rq[204]
    DIRECTION OUTPUT ;
    USE SIGNAL ;
    PORT
      LAYER M5 ;
        RECT  36.912 0 36.936 0.192 ;
    END
  END rq[204]
  PIN rq[205]
    DIRECTION OUTPUT ;
    USE SIGNAL ;
    PORT
      LAYER M5 ;
        RECT  37.008 0 37.032 0.192 ;
    END
  END rq[205]
  PIN rq[206]
    DIRECTION OUTPUT ;
    USE SIGNAL ;
    PORT
      LAYER M5 ;
        RECT  37.104 0 37.128 0.192 ;
    END
  END rq[206]
  PIN rq[207]
    DIRECTION OUTPUT ;
    USE SIGNAL ;
    PORT
      LAYER M5 ;
        RECT  37.2 0 37.224 0.192 ;
    END
  END rq[207]
  PIN rq[208]
    DIRECTION OUTPUT ;
    USE SIGNAL ;
    PORT
      LAYER M5 ;
        RECT  37.296 0 37.32 0.192 ;
    END
  END rq[208]
  PIN rq[209]
    DIRECTION OUTPUT ;
    USE SIGNAL ;
    PORT
      LAYER M5 ;
        RECT  37.392 0 37.416 0.192 ;
    END
  END rq[209]
  PIN rq[20]
    DIRECTION OUTPUT ;
    USE SIGNAL ;
    PORT
      LAYER M5 ;
        RECT  19.248 0 19.272 0.192 ;
    END
  END rq[20]
  PIN rq[210]
    DIRECTION OUTPUT ;
    USE SIGNAL ;
    PORT
      LAYER M5 ;
        RECT  37.488 0 37.512 0.192 ;
    END
  END rq[210]
  PIN rq[211]
    DIRECTION OUTPUT ;
    USE SIGNAL ;
    PORT
      LAYER M5 ;
        RECT  37.584 0 37.608 0.192 ;
    END
  END rq[211]
  PIN rq[212]
    DIRECTION OUTPUT ;
    USE SIGNAL ;
    PORT
      LAYER M5 ;
        RECT  37.68 0 37.704 0.192 ;
    END
  END rq[212]
  PIN rq[213]
    DIRECTION OUTPUT ;
    USE SIGNAL ;
    PORT
      LAYER M5 ;
        RECT  37.776 0 37.8 0.192 ;
    END
  END rq[213]
  PIN rq[214]
    DIRECTION OUTPUT ;
    USE SIGNAL ;
    PORT
      LAYER M5 ;
        RECT  37.872 0 37.896 0.192 ;
    END
  END rq[214]
  PIN rq[215]
    DIRECTION OUTPUT ;
    USE SIGNAL ;
    PORT
      LAYER M5 ;
        RECT  37.968 0 37.992 0.192 ;
    END
  END rq[215]
  PIN rq[216]
    DIRECTION OUTPUT ;
    USE SIGNAL ;
    PORT
      LAYER M5 ;
        RECT  38.064 0 38.088 0.192 ;
    END
  END rq[216]
  PIN rq[217]
    DIRECTION OUTPUT ;
    USE SIGNAL ;
    PORT
      LAYER M5 ;
        RECT  38.16 0 38.184 0.192 ;
    END
  END rq[217]
  PIN rq[218]
    DIRECTION OUTPUT ;
    USE SIGNAL ;
    PORT
      LAYER M5 ;
        RECT  38.256 0 38.28 0.192 ;
    END
  END rq[218]
  PIN rq[219]
    DIRECTION OUTPUT ;
    USE SIGNAL ;
    PORT
      LAYER M5 ;
        RECT  38.352 0 38.376 0.192 ;
    END
  END rq[219]
  PIN rq[21]
    DIRECTION OUTPUT ;
    USE SIGNAL ;
    PORT
      LAYER M5 ;
        RECT  19.344 0 19.368 0.192 ;
    END
  END rq[21]
  PIN rq[220]
    DIRECTION OUTPUT ;
    USE SIGNAL ;
    PORT
      LAYER M5 ;
        RECT  38.448 0 38.472 0.192 ;
    END
  END rq[220]
  PIN rq[221]
    DIRECTION OUTPUT ;
    USE SIGNAL ;
    PORT
      LAYER M5 ;
        RECT  38.544 0 38.568 0.192 ;
    END
  END rq[221]
  PIN rq[222]
    DIRECTION OUTPUT ;
    USE SIGNAL ;
    PORT
      LAYER M5 ;
        RECT  38.64 0 38.664 0.192 ;
    END
  END rq[222]
  PIN rq[223]
    DIRECTION OUTPUT ;
    USE SIGNAL ;
    PORT
      LAYER M5 ;
        RECT  38.736 0 38.76 0.192 ;
    END
  END rq[223]
  PIN rq[224]
    DIRECTION OUTPUT ;
    USE SIGNAL ;
    PORT
      LAYER M5 ;
        RECT  38.832 0 38.856 0.192 ;
    END
  END rq[224]
  PIN rq[225]
    DIRECTION OUTPUT ;
    USE SIGNAL ;
    PORT
      LAYER M5 ;
        RECT  38.928 0 38.952 0.192 ;
    END
  END rq[225]
  PIN rq[226]
    DIRECTION OUTPUT ;
    USE SIGNAL ;
    PORT
      LAYER M5 ;
        RECT  39.024 0 39.048 0.192 ;
    END
  END rq[226]
  PIN rq[227]
    DIRECTION OUTPUT ;
    USE SIGNAL ;
    PORT
      LAYER M5 ;
        RECT  39.12 0 39.144 0.192 ;
    END
  END rq[227]
  PIN rq[228]
    DIRECTION OUTPUT ;
    USE SIGNAL ;
    PORT
      LAYER M5 ;
        RECT  39.216 0 39.24 0.192 ;
    END
  END rq[228]
  PIN rq[229]
    DIRECTION OUTPUT ;
    USE SIGNAL ;
    PORT
      LAYER M5 ;
        RECT  39.312 0 39.336 0.192 ;
    END
  END rq[229]
  PIN rq[22]
    DIRECTION OUTPUT ;
    USE SIGNAL ;
    PORT
      LAYER M5 ;
        RECT  19.44 0 19.464 0.192 ;
    END
  END rq[22]
  PIN rq[230]
    DIRECTION OUTPUT ;
    USE SIGNAL ;
    PORT
      LAYER M5 ;
        RECT  39.408 0 39.432 0.192 ;
    END
  END rq[230]
  PIN rq[231]
    DIRECTION OUTPUT ;
    USE SIGNAL ;
    PORT
      LAYER M5 ;
        RECT  39.504 0 39.528 0.192 ;
    END
  END rq[231]
  PIN rq[232]
    DIRECTION OUTPUT ;
    USE SIGNAL ;
    PORT
      LAYER M5 ;
        RECT  39.6 0 39.624 0.192 ;
    END
  END rq[232]
  PIN rq[233]
    DIRECTION OUTPUT ;
    USE SIGNAL ;
    PORT
      LAYER M5 ;
        RECT  39.696 0 39.72 0.192 ;
    END
  END rq[233]
  PIN rq[234]
    DIRECTION OUTPUT ;
    USE SIGNAL ;
    PORT
      LAYER M5 ;
        RECT  39.792 0 39.816 0.192 ;
    END
  END rq[234]
  PIN rq[235]
    DIRECTION OUTPUT ;
    USE SIGNAL ;
    PORT
      LAYER M5 ;
        RECT  39.888 0 39.912 0.192 ;
    END
  END rq[235]
  PIN rq[236]
    DIRECTION OUTPUT ;
    USE SIGNAL ;
    PORT
      LAYER M5 ;
        RECT  39.984 0 40.008 0.192 ;
    END
  END rq[236]
  PIN rq[237]
    DIRECTION OUTPUT ;
    USE SIGNAL ;
    PORT
      LAYER M5 ;
        RECT  40.08 0 40.104 0.192 ;
    END
  END rq[237]
  PIN rq[238]
    DIRECTION OUTPUT ;
    USE SIGNAL ;
    PORT
      LAYER M5 ;
        RECT  40.176 0 40.2 0.192 ;
    END
  END rq[238]
  PIN rq[239]
    DIRECTION OUTPUT ;
    USE SIGNAL ;
    PORT
      LAYER M5 ;
        RECT  40.272 0 40.296 0.192 ;
    END
  END rq[239]
  PIN rq[23]
    DIRECTION OUTPUT ;
    USE SIGNAL ;
    PORT
      LAYER M5 ;
        RECT  19.536 0 19.56 0.192 ;
    END
  END rq[23]
  PIN rq[240]
    DIRECTION OUTPUT ;
    USE SIGNAL ;
    PORT
      LAYER M5 ;
        RECT  40.368 0 40.392 0.192 ;
    END
  END rq[240]
  PIN rq[241]
    DIRECTION OUTPUT ;
    USE SIGNAL ;
    PORT
      LAYER M5 ;
        RECT  40.464 0 40.488 0.192 ;
    END
  END rq[241]
  PIN rq[242]
    DIRECTION OUTPUT ;
    USE SIGNAL ;
    PORT
      LAYER M5 ;
        RECT  40.56 0 40.584 0.192 ;
    END
  END rq[242]
  PIN rq[243]
    DIRECTION OUTPUT ;
    USE SIGNAL ;
    PORT
      LAYER M5 ;
        RECT  40.656 0 40.68 0.192 ;
    END
  END rq[243]
  PIN rq[244]
    DIRECTION OUTPUT ;
    USE SIGNAL ;
    PORT
      LAYER M5 ;
        RECT  40.752 0 40.776 0.192 ;
    END
  END rq[244]
  PIN rq[245]
    DIRECTION OUTPUT ;
    USE SIGNAL ;
    PORT
      LAYER M5 ;
        RECT  40.848 0 40.872 0.192 ;
    END
  END rq[245]
  PIN rq[246]
    DIRECTION OUTPUT ;
    USE SIGNAL ;
    PORT
      LAYER M5 ;
        RECT  40.944 0 40.968 0.192 ;
    END
  END rq[246]
  PIN rq[247]
    DIRECTION OUTPUT ;
    USE SIGNAL ;
    PORT
      LAYER M5 ;
        RECT  41.04 0 41.064 0.192 ;
    END
  END rq[247]
  PIN rq[248]
    DIRECTION OUTPUT ;
    USE SIGNAL ;
    PORT
      LAYER M5 ;
        RECT  41.136 0 41.16 0.192 ;
    END
  END rq[248]
  PIN rq[249]
    DIRECTION OUTPUT ;
    USE SIGNAL ;
    PORT
      LAYER M5 ;
        RECT  41.232 0 41.256 0.192 ;
    END
  END rq[249]
  PIN rq[24]
    DIRECTION OUTPUT ;
    USE SIGNAL ;
    PORT
      LAYER M5 ;
        RECT  19.632 0 19.656 0.192 ;
    END
  END rq[24]
  PIN rq[250]
    DIRECTION OUTPUT ;
    USE SIGNAL ;
    PORT
      LAYER M5 ;
        RECT  41.328 0 41.352 0.192 ;
    END
  END rq[250]
  PIN rq[251]
    DIRECTION OUTPUT ;
    USE SIGNAL ;
    PORT
      LAYER M5 ;
        RECT  41.424 0 41.448 0.192 ;
    END
  END rq[251]
  PIN rq[252]
    DIRECTION OUTPUT ;
    USE SIGNAL ;
    PORT
      LAYER M5 ;
        RECT  41.52 0 41.544 0.192 ;
    END
  END rq[252]
  PIN rq[253]
    DIRECTION OUTPUT ;
    USE SIGNAL ;
    PORT
      LAYER M5 ;
        RECT  41.616 0 41.64 0.192 ;
    END
  END rq[253]
  PIN rq[254]
    DIRECTION OUTPUT ;
    USE SIGNAL ;
    PORT
      LAYER M5 ;
        RECT  41.712 0 41.736 0.192 ;
    END
  END rq[254]
  PIN rq[255]
    DIRECTION OUTPUT ;
    USE SIGNAL ;
    PORT
      LAYER M5 ;
        RECT  41.808 0 41.832 0.192 ;
    END
  END rq[255]
  PIN rq[256]
    DIRECTION OUTPUT ;
    USE SIGNAL ;
    PORT
      LAYER M5 ;
        RECT  41.904 0 41.928 0.192 ;
    END
  END rq[256]
  PIN rq[257]
    DIRECTION OUTPUT ;
    USE SIGNAL ;
    PORT
      LAYER M5 ;
        RECT  42 0 42.024 0.192 ;
    END
  END rq[257]
  PIN rq[258]
    DIRECTION OUTPUT ;
    USE SIGNAL ;
    PORT
      LAYER M5 ;
        RECT  42.096 0 42.12 0.192 ;
    END
  END rq[258]
  PIN rq[259]
    DIRECTION OUTPUT ;
    USE SIGNAL ;
    PORT
      LAYER M5 ;
        RECT  42.192 0 42.216 0.192 ;
    END
  END rq[259]
  PIN rq[25]
    DIRECTION OUTPUT ;
    USE SIGNAL ;
    PORT
      LAYER M5 ;
        RECT  19.728 0 19.752 0.192 ;
    END
  END rq[25]
  PIN rq[260]
    DIRECTION OUTPUT ;
    USE SIGNAL ;
    PORT
      LAYER M5 ;
        RECT  42.288 0 42.312 0.192 ;
    END
  END rq[260]
  PIN rq[261]
    DIRECTION OUTPUT ;
    USE SIGNAL ;
    PORT
      LAYER M5 ;
        RECT  42.384 0 42.408 0.192 ;
    END
  END rq[261]
  PIN rq[262]
    DIRECTION OUTPUT ;
    USE SIGNAL ;
    PORT
      LAYER M5 ;
        RECT  42.48 0 42.504 0.192 ;
    END
  END rq[262]
  PIN rq[263]
    DIRECTION OUTPUT ;
    USE SIGNAL ;
    PORT
      LAYER M5 ;
        RECT  42.576 0 42.6 0.192 ;
    END
  END rq[263]
  PIN rq[264]
    DIRECTION OUTPUT ;
    USE SIGNAL ;
    PORT
      LAYER M5 ;
        RECT  42.672 0 42.696 0.192 ;
    END
  END rq[264]
  PIN rq[265]
    DIRECTION OUTPUT ;
    USE SIGNAL ;
    PORT
      LAYER M5 ;
        RECT  42.768 0 42.792 0.192 ;
    END
  END rq[265]
  PIN rq[266]
    DIRECTION OUTPUT ;
    USE SIGNAL ;
    PORT
      LAYER M5 ;
        RECT  42.864 0 42.888 0.192 ;
    END
  END rq[266]
  PIN rq[267]
    DIRECTION OUTPUT ;
    USE SIGNAL ;
    PORT
      LAYER M5 ;
        RECT  42.96 0 42.984 0.192 ;
    END
  END rq[267]
  PIN rq[268]
    DIRECTION OUTPUT ;
    USE SIGNAL ;
    PORT
      LAYER M5 ;
        RECT  43.056 0 43.08 0.192 ;
    END
  END rq[268]
  PIN rq[269]
    DIRECTION OUTPUT ;
    USE SIGNAL ;
    PORT
      LAYER M5 ;
        RECT  43.152 0 43.176 0.192 ;
    END
  END rq[269]
  PIN rq[26]
    DIRECTION OUTPUT ;
    USE SIGNAL ;
    PORT
      LAYER M5 ;
        RECT  19.824 0 19.848 0.192 ;
    END
  END rq[26]
  PIN rq[270]
    DIRECTION OUTPUT ;
    USE SIGNAL ;
    PORT
      LAYER M5 ;
        RECT  43.248 0 43.272 0.192 ;
    END
  END rq[270]
  PIN rq[271]
    DIRECTION OUTPUT ;
    USE SIGNAL ;
    PORT
      LAYER M5 ;
        RECT  43.344 0 43.368 0.192 ;
    END
  END rq[271]
  PIN rq[272]
    DIRECTION OUTPUT ;
    USE SIGNAL ;
    PORT
      LAYER M5 ;
        RECT  43.44 0 43.464 0.192 ;
    END
  END rq[272]
  PIN rq[273]
    DIRECTION OUTPUT ;
    USE SIGNAL ;
    PORT
      LAYER M5 ;
        RECT  43.536 0 43.56 0.192 ;
    END
  END rq[273]
  PIN rq[274]
    DIRECTION OUTPUT ;
    USE SIGNAL ;
    PORT
      LAYER M5 ;
        RECT  43.632 0 43.656 0.192 ;
    END
  END rq[274]
  PIN rq[275]
    DIRECTION OUTPUT ;
    USE SIGNAL ;
    PORT
      LAYER M5 ;
        RECT  43.728 0 43.752 0.192 ;
    END
  END rq[275]
  PIN rq[276]
    DIRECTION OUTPUT ;
    USE SIGNAL ;
    PORT
      LAYER M5 ;
        RECT  43.824 0 43.848 0.192 ;
    END
  END rq[276]
  PIN rq[277]
    DIRECTION OUTPUT ;
    USE SIGNAL ;
    PORT
      LAYER M5 ;
        RECT  43.92 0 43.944 0.192 ;
    END
  END rq[277]
  PIN rq[278]
    DIRECTION OUTPUT ;
    USE SIGNAL ;
    PORT
      LAYER M5 ;
        RECT  44.016 0 44.04 0.192 ;
    END
  END rq[278]
  PIN rq[279]
    DIRECTION OUTPUT ;
    USE SIGNAL ;
    PORT
      LAYER M5 ;
        RECT  44.112 0 44.136 0.192 ;
    END
  END rq[279]
  PIN rq[27]
    DIRECTION OUTPUT ;
    USE SIGNAL ;
    PORT
      LAYER M5 ;
        RECT  19.92 0 19.944 0.192 ;
    END
  END rq[27]
  PIN rq[280]
    DIRECTION OUTPUT ;
    USE SIGNAL ;
    PORT
      LAYER M5 ;
        RECT  44.208 0 44.232 0.192 ;
    END
  END rq[280]
  PIN rq[281]
    DIRECTION OUTPUT ;
    USE SIGNAL ;
    PORT
      LAYER M5 ;
        RECT  44.304 0 44.328 0.192 ;
    END
  END rq[281]
  PIN rq[282]
    DIRECTION OUTPUT ;
    USE SIGNAL ;
    PORT
      LAYER M5 ;
        RECT  44.4 0 44.424 0.192 ;
    END
  END rq[282]
  PIN rq[283]
    DIRECTION OUTPUT ;
    USE SIGNAL ;
    PORT
      LAYER M5 ;
        RECT  44.496 0 44.52 0.192 ;
    END
  END rq[283]
  PIN rq[284]
    DIRECTION OUTPUT ;
    USE SIGNAL ;
    PORT
      LAYER M5 ;
        RECT  44.592 0 44.616 0.192 ;
    END
  END rq[284]
  PIN rq[285]
    DIRECTION OUTPUT ;
    USE SIGNAL ;
    PORT
      LAYER M5 ;
        RECT  44.688 0 44.712 0.192 ;
    END
  END rq[285]
  PIN rq[286]
    DIRECTION OUTPUT ;
    USE SIGNAL ;
    PORT
      LAYER M5 ;
        RECT  44.784 0 44.808 0.192 ;
    END
  END rq[286]
  PIN rq[287]
    DIRECTION OUTPUT ;
    USE SIGNAL ;
    PORT
      LAYER M5 ;
        RECT  44.88 0 44.904 0.192 ;
    END
  END rq[287]
  PIN rq[288]
    DIRECTION OUTPUT ;
    USE SIGNAL ;
    PORT
      LAYER M5 ;
        RECT  44.976 0 45 0.192 ;
    END
  END rq[288]
  PIN rq[289]
    DIRECTION OUTPUT ;
    USE SIGNAL ;
    PORT
      LAYER M5 ;
        RECT  45.072 0 45.096 0.192 ;
    END
  END rq[289]
  PIN rq[28]
    DIRECTION OUTPUT ;
    USE SIGNAL ;
    PORT
      LAYER M5 ;
        RECT  20.016 0 20.04 0.192 ;
    END
  END rq[28]
  PIN rq[290]
    DIRECTION OUTPUT ;
    USE SIGNAL ;
    PORT
      LAYER M5 ;
        RECT  45.168 0 45.192 0.192 ;
    END
  END rq[290]
  PIN rq[291]
    DIRECTION OUTPUT ;
    USE SIGNAL ;
    PORT
      LAYER M5 ;
        RECT  45.264 0 45.288 0.192 ;
    END
  END rq[291]
  PIN rq[292]
    DIRECTION OUTPUT ;
    USE SIGNAL ;
    PORT
      LAYER M5 ;
        RECT  45.36 0 45.384 0.192 ;
    END
  END rq[292]
  PIN rq[293]
    DIRECTION OUTPUT ;
    USE SIGNAL ;
    PORT
      LAYER M5 ;
        RECT  45.456 0 45.48 0.192 ;
    END
  END rq[293]
  PIN rq[294]
    DIRECTION OUTPUT ;
    USE SIGNAL ;
    PORT
      LAYER M5 ;
        RECT  45.552 0 45.576 0.192 ;
    END
  END rq[294]
  PIN rq[295]
    DIRECTION OUTPUT ;
    USE SIGNAL ;
    PORT
      LAYER M5 ;
        RECT  45.648 0 45.672 0.192 ;
    END
  END rq[295]
  PIN rq[296]
    DIRECTION OUTPUT ;
    USE SIGNAL ;
    PORT
      LAYER M5 ;
        RECT  45.744 0 45.768 0.192 ;
    END
  END rq[296]
  PIN rq[297]
    DIRECTION OUTPUT ;
    USE SIGNAL ;
    PORT
      LAYER M5 ;
        RECT  45.84 0 45.864 0.192 ;
    END
  END rq[297]
  PIN rq[298]
    DIRECTION OUTPUT ;
    USE SIGNAL ;
    PORT
      LAYER M5 ;
        RECT  45.936 0 45.96 0.192 ;
    END
  END rq[298]
  PIN rq[299]
    DIRECTION OUTPUT ;
    USE SIGNAL ;
    PORT
      LAYER M5 ;
        RECT  46.032 0 46.056 0.192 ;
    END
  END rq[299]
  PIN rq[29]
    DIRECTION OUTPUT ;
    USE SIGNAL ;
    PORT
      LAYER M5 ;
        RECT  20.112 0 20.136 0.192 ;
    END
  END rq[29]
  PIN rq[2]
    DIRECTION OUTPUT ;
    USE SIGNAL ;
    PORT
      LAYER M5 ;
        RECT  17.52 0 17.544 0.192 ;
    END
  END rq[2]
  PIN rq[300]
    DIRECTION OUTPUT ;
    USE SIGNAL ;
    PORT
      LAYER M5 ;
        RECT  46.128 0 46.152 0.192 ;
    END
  END rq[300]
  PIN rq[301]
    DIRECTION OUTPUT ;
    USE SIGNAL ;
    PORT
      LAYER M5 ;
        RECT  46.224 0 46.248 0.192 ;
    END
  END rq[301]
  PIN rq[302]
    DIRECTION OUTPUT ;
    USE SIGNAL ;
    PORT
      LAYER M5 ;
        RECT  46.32 0 46.344 0.192 ;
    END
  END rq[302]
  PIN rq[303]
    DIRECTION OUTPUT ;
    USE SIGNAL ;
    PORT
      LAYER M5 ;
        RECT  46.416 0 46.44 0.192 ;
    END
  END rq[303]
  PIN rq[304]
    DIRECTION OUTPUT ;
    USE SIGNAL ;
    PORT
      LAYER M5 ;
        RECT  46.512 0 46.536 0.192 ;
    END
  END rq[304]
  PIN rq[305]
    DIRECTION OUTPUT ;
    USE SIGNAL ;
    PORT
      LAYER M5 ;
        RECT  46.608 0 46.632 0.192 ;
    END
  END rq[305]
  PIN rq[306]
    DIRECTION OUTPUT ;
    USE SIGNAL ;
    PORT
      LAYER M5 ;
        RECT  46.704 0 46.728 0.192 ;
    END
  END rq[306]
  PIN rq[307]
    DIRECTION OUTPUT ;
    USE SIGNAL ;
    PORT
      LAYER M5 ;
        RECT  46.8 0 46.824 0.192 ;
    END
  END rq[307]
  PIN rq[308]
    DIRECTION OUTPUT ;
    USE SIGNAL ;
    PORT
      LAYER M5 ;
        RECT  46.896 0 46.92 0.192 ;
    END
  END rq[308]
  PIN rq[309]
    DIRECTION OUTPUT ;
    USE SIGNAL ;
    PORT
      LAYER M5 ;
        RECT  46.992 0 47.016 0.192 ;
    END
  END rq[309]
  PIN rq[30]
    DIRECTION OUTPUT ;
    USE SIGNAL ;
    PORT
      LAYER M5 ;
        RECT  20.208 0 20.232 0.192 ;
    END
  END rq[30]
  PIN rq[310]
    DIRECTION OUTPUT ;
    USE SIGNAL ;
    PORT
      LAYER M5 ;
        RECT  47.088 0 47.112 0.192 ;
    END
  END rq[310]
  PIN rq[311]
    DIRECTION OUTPUT ;
    USE SIGNAL ;
    PORT
      LAYER M5 ;
        RECT  47.184 0 47.208 0.192 ;
    END
  END rq[311]
  PIN rq[312]
    DIRECTION OUTPUT ;
    USE SIGNAL ;
    PORT
      LAYER M5 ;
        RECT  47.28 0 47.304 0.192 ;
    END
  END rq[312]
  PIN rq[313]
    DIRECTION OUTPUT ;
    USE SIGNAL ;
    PORT
      LAYER M5 ;
        RECT  47.376 0 47.4 0.192 ;
    END
  END rq[313]
  PIN rq[314]
    DIRECTION OUTPUT ;
    USE SIGNAL ;
    PORT
      LAYER M5 ;
        RECT  47.472 0 47.496 0.192 ;
    END
  END rq[314]
  PIN rq[315]
    DIRECTION OUTPUT ;
    USE SIGNAL ;
    PORT
      LAYER M5 ;
        RECT  47.568 0 47.592 0.192 ;
    END
  END rq[315]
  PIN rq[316]
    DIRECTION OUTPUT ;
    USE SIGNAL ;
    PORT
      LAYER M5 ;
        RECT  47.664 0 47.688 0.192 ;
    END
  END rq[316]
  PIN rq[317]
    DIRECTION OUTPUT ;
    USE SIGNAL ;
    PORT
      LAYER M5 ;
        RECT  47.76 0 47.784 0.192 ;
    END
  END rq[317]
  PIN rq[318]
    DIRECTION OUTPUT ;
    USE SIGNAL ;
    PORT
      LAYER M5 ;
        RECT  47.856 0 47.88 0.192 ;
    END
  END rq[318]
  PIN rq[319]
    DIRECTION OUTPUT ;
    USE SIGNAL ;
    PORT
      LAYER M5 ;
        RECT  47.952 0 47.976 0.192 ;
    END
  END rq[319]
  PIN rq[31]
    DIRECTION OUTPUT ;
    USE SIGNAL ;
    PORT
      LAYER M5 ;
        RECT  20.304 0 20.328 0.192 ;
    END
  END rq[31]
  PIN rq[320]
    DIRECTION OUTPUT ;
    USE SIGNAL ;
    PORT
      LAYER M5 ;
        RECT  48.048 0 48.072 0.192 ;
    END
  END rq[320]
  PIN rq[321]
    DIRECTION OUTPUT ;
    USE SIGNAL ;
    PORT
      LAYER M5 ;
        RECT  48.144 0 48.168 0.192 ;
    END
  END rq[321]
  PIN rq[322]
    DIRECTION OUTPUT ;
    USE SIGNAL ;
    PORT
      LAYER M5 ;
        RECT  48.24 0 48.264 0.192 ;
    END
  END rq[322]
  PIN rq[323]
    DIRECTION OUTPUT ;
    USE SIGNAL ;
    PORT
      LAYER M5 ;
        RECT  48.336 0 48.36 0.192 ;
    END
  END rq[323]
  PIN rq[324]
    DIRECTION OUTPUT ;
    USE SIGNAL ;
    PORT
      LAYER M5 ;
        RECT  48.432 0 48.456 0.192 ;
    END
  END rq[324]
  PIN rq[325]
    DIRECTION OUTPUT ;
    USE SIGNAL ;
    PORT
      LAYER M5 ;
        RECT  48.528 0 48.552 0.192 ;
    END
  END rq[325]
  PIN rq[326]
    DIRECTION OUTPUT ;
    USE SIGNAL ;
    PORT
      LAYER M5 ;
        RECT  48.624 0 48.648 0.192 ;
    END
  END rq[326]
  PIN rq[327]
    DIRECTION OUTPUT ;
    USE SIGNAL ;
    PORT
      LAYER M5 ;
        RECT  48.72 0 48.744 0.192 ;
    END
  END rq[327]
  PIN rq[328]
    DIRECTION OUTPUT ;
    USE SIGNAL ;
    PORT
      LAYER M5 ;
        RECT  48.816 0 48.84 0.192 ;
    END
  END rq[328]
  PIN rq[329]
    DIRECTION OUTPUT ;
    USE SIGNAL ;
    PORT
      LAYER M5 ;
        RECT  48.912 0 48.936 0.192 ;
    END
  END rq[329]
  PIN rq[32]
    DIRECTION OUTPUT ;
    USE SIGNAL ;
    PORT
      LAYER M5 ;
        RECT  20.4 0 20.424 0.192 ;
    END
  END rq[32]
  PIN rq[330]
    DIRECTION OUTPUT ;
    USE SIGNAL ;
    PORT
      LAYER M5 ;
        RECT  49.008 0 49.032 0.192 ;
    END
  END rq[330]
  PIN rq[331]
    DIRECTION OUTPUT ;
    USE SIGNAL ;
    PORT
      LAYER M5 ;
        RECT  49.104 0 49.128 0.192 ;
    END
  END rq[331]
  PIN rq[332]
    DIRECTION OUTPUT ;
    USE SIGNAL ;
    PORT
      LAYER M5 ;
        RECT  49.2 0 49.224 0.192 ;
    END
  END rq[332]
  PIN rq[333]
    DIRECTION OUTPUT ;
    USE SIGNAL ;
    PORT
      LAYER M5 ;
        RECT  49.296 0 49.32 0.192 ;
    END
  END rq[333]
  PIN rq[334]
    DIRECTION OUTPUT ;
    USE SIGNAL ;
    PORT
      LAYER M5 ;
        RECT  49.392 0 49.416 0.192 ;
    END
  END rq[334]
  PIN rq[335]
    DIRECTION OUTPUT ;
    USE SIGNAL ;
    PORT
      LAYER M5 ;
        RECT  49.488 0 49.512 0.192 ;
    END
  END rq[335]
  PIN rq[336]
    DIRECTION OUTPUT ;
    USE SIGNAL ;
    PORT
      LAYER M5 ;
        RECT  49.584 0 49.608 0.192 ;
    END
  END rq[336]
  PIN rq[337]
    DIRECTION OUTPUT ;
    USE SIGNAL ;
    PORT
      LAYER M5 ;
        RECT  49.68 0 49.704 0.192 ;
    END
  END rq[337]
  PIN rq[338]
    DIRECTION OUTPUT ;
    USE SIGNAL ;
    PORT
      LAYER M5 ;
        RECT  49.776 0 49.8 0.192 ;
    END
  END rq[338]
  PIN rq[339]
    DIRECTION OUTPUT ;
    USE SIGNAL ;
    PORT
      LAYER M5 ;
        RECT  49.872 0 49.896 0.192 ;
    END
  END rq[339]
  PIN rq[33]
    DIRECTION OUTPUT ;
    USE SIGNAL ;
    PORT
      LAYER M5 ;
        RECT  20.496 0 20.52 0.192 ;
    END
  END rq[33]
  PIN rq[340]
    DIRECTION OUTPUT ;
    USE SIGNAL ;
    PORT
      LAYER M5 ;
        RECT  49.968 0 49.992 0.192 ;
    END
  END rq[340]
  PIN rq[34]
    DIRECTION OUTPUT ;
    USE SIGNAL ;
    PORT
      LAYER M5 ;
        RECT  20.592 0 20.616 0.192 ;
    END
  END rq[34]
  PIN rq[35]
    DIRECTION OUTPUT ;
    USE SIGNAL ;
    PORT
      LAYER M5 ;
        RECT  20.688 0 20.712 0.192 ;
    END
  END rq[35]
  PIN rq[36]
    DIRECTION OUTPUT ;
    USE SIGNAL ;
    PORT
      LAYER M5 ;
        RECT  20.784 0 20.808 0.192 ;
    END
  END rq[36]
  PIN rq[37]
    DIRECTION OUTPUT ;
    USE SIGNAL ;
    PORT
      LAYER M5 ;
        RECT  20.88 0 20.904 0.192 ;
    END
  END rq[37]
  PIN rq[38]
    DIRECTION OUTPUT ;
    USE SIGNAL ;
    PORT
      LAYER M5 ;
        RECT  20.976 0 21 0.192 ;
    END
  END rq[38]
  PIN rq[39]
    DIRECTION OUTPUT ;
    USE SIGNAL ;
    PORT
      LAYER M5 ;
        RECT  21.072 0 21.096 0.192 ;
    END
  END rq[39]
  PIN rq[3]
    DIRECTION OUTPUT ;
    USE SIGNAL ;
    PORT
      LAYER M5 ;
        RECT  17.616 0 17.64 0.192 ;
    END
  END rq[3]
  PIN rq[40]
    DIRECTION OUTPUT ;
    USE SIGNAL ;
    PORT
      LAYER M5 ;
        RECT  21.168 0 21.192 0.192 ;
    END
  END rq[40]
  PIN rq[41]
    DIRECTION OUTPUT ;
    USE SIGNAL ;
    PORT
      LAYER M5 ;
        RECT  21.264 0 21.288 0.192 ;
    END
  END rq[41]
  PIN rq[42]
    DIRECTION OUTPUT ;
    USE SIGNAL ;
    PORT
      LAYER M5 ;
        RECT  21.36 0 21.384 0.192 ;
    END
  END rq[42]
  PIN rq[43]
    DIRECTION OUTPUT ;
    USE SIGNAL ;
    PORT
      LAYER M5 ;
        RECT  21.456 0 21.48 0.192 ;
    END
  END rq[43]
  PIN rq[44]
    DIRECTION OUTPUT ;
    USE SIGNAL ;
    PORT
      LAYER M5 ;
        RECT  21.552 0 21.576 0.192 ;
    END
  END rq[44]
  PIN rq[45]
    DIRECTION OUTPUT ;
    USE SIGNAL ;
    PORT
      LAYER M5 ;
        RECT  21.648 0 21.672 0.192 ;
    END
  END rq[45]
  PIN rq[46]
    DIRECTION OUTPUT ;
    USE SIGNAL ;
    PORT
      LAYER M5 ;
        RECT  21.744 0 21.768 0.192 ;
    END
  END rq[46]
  PIN rq[47]
    DIRECTION OUTPUT ;
    USE SIGNAL ;
    PORT
      LAYER M5 ;
        RECT  21.84 0 21.864 0.192 ;
    END
  END rq[47]
  PIN rq[48]
    DIRECTION OUTPUT ;
    USE SIGNAL ;
    PORT
      LAYER M5 ;
        RECT  21.936 0 21.96 0.192 ;
    END
  END rq[48]
  PIN rq[49]
    DIRECTION OUTPUT ;
    USE SIGNAL ;
    PORT
      LAYER M5 ;
        RECT  22.032 0 22.056 0.192 ;
    END
  END rq[49]
  PIN rq[4]
    DIRECTION OUTPUT ;
    USE SIGNAL ;
    PORT
      LAYER M5 ;
        RECT  17.712 0 17.736 0.192 ;
    END
  END rq[4]
  PIN rq[50]
    DIRECTION OUTPUT ;
    USE SIGNAL ;
    PORT
      LAYER M5 ;
        RECT  22.128 0 22.152 0.192 ;
    END
  END rq[50]
  PIN rq[51]
    DIRECTION OUTPUT ;
    USE SIGNAL ;
    PORT
      LAYER M5 ;
        RECT  22.224 0 22.248 0.192 ;
    END
  END rq[51]
  PIN rq[52]
    DIRECTION OUTPUT ;
    USE SIGNAL ;
    PORT
      LAYER M5 ;
        RECT  22.32 0 22.344 0.192 ;
    END
  END rq[52]
  PIN rq[53]
    DIRECTION OUTPUT ;
    USE SIGNAL ;
    PORT
      LAYER M5 ;
        RECT  22.416 0 22.44 0.192 ;
    END
  END rq[53]
  PIN rq[54]
    DIRECTION OUTPUT ;
    USE SIGNAL ;
    PORT
      LAYER M5 ;
        RECT  22.512 0 22.536 0.192 ;
    END
  END rq[54]
  PIN rq[55]
    DIRECTION OUTPUT ;
    USE SIGNAL ;
    PORT
      LAYER M5 ;
        RECT  22.608 0 22.632 0.192 ;
    END
  END rq[55]
  PIN rq[56]
    DIRECTION OUTPUT ;
    USE SIGNAL ;
    PORT
      LAYER M5 ;
        RECT  22.704 0 22.728 0.192 ;
    END
  END rq[56]
  PIN rq[57]
    DIRECTION OUTPUT ;
    USE SIGNAL ;
    PORT
      LAYER M5 ;
        RECT  22.8 0 22.824 0.192 ;
    END
  END rq[57]
  PIN rq[58]
    DIRECTION OUTPUT ;
    USE SIGNAL ;
    PORT
      LAYER M5 ;
        RECT  22.896 0 22.92 0.192 ;
    END
  END rq[58]
  PIN rq[59]
    DIRECTION OUTPUT ;
    USE SIGNAL ;
    PORT
      LAYER M5 ;
        RECT  22.992 0 23.016 0.192 ;
    END
  END rq[59]
  PIN rq[5]
    DIRECTION OUTPUT ;
    USE SIGNAL ;
    PORT
      LAYER M5 ;
        RECT  17.808 0 17.832 0.192 ;
    END
  END rq[5]
  PIN rq[60]
    DIRECTION OUTPUT ;
    USE SIGNAL ;
    PORT
      LAYER M5 ;
        RECT  23.088 0 23.112 0.192 ;
    END
  END rq[60]
  PIN rq[61]
    DIRECTION OUTPUT ;
    USE SIGNAL ;
    PORT
      LAYER M5 ;
        RECT  23.184 0 23.208 0.192 ;
    END
  END rq[61]
  PIN rq[62]
    DIRECTION OUTPUT ;
    USE SIGNAL ;
    PORT
      LAYER M5 ;
        RECT  23.28 0 23.304 0.192 ;
    END
  END rq[62]
  PIN rq[63]
    DIRECTION OUTPUT ;
    USE SIGNAL ;
    PORT
      LAYER M5 ;
        RECT  23.376 0 23.4 0.192 ;
    END
  END rq[63]
  PIN rq[64]
    DIRECTION OUTPUT ;
    USE SIGNAL ;
    PORT
      LAYER M5 ;
        RECT  23.472 0 23.496 0.192 ;
    END
  END rq[64]
  PIN rq[65]
    DIRECTION OUTPUT ;
    USE SIGNAL ;
    PORT
      LAYER M5 ;
        RECT  23.568 0 23.592 0.192 ;
    END
  END rq[65]
  PIN rq[66]
    DIRECTION OUTPUT ;
    USE SIGNAL ;
    PORT
      LAYER M5 ;
        RECT  23.664 0 23.688 0.192 ;
    END
  END rq[66]
  PIN rq[67]
    DIRECTION OUTPUT ;
    USE SIGNAL ;
    PORT
      LAYER M5 ;
        RECT  23.76 0 23.784 0.192 ;
    END
  END rq[67]
  PIN rq[68]
    DIRECTION OUTPUT ;
    USE SIGNAL ;
    PORT
      LAYER M5 ;
        RECT  23.856 0 23.88 0.192 ;
    END
  END rq[68]
  PIN rq[69]
    DIRECTION OUTPUT ;
    USE SIGNAL ;
    PORT
      LAYER M5 ;
        RECT  23.952 0 23.976 0.192 ;
    END
  END rq[69]
  PIN rq[6]
    DIRECTION OUTPUT ;
    USE SIGNAL ;
    PORT
      LAYER M5 ;
        RECT  17.904 0 17.928 0.192 ;
    END
  END rq[6]
  PIN rq[70]
    DIRECTION OUTPUT ;
    USE SIGNAL ;
    PORT
      LAYER M5 ;
        RECT  24.048 0 24.072 0.192 ;
    END
  END rq[70]
  PIN rq[71]
    DIRECTION OUTPUT ;
    USE SIGNAL ;
    PORT
      LAYER M5 ;
        RECT  24.144 0 24.168 0.192 ;
    END
  END rq[71]
  PIN rq[72]
    DIRECTION OUTPUT ;
    USE SIGNAL ;
    PORT
      LAYER M5 ;
        RECT  24.24 0 24.264 0.192 ;
    END
  END rq[72]
  PIN rq[73]
    DIRECTION OUTPUT ;
    USE SIGNAL ;
    PORT
      LAYER M5 ;
        RECT  24.336 0 24.36 0.192 ;
    END
  END rq[73]
  PIN rq[74]
    DIRECTION OUTPUT ;
    USE SIGNAL ;
    PORT
      LAYER M5 ;
        RECT  24.432 0 24.456 0.192 ;
    END
  END rq[74]
  PIN rq[75]
    DIRECTION OUTPUT ;
    USE SIGNAL ;
    PORT
      LAYER M5 ;
        RECT  24.528 0 24.552 0.192 ;
    END
  END rq[75]
  PIN rq[76]
    DIRECTION OUTPUT ;
    USE SIGNAL ;
    PORT
      LAYER M5 ;
        RECT  24.624 0 24.648 0.192 ;
    END
  END rq[76]
  PIN rq[77]
    DIRECTION OUTPUT ;
    USE SIGNAL ;
    PORT
      LAYER M5 ;
        RECT  24.72 0 24.744 0.192 ;
    END
  END rq[77]
  PIN rq[78]
    DIRECTION OUTPUT ;
    USE SIGNAL ;
    PORT
      LAYER M5 ;
        RECT  24.816 0 24.84 0.192 ;
    END
  END rq[78]
  PIN rq[79]
    DIRECTION OUTPUT ;
    USE SIGNAL ;
    PORT
      LAYER M5 ;
        RECT  24.912 0 24.936 0.192 ;
    END
  END rq[79]
  PIN rq[7]
    DIRECTION OUTPUT ;
    USE SIGNAL ;
    PORT
      LAYER M5 ;
        RECT  18 0 18.024 0.192 ;
    END
  END rq[7]
  PIN rq[80]
    DIRECTION OUTPUT ;
    USE SIGNAL ;
    PORT
      LAYER M5 ;
        RECT  25.008 0 25.032 0.192 ;
    END
  END rq[80]
  PIN rq[81]
    DIRECTION OUTPUT ;
    USE SIGNAL ;
    PORT
      LAYER M5 ;
        RECT  25.104 0 25.128 0.192 ;
    END
  END rq[81]
  PIN rq[82]
    DIRECTION OUTPUT ;
    USE SIGNAL ;
    PORT
      LAYER M5 ;
        RECT  25.2 0 25.224 0.192 ;
    END
  END rq[82]
  PIN rq[83]
    DIRECTION OUTPUT ;
    USE SIGNAL ;
    PORT
      LAYER M5 ;
        RECT  25.296 0 25.32 0.192 ;
    END
  END rq[83]
  PIN rq[84]
    DIRECTION OUTPUT ;
    USE SIGNAL ;
    PORT
      LAYER M5 ;
        RECT  25.392 0 25.416 0.192 ;
    END
  END rq[84]
  PIN rq[85]
    DIRECTION OUTPUT ;
    USE SIGNAL ;
    PORT
      LAYER M5 ;
        RECT  25.488 0 25.512 0.192 ;
    END
  END rq[85]
  PIN rq[86]
    DIRECTION OUTPUT ;
    USE SIGNAL ;
    PORT
      LAYER M5 ;
        RECT  25.584 0 25.608 0.192 ;
    END
  END rq[86]
  PIN rq[87]
    DIRECTION OUTPUT ;
    USE SIGNAL ;
    PORT
      LAYER M5 ;
        RECT  25.68 0 25.704 0.192 ;
    END
  END rq[87]
  PIN rq[88]
    DIRECTION OUTPUT ;
    USE SIGNAL ;
    PORT
      LAYER M5 ;
        RECT  25.776 0 25.8 0.192 ;
    END
  END rq[88]
  PIN rq[89]
    DIRECTION OUTPUT ;
    USE SIGNAL ;
    PORT
      LAYER M5 ;
        RECT  25.872 0 25.896 0.192 ;
    END
  END rq[89]
  PIN rq[8]
    DIRECTION OUTPUT ;
    USE SIGNAL ;
    PORT
      LAYER M5 ;
        RECT  18.096 0 18.12 0.192 ;
    END
  END rq[8]
  PIN rq[90]
    DIRECTION OUTPUT ;
    USE SIGNAL ;
    PORT
      LAYER M5 ;
        RECT  25.968 0 25.992 0.192 ;
    END
  END rq[90]
  PIN rq[91]
    DIRECTION OUTPUT ;
    USE SIGNAL ;
    PORT
      LAYER M5 ;
        RECT  26.064 0 26.088 0.192 ;
    END
  END rq[91]
  PIN rq[92]
    DIRECTION OUTPUT ;
    USE SIGNAL ;
    PORT
      LAYER M5 ;
        RECT  26.16 0 26.184 0.192 ;
    END
  END rq[92]
  PIN rq[93]
    DIRECTION OUTPUT ;
    USE SIGNAL ;
    PORT
      LAYER M5 ;
        RECT  26.256 0 26.28 0.192 ;
    END
  END rq[93]
  PIN rq[94]
    DIRECTION OUTPUT ;
    USE SIGNAL ;
    PORT
      LAYER M5 ;
        RECT  26.352 0 26.376 0.192 ;
    END
  END rq[94]
  PIN rq[95]
    DIRECTION OUTPUT ;
    USE SIGNAL ;
    PORT
      LAYER M5 ;
        RECT  26.448 0 26.472 0.192 ;
    END
  END rq[95]
  PIN rq[96]
    DIRECTION OUTPUT ;
    USE SIGNAL ;
    PORT
      LAYER M5 ;
        RECT  26.544 0 26.568 0.192 ;
    END
  END rq[96]
  PIN rq[97]
    DIRECTION OUTPUT ;
    USE SIGNAL ;
    PORT
      LAYER M5 ;
        RECT  26.64 0 26.664 0.192 ;
    END
  END rq[97]
  PIN rq[98]
    DIRECTION OUTPUT ;
    USE SIGNAL ;
    PORT
      LAYER M5 ;
        RECT  26.736 0 26.76 0.192 ;
    END
  END rq[98]
  PIN rq[99]
    DIRECTION OUTPUT ;
    USE SIGNAL ;
    PORT
      LAYER M5 ;
        RECT  26.832 0 26.856 0.192 ;
    END
  END rq[99]
  PIN rq[9]
    DIRECTION OUTPUT ;
    USE SIGNAL ;
    PORT
      LAYER M5 ;
        RECT  18.192 0 18.216 0.192 ;
    END
  END rq[9]
  PIN rst[0]
    DIRECTION INPUT ;
    USE SIGNAL ;
    PORT
      LAYER M5 ;
        RECT  113.28 43.008 113.304 43.2 ;
    END
  END rst[0]
  PIN rv[0]
    DIRECTION INPUT ;
    USE SIGNAL ;
    PORT
      LAYER M5 ;
        RECT  106.752 0 106.776 0.192 ;
    END
  END rv[0]
  PIN wd[0]
    DIRECTION INPUT ;
    USE SIGNAL ;
    PORT
      LAYER M5 ;
        RECT  50.16 0 50.184 0.192 ;
    END
  END wd[0]
  PIN VDD
    DIRECTION INOUT ;
    USE POWER ;
    PORT
      LAYER M7 ;
        RECT  114.256 0.531 114.544 42.669 ;
        RECT  103.456 0.531 103.744 42.669 ;
        RECT  92.656 0.531 92.944 42.669 ;
        RECT  81.856 0.531 82.144 42.669 ;
        RECT  71.056 0.531 71.344 42.669 ;
        RECT  60.256 0.531 60.544 42.669 ;
        RECT  49.456 0.531 49.744 42.669 ;
        RECT  38.656 0.531 38.944 42.669 ;
        RECT  27.856 0.531 28.144 42.669 ;
        RECT  17.056 0.531 17.344 42.669 ;
        RECT  6.256 0.531 6.544 42.669 ;
      LAYER M6 ;
        RECT  121.036 39.372 121.068 39.66 ;
        RECT  0 39.372 0.032 39.66 ;
        RECT  121.036 33.972 121.068 34.26 ;
        RECT  0 33.972 0.032 34.26 ;
        RECT  121.036 28.572 121.068 28.86 ;
        RECT  0 28.572 0.032 28.86 ;
        RECT  121.036 23.172 121.068 23.46 ;
        RECT  0 23.172 0.032 23.46 ;
        RECT  121.036 17.772 121.068 18.06 ;
        RECT  0 17.772 0.032 18.06 ;
        RECT  121.036 12.372 121.068 12.66 ;
        RECT  0 12.372 0.032 12.66 ;
        RECT  121.036 6.972 121.068 7.26 ;
        RECT  0 6.972 0.032 7.26 ;
        RECT  121.036 1.572 121.068 1.86 ;
        RECT  0 1.572 0.032 1.86 ;
      LAYER M2 ;
        RECT  121.05 42.381 121.068 42.399 ;
        RECT  0 42.381 0.018 42.399 ;
        RECT  121.05 41.841 121.068 41.859 ;
        RECT  0 41.841 0.018 41.859 ;
        RECT  121.05 41.301 121.068 41.319 ;
        RECT  0 41.301 0.018 41.319 ;
        RECT  121.05 40.761 121.068 40.779 ;
        RECT  0 40.761 0.018 40.779 ;
        RECT  121.05 40.221 121.068 40.239 ;
        RECT  0 40.221 0.018 40.239 ;
        RECT  121.05 39.681 121.068 39.699 ;
        RECT  0 39.681 0.018 39.699 ;
        RECT  121.05 39.141 121.068 39.159 ;
        RECT  0 39.141 0.018 39.159 ;
        RECT  121.05 38.601 121.068 38.619 ;
        RECT  0 38.601 0.018 38.619 ;
        RECT  121.05 38.061 121.068 38.079 ;
        RECT  0 38.061 0.018 38.079 ;
        RECT  121.05 37.521 121.068 37.539 ;
        RECT  0 37.521 0.018 37.539 ;
        RECT  121.05 36.981 121.068 36.999 ;
        RECT  0 36.981 0.018 36.999 ;
        RECT  121.05 36.441 121.068 36.459 ;
        RECT  0 36.441 0.018 36.459 ;
        RECT  121.05 35.901 121.068 35.919 ;
        RECT  0 35.901 0.018 35.919 ;
        RECT  121.05 35.361 121.068 35.379 ;
        RECT  0 35.361 0.018 35.379 ;
        RECT  121.05 34.821 121.068 34.839 ;
        RECT  0 34.821 0.018 34.839 ;
        RECT  121.05 34.281 121.068 34.299 ;
        RECT  0 34.281 0.018 34.299 ;
        RECT  121.05 33.741 121.068 33.759 ;
        RECT  0 33.741 0.018 33.759 ;
        RECT  121.05 33.201 121.068 33.219 ;
        RECT  0 33.201 0.018 33.219 ;
        RECT  121.05 32.661 121.068 32.679 ;
        RECT  0 32.661 0.018 32.679 ;
        RECT  121.05 32.121 121.068 32.139 ;
        RECT  0 32.121 0.018 32.139 ;
        RECT  121.05 31.581 121.068 31.599 ;
        RECT  0 31.581 0.018 31.599 ;
        RECT  121.05 31.041 121.068 31.059 ;
        RECT  0 31.041 0.018 31.059 ;
        RECT  121.05 30.501 121.068 30.519 ;
        RECT  0 30.501 0.018 30.519 ;
        RECT  121.05 29.961 121.068 29.979 ;
        RECT  0 29.961 0.018 29.979 ;
        RECT  121.05 29.421 121.068 29.439 ;
        RECT  0 29.421 0.018 29.439 ;
        RECT  121.05 28.881 121.068 28.899 ;
        RECT  0 28.881 0.018 28.899 ;
        RECT  121.05 28.341 121.068 28.359 ;
        RECT  0 28.341 0.018 28.359 ;
        RECT  121.05 27.801 121.068 27.819 ;
        RECT  0 27.801 0.018 27.819 ;
        RECT  121.05 27.261 121.068 27.279 ;
        RECT  0 27.261 0.018 27.279 ;
        RECT  121.05 26.721 121.068 26.739 ;
        RECT  0 26.721 0.018 26.739 ;
        RECT  121.05 26.181 121.068 26.199 ;
        RECT  0 26.181 0.018 26.199 ;
        RECT  121.05 25.641 121.068 25.659 ;
        RECT  0 25.641 0.018 25.659 ;
        RECT  121.05 25.101 121.068 25.119 ;
        RECT  0 25.101 0.018 25.119 ;
        RECT  121.05 24.561 121.068 24.579 ;
        RECT  0 24.561 0.018 24.579 ;
        RECT  121.05 24.021 121.068 24.039 ;
        RECT  0 24.021 0.018 24.039 ;
        RECT  121.05 23.481 121.068 23.499 ;
        RECT  0 23.481 0.018 23.499 ;
        RECT  121.05 22.941 121.068 22.959 ;
        RECT  0 22.941 0.018 22.959 ;
        RECT  121.05 22.401 121.068 22.419 ;
        RECT  0 22.401 0.018 22.419 ;
        RECT  121.05 21.861 121.068 21.879 ;
        RECT  0 21.861 0.018 21.879 ;
        RECT  121.05 21.321 121.068 21.339 ;
        RECT  0 21.321 0.018 21.339 ;
        RECT  121.05 20.781 121.068 20.799 ;
        RECT  0 20.781 0.018 20.799 ;
        RECT  121.05 20.241 121.068 20.259 ;
        RECT  0 20.241 0.018 20.259 ;
        RECT  121.05 19.701 121.068 19.719 ;
        RECT  0 19.701 0.018 19.719 ;
        RECT  121.05 19.161 121.068 19.179 ;
        RECT  0 19.161 0.018 19.179 ;
        RECT  121.05 18.621 121.068 18.639 ;
        RECT  0 18.621 0.018 18.639 ;
        RECT  121.05 18.081 121.068 18.099 ;
        RECT  0 18.081 0.018 18.099 ;
        RECT  121.05 17.541 121.068 17.559 ;
        RECT  0 17.541 0.018 17.559 ;
        RECT  121.05 17.001 121.068 17.019 ;
        RECT  0 17.001 0.018 17.019 ;
        RECT  121.05 16.461 121.068 16.479 ;
        RECT  0 16.461 0.018 16.479 ;
        RECT  121.05 15.921 121.068 15.939 ;
        RECT  0 15.921 0.018 15.939 ;
        RECT  121.05 15.381 121.068 15.399 ;
        RECT  0 15.381 0.018 15.399 ;
        RECT  121.05 14.841 121.068 14.859 ;
        RECT  0 14.841 0.018 14.859 ;
        RECT  121.05 14.301 121.068 14.319 ;
        RECT  0 14.301 0.018 14.319 ;
        RECT  121.05 13.761 121.068 13.779 ;
        RECT  0 13.761 0.018 13.779 ;
        RECT  121.05 13.221 121.068 13.239 ;
        RECT  0 13.221 0.018 13.239 ;
        RECT  121.05 12.681 121.068 12.699 ;
        RECT  0 12.681 0.018 12.699 ;
        RECT  121.05 12.141 121.068 12.159 ;
        RECT  0 12.141 0.018 12.159 ;
        RECT  121.05 11.601 121.068 11.619 ;
        RECT  0 11.601 0.018 11.619 ;
        RECT  121.05 11.061 121.068 11.079 ;
        RECT  0 11.061 0.018 11.079 ;
        RECT  121.05 10.521 121.068 10.539 ;
        RECT  0 10.521 0.018 10.539 ;
        RECT  121.05 9.981 121.068 9.999 ;
        RECT  0 9.981 0.018 9.999 ;
        RECT  121.05 9.441 121.068 9.459 ;
        RECT  0 9.441 0.018 9.459 ;
        RECT  121.05 8.901 121.068 8.919 ;
        RECT  0 8.901 0.018 8.919 ;
        RECT  121.05 8.361 121.068 8.379 ;
        RECT  0 8.361 0.018 8.379 ;
        RECT  121.05 7.821 121.068 7.839 ;
        RECT  0 7.821 0.018 7.839 ;
        RECT  121.05 7.281 121.068 7.299 ;
        RECT  0 7.281 0.018 7.299 ;
        RECT  121.05 6.741 121.068 6.759 ;
        RECT  0 6.741 0.018 6.759 ;
        RECT  121.05 6.201 121.068 6.219 ;
        RECT  0 6.201 0.018 6.219 ;
        RECT  121.05 5.661 121.068 5.679 ;
        RECT  0 5.661 0.018 5.679 ;
        RECT  121.05 5.121 121.068 5.139 ;
        RECT  0 5.121 0.018 5.139 ;
        RECT  121.05 4.581 121.068 4.599 ;
        RECT  0 4.581 0.018 4.599 ;
        RECT  121.05 4.041 121.068 4.059 ;
        RECT  0 4.041 0.018 4.059 ;
        RECT  121.05 3.501 121.068 3.519 ;
        RECT  0 3.501 0.018 3.519 ;
        RECT  121.05 2.961 121.068 2.979 ;
        RECT  0 2.961 0.018 2.979 ;
        RECT  121.05 2.421 121.068 2.439 ;
        RECT  0 2.421 0.018 2.439 ;
        RECT  121.05 1.881 121.068 1.899 ;
        RECT  0 1.881 0.018 1.899 ;
        RECT  121.05 1.341 121.068 1.359 ;
        RECT  0 1.341 0.018 1.359 ;
        RECT  121.05 0.801 121.068 0.819 ;
        RECT  0 0.801 0.018 0.819 ;
      LAYER M1 ;
        RECT  121.05 42.381 121.068 42.399 ;
        RECT  0 42.381 0.018 42.399 ;
        RECT  121.05 41.841 121.068 41.859 ;
        RECT  0 41.841 0.018 41.859 ;
        RECT  121.05 41.301 121.068 41.319 ;
        RECT  0 41.301 0.018 41.319 ;
        RECT  121.05 40.761 121.068 40.779 ;
        RECT  0 40.761 0.018 40.779 ;
        RECT  121.05 40.221 121.068 40.239 ;
        RECT  0 40.221 0.018 40.239 ;
        RECT  121.05 39.681 121.068 39.699 ;
        RECT  0 39.681 0.018 39.699 ;
        RECT  121.05 39.141 121.068 39.159 ;
        RECT  0 39.141 0.018 39.159 ;
        RECT  121.05 38.601 121.068 38.619 ;
        RECT  0 38.601 0.018 38.619 ;
        RECT  121.05 38.061 121.068 38.079 ;
        RECT  0 38.061 0.018 38.079 ;
        RECT  121.05 37.521 121.068 37.539 ;
        RECT  0 37.521 0.018 37.539 ;
        RECT  121.05 36.981 121.068 36.999 ;
        RECT  0 36.981 0.018 36.999 ;
        RECT  121.05 36.441 121.068 36.459 ;
        RECT  0 36.441 0.018 36.459 ;
        RECT  121.05 35.901 121.068 35.919 ;
        RECT  0 35.901 0.018 35.919 ;
        RECT  121.05 35.361 121.068 35.379 ;
        RECT  0 35.361 0.018 35.379 ;
        RECT  121.05 34.821 121.068 34.839 ;
        RECT  0 34.821 0.018 34.839 ;
        RECT  121.05 34.281 121.068 34.299 ;
        RECT  0 34.281 0.018 34.299 ;
        RECT  121.05 33.741 121.068 33.759 ;
        RECT  0 33.741 0.018 33.759 ;
        RECT  121.05 33.201 121.068 33.219 ;
        RECT  0 33.201 0.018 33.219 ;
        RECT  121.05 32.661 121.068 32.679 ;
        RECT  0 32.661 0.018 32.679 ;
        RECT  121.05 32.121 121.068 32.139 ;
        RECT  0 32.121 0.018 32.139 ;
        RECT  121.05 31.581 121.068 31.599 ;
        RECT  0 31.581 0.018 31.599 ;
        RECT  121.05 31.041 121.068 31.059 ;
        RECT  0 31.041 0.018 31.059 ;
        RECT  121.05 30.501 121.068 30.519 ;
        RECT  0 30.501 0.018 30.519 ;
        RECT  121.05 29.961 121.068 29.979 ;
        RECT  0 29.961 0.018 29.979 ;
        RECT  121.05 29.421 121.068 29.439 ;
        RECT  0 29.421 0.018 29.439 ;
        RECT  121.05 28.881 121.068 28.899 ;
        RECT  0 28.881 0.018 28.899 ;
        RECT  121.05 28.341 121.068 28.359 ;
        RECT  0 28.341 0.018 28.359 ;
        RECT  121.05 27.801 121.068 27.819 ;
        RECT  0 27.801 0.018 27.819 ;
        RECT  121.05 27.261 121.068 27.279 ;
        RECT  0 27.261 0.018 27.279 ;
        RECT  121.05 26.721 121.068 26.739 ;
        RECT  0 26.721 0.018 26.739 ;
        RECT  121.05 26.181 121.068 26.199 ;
        RECT  0 26.181 0.018 26.199 ;
        RECT  121.05 25.641 121.068 25.659 ;
        RECT  0 25.641 0.018 25.659 ;
        RECT  121.05 25.101 121.068 25.119 ;
        RECT  0 25.101 0.018 25.119 ;
        RECT  121.05 24.561 121.068 24.579 ;
        RECT  0 24.561 0.018 24.579 ;
        RECT  121.05 24.021 121.068 24.039 ;
        RECT  0 24.021 0.018 24.039 ;
        RECT  121.05 23.481 121.068 23.499 ;
        RECT  0 23.481 0.018 23.499 ;
        RECT  121.05 22.941 121.068 22.959 ;
        RECT  0 22.941 0.018 22.959 ;
        RECT  121.05 22.401 121.068 22.419 ;
        RECT  0 22.401 0.018 22.419 ;
        RECT  121.05 21.861 121.068 21.879 ;
        RECT  0 21.861 0.018 21.879 ;
        RECT  121.05 21.321 121.068 21.339 ;
        RECT  0 21.321 0.018 21.339 ;
        RECT  121.05 20.781 121.068 20.799 ;
        RECT  0 20.781 0.018 20.799 ;
        RECT  121.05 20.241 121.068 20.259 ;
        RECT  0 20.241 0.018 20.259 ;
        RECT  121.05 19.701 121.068 19.719 ;
        RECT  0 19.701 0.018 19.719 ;
        RECT  121.05 19.161 121.068 19.179 ;
        RECT  0 19.161 0.018 19.179 ;
        RECT  121.05 18.621 121.068 18.639 ;
        RECT  0 18.621 0.018 18.639 ;
        RECT  121.05 18.081 121.068 18.099 ;
        RECT  0 18.081 0.018 18.099 ;
        RECT  121.05 17.541 121.068 17.559 ;
        RECT  0 17.541 0.018 17.559 ;
        RECT  121.05 17.001 121.068 17.019 ;
        RECT  0 17.001 0.018 17.019 ;
        RECT  121.05 16.461 121.068 16.479 ;
        RECT  0 16.461 0.018 16.479 ;
        RECT  121.05 15.921 121.068 15.939 ;
        RECT  0 15.921 0.018 15.939 ;
        RECT  121.05 15.381 121.068 15.399 ;
        RECT  0 15.381 0.018 15.399 ;
        RECT  121.05 14.841 121.068 14.859 ;
        RECT  0 14.841 0.018 14.859 ;
        RECT  121.05 14.301 121.068 14.319 ;
        RECT  0 14.301 0.018 14.319 ;
        RECT  121.05 13.761 121.068 13.779 ;
        RECT  0 13.761 0.018 13.779 ;
        RECT  121.05 13.221 121.068 13.239 ;
        RECT  0 13.221 0.018 13.239 ;
        RECT  121.05 12.681 121.068 12.699 ;
        RECT  0 12.681 0.018 12.699 ;
        RECT  121.05 12.141 121.068 12.159 ;
        RECT  0 12.141 0.018 12.159 ;
        RECT  121.05 11.601 121.068 11.619 ;
        RECT  0 11.601 0.018 11.619 ;
        RECT  121.05 11.061 121.068 11.079 ;
        RECT  0 11.061 0.018 11.079 ;
        RECT  121.05 10.521 121.068 10.539 ;
        RECT  0 10.521 0.018 10.539 ;
        RECT  121.05 9.981 121.068 9.999 ;
        RECT  0 9.981 0.018 9.999 ;
        RECT  121.05 9.441 121.068 9.459 ;
        RECT  0 9.441 0.018 9.459 ;
        RECT  121.05 8.901 121.068 8.919 ;
        RECT  0 8.901 0.018 8.919 ;
        RECT  121.05 8.361 121.068 8.379 ;
        RECT  0 8.361 0.018 8.379 ;
        RECT  121.05 7.821 121.068 7.839 ;
        RECT  0 7.821 0.018 7.839 ;
        RECT  121.05 7.281 121.068 7.299 ;
        RECT  0 7.281 0.018 7.299 ;
        RECT  121.05 6.741 121.068 6.759 ;
        RECT  0 6.741 0.018 6.759 ;
        RECT  121.05 6.201 121.068 6.219 ;
        RECT  0 6.201 0.018 6.219 ;
        RECT  121.05 5.661 121.068 5.679 ;
        RECT  0 5.661 0.018 5.679 ;
        RECT  121.05 5.121 121.068 5.139 ;
        RECT  0 5.121 0.018 5.139 ;
        RECT  121.05 4.581 121.068 4.599 ;
        RECT  0 4.581 0.018 4.599 ;
        RECT  121.05 4.041 121.068 4.059 ;
        RECT  0 4.041 0.018 4.059 ;
        RECT  121.05 3.501 121.068 3.519 ;
        RECT  0 3.501 0.018 3.519 ;
        RECT  121.05 2.961 121.068 2.979 ;
        RECT  0 2.961 0.018 2.979 ;
        RECT  121.05 2.421 121.068 2.439 ;
        RECT  0 2.421 0.018 2.439 ;
        RECT  121.05 1.881 121.068 1.899 ;
        RECT  0 1.881 0.018 1.899 ;
        RECT  121.05 1.341 121.068 1.359 ;
        RECT  0 1.341 0.018 1.359 ;
        RECT  121.05 0.801 121.068 0.819 ;
        RECT  0 0.801 0.018 0.819 ;
    END
  END VDD
  PIN VSS
    DIRECTION INOUT ;
    USE GROUND ;
    PORT
      LAYER M7 ;
        RECT  119.656 0.531 119.944 42.669 ;
        RECT  108.856 0.531 109.144 42.669 ;
        RECT  98.056 0.531 98.344 42.669 ;
        RECT  87.256 0.531 87.544 42.669 ;
        RECT  76.456 0.531 76.744 42.669 ;
        RECT  65.656 0.531 65.944 42.669 ;
        RECT  54.856 0.531 55.144 42.669 ;
        RECT  44.056 0.531 44.344 42.669 ;
        RECT  33.256 0.531 33.544 42.669 ;
        RECT  22.456 0.531 22.744 42.669 ;
        RECT  11.656 0.531 11.944 42.669 ;
        RECT  0.856 0.531 1.144 42.669 ;
      LAYER M6 ;
        RECT  121.036 38.796 121.068 39.084 ;
        RECT  0 38.796 0.032 39.084 ;
        RECT  121.036 33.396 121.068 33.684 ;
        RECT  0 33.396 0.032 33.684 ;
        RECT  121.036 27.996 121.068 28.284 ;
        RECT  0 27.996 0.032 28.284 ;
        RECT  121.036 22.596 121.068 22.884 ;
        RECT  0 22.596 0.032 22.884 ;
        RECT  121.036 17.196 121.068 17.484 ;
        RECT  0 17.196 0.032 17.484 ;
        RECT  121.036 11.796 121.068 12.084 ;
        RECT  0 11.796 0.032 12.084 ;
        RECT  121.036 6.396 121.068 6.684 ;
        RECT  0 6.396 0.032 6.684 ;
        RECT  121.036 0.996 121.068 1.284 ;
        RECT  0 0.996 0.032 1.284 ;
      LAYER M2 ;
        RECT  121.05 42.651 121.068 42.669 ;
        RECT  0 42.651 0.018 42.669 ;
        RECT  121.05 42.111 121.068 42.129 ;
        RECT  0 42.111 0.018 42.129 ;
        RECT  121.05 41.571 121.068 41.589 ;
        RECT  0 41.571 0.018 41.589 ;
        RECT  121.05 41.031 121.068 41.049 ;
        RECT  0 41.031 0.018 41.049 ;
        RECT  121.05 40.491 121.068 40.509 ;
        RECT  0 40.491 0.018 40.509 ;
        RECT  121.05 39.951 121.068 39.969 ;
        RECT  0 39.951 0.018 39.969 ;
        RECT  121.05 39.411 121.068 39.429 ;
        RECT  0 39.411 0.018 39.429 ;
        RECT  121.05 38.871 121.068 38.889 ;
        RECT  0 38.871 0.018 38.889 ;
        RECT  121.05 38.331 121.068 38.349 ;
        RECT  0 38.331 0.018 38.349 ;
        RECT  121.05 37.791 121.068 37.809 ;
        RECT  0 37.791 0.018 37.809 ;
        RECT  121.05 37.251 121.068 37.269 ;
        RECT  0 37.251 0.018 37.269 ;
        RECT  121.05 36.711 121.068 36.729 ;
        RECT  0 36.711 0.018 36.729 ;
        RECT  121.05 36.171 121.068 36.189 ;
        RECT  0 36.171 0.018 36.189 ;
        RECT  121.05 35.631 121.068 35.649 ;
        RECT  0 35.631 0.018 35.649 ;
        RECT  121.05 35.091 121.068 35.109 ;
        RECT  0 35.091 0.018 35.109 ;
        RECT  121.05 34.551 121.068 34.569 ;
        RECT  0 34.551 0.018 34.569 ;
        RECT  121.05 34.011 121.068 34.029 ;
        RECT  0 34.011 0.018 34.029 ;
        RECT  121.05 33.471 121.068 33.489 ;
        RECT  0 33.471 0.018 33.489 ;
        RECT  121.05 32.931 121.068 32.949 ;
        RECT  0 32.931 0.018 32.949 ;
        RECT  121.05 32.391 121.068 32.409 ;
        RECT  0 32.391 0.018 32.409 ;
        RECT  121.05 31.851 121.068 31.869 ;
        RECT  0 31.851 0.018 31.869 ;
        RECT  121.05 31.311 121.068 31.329 ;
        RECT  0 31.311 0.018 31.329 ;
        RECT  121.05 30.771 121.068 30.789 ;
        RECT  0 30.771 0.018 30.789 ;
        RECT  121.05 30.231 121.068 30.249 ;
        RECT  0 30.231 0.018 30.249 ;
        RECT  121.05 29.691 121.068 29.709 ;
        RECT  0 29.691 0.018 29.709 ;
        RECT  121.05 29.151 121.068 29.169 ;
        RECT  0 29.151 0.018 29.169 ;
        RECT  121.05 28.611 121.068 28.629 ;
        RECT  0 28.611 0.018 28.629 ;
        RECT  121.05 28.071 121.068 28.089 ;
        RECT  0 28.071 0.018 28.089 ;
        RECT  121.05 27.531 121.068 27.549 ;
        RECT  0 27.531 0.018 27.549 ;
        RECT  121.05 26.991 121.068 27.009 ;
        RECT  0 26.991 0.018 27.009 ;
        RECT  121.05 26.451 121.068 26.469 ;
        RECT  0 26.451 0.018 26.469 ;
        RECT  121.05 25.911 121.068 25.929 ;
        RECT  0 25.911 0.018 25.929 ;
        RECT  121.05 25.371 121.068 25.389 ;
        RECT  0 25.371 0.018 25.389 ;
        RECT  121.05 24.831 121.068 24.849 ;
        RECT  0 24.831 0.018 24.849 ;
        RECT  121.05 24.291 121.068 24.309 ;
        RECT  0 24.291 0.018 24.309 ;
        RECT  121.05 23.751 121.068 23.769 ;
        RECT  0 23.751 0.018 23.769 ;
        RECT  121.05 23.211 121.068 23.229 ;
        RECT  0 23.211 0.018 23.229 ;
        RECT  121.05 22.671 121.068 22.689 ;
        RECT  0 22.671 0.018 22.689 ;
        RECT  121.05 22.131 121.068 22.149 ;
        RECT  0 22.131 0.018 22.149 ;
        RECT  121.05 21.591 121.068 21.609 ;
        RECT  0 21.591 0.018 21.609 ;
        RECT  121.05 21.051 121.068 21.069 ;
        RECT  0 21.051 0.018 21.069 ;
        RECT  121.05 20.511 121.068 20.529 ;
        RECT  0 20.511 0.018 20.529 ;
        RECT  121.05 19.971 121.068 19.989 ;
        RECT  0 19.971 0.018 19.989 ;
        RECT  121.05 19.431 121.068 19.449 ;
        RECT  0 19.431 0.018 19.449 ;
        RECT  121.05 18.891 121.068 18.909 ;
        RECT  0 18.891 0.018 18.909 ;
        RECT  121.05 18.351 121.068 18.369 ;
        RECT  0 18.351 0.018 18.369 ;
        RECT  121.05 17.811 121.068 17.829 ;
        RECT  0 17.811 0.018 17.829 ;
        RECT  121.05 17.271 121.068 17.289 ;
        RECT  0 17.271 0.018 17.289 ;
        RECT  121.05 16.731 121.068 16.749 ;
        RECT  0 16.731 0.018 16.749 ;
        RECT  121.05 16.191 121.068 16.209 ;
        RECT  0 16.191 0.018 16.209 ;
        RECT  121.05 15.651 121.068 15.669 ;
        RECT  0 15.651 0.018 15.669 ;
        RECT  121.05 15.111 121.068 15.129 ;
        RECT  0 15.111 0.018 15.129 ;
        RECT  121.05 14.571 121.068 14.589 ;
        RECT  0 14.571 0.018 14.589 ;
        RECT  121.05 14.031 121.068 14.049 ;
        RECT  0 14.031 0.018 14.049 ;
        RECT  121.05 13.491 121.068 13.509 ;
        RECT  0 13.491 0.018 13.509 ;
        RECT  121.05 12.951 121.068 12.969 ;
        RECT  0 12.951 0.018 12.969 ;
        RECT  121.05 12.411 121.068 12.429 ;
        RECT  0 12.411 0.018 12.429 ;
        RECT  121.05 11.871 121.068 11.889 ;
        RECT  0 11.871 0.018 11.889 ;
        RECT  121.05 11.331 121.068 11.349 ;
        RECT  0 11.331 0.018 11.349 ;
        RECT  121.05 10.791 121.068 10.809 ;
        RECT  0 10.791 0.018 10.809 ;
        RECT  121.05 10.251 121.068 10.269 ;
        RECT  0 10.251 0.018 10.269 ;
        RECT  121.05 9.711 121.068 9.729 ;
        RECT  0 9.711 0.018 9.729 ;
        RECT  121.05 9.171 121.068 9.189 ;
        RECT  0 9.171 0.018 9.189 ;
        RECT  121.05 8.631 121.068 8.649 ;
        RECT  0 8.631 0.018 8.649 ;
        RECT  121.05 8.091 121.068 8.109 ;
        RECT  0 8.091 0.018 8.109 ;
        RECT  121.05 7.551 121.068 7.569 ;
        RECT  0 7.551 0.018 7.569 ;
        RECT  121.05 7.011 121.068 7.029 ;
        RECT  0 7.011 0.018 7.029 ;
        RECT  121.05 6.471 121.068 6.489 ;
        RECT  0 6.471 0.018 6.489 ;
        RECT  121.05 5.931 121.068 5.949 ;
        RECT  0 5.931 0.018 5.949 ;
        RECT  121.05 5.391 121.068 5.409 ;
        RECT  0 5.391 0.018 5.409 ;
        RECT  121.05 4.851 121.068 4.869 ;
        RECT  0 4.851 0.018 4.869 ;
        RECT  121.05 4.311 121.068 4.329 ;
        RECT  0 4.311 0.018 4.329 ;
        RECT  121.05 3.771 121.068 3.789 ;
        RECT  0 3.771 0.018 3.789 ;
        RECT  121.05 3.231 121.068 3.249 ;
        RECT  0 3.231 0.018 3.249 ;
        RECT  121.05 2.691 121.068 2.709 ;
        RECT  0 2.691 0.018 2.709 ;
        RECT  121.05 2.151 121.068 2.169 ;
        RECT  0 2.151 0.018 2.169 ;
        RECT  121.05 1.611 121.068 1.629 ;
        RECT  0 1.611 0.018 1.629 ;
        RECT  121.05 1.071 121.068 1.089 ;
        RECT  0 1.071 0.018 1.089 ;
        RECT  121.05 0.531 121.068 0.549 ;
        RECT  0 0.531 0.018 0.549 ;
      LAYER M1 ;
        RECT  121.05 42.651 121.068 42.669 ;
        RECT  0 42.651 0.018 42.669 ;
        RECT  121.05 42.111 121.068 42.129 ;
        RECT  0 42.111 0.018 42.129 ;
        RECT  121.05 41.571 121.068 41.589 ;
        RECT  0 41.571 0.018 41.589 ;
        RECT  121.05 41.031 121.068 41.049 ;
        RECT  0 41.031 0.018 41.049 ;
        RECT  121.05 40.491 121.068 40.509 ;
        RECT  0 40.491 0.018 40.509 ;
        RECT  121.05 39.951 121.068 39.969 ;
        RECT  0 39.951 0.018 39.969 ;
        RECT  121.05 39.411 121.068 39.429 ;
        RECT  0 39.411 0.018 39.429 ;
        RECT  121.05 38.871 121.068 38.889 ;
        RECT  0 38.871 0.018 38.889 ;
        RECT  121.05 38.331 121.068 38.349 ;
        RECT  0 38.331 0.018 38.349 ;
        RECT  121.05 37.791 121.068 37.809 ;
        RECT  0 37.791 0.018 37.809 ;
        RECT  121.05 37.251 121.068 37.269 ;
        RECT  0 37.251 0.018 37.269 ;
        RECT  121.05 36.711 121.068 36.729 ;
        RECT  0 36.711 0.018 36.729 ;
        RECT  121.05 36.171 121.068 36.189 ;
        RECT  0 36.171 0.018 36.189 ;
        RECT  121.05 35.631 121.068 35.649 ;
        RECT  0 35.631 0.018 35.649 ;
        RECT  121.05 35.091 121.068 35.109 ;
        RECT  0 35.091 0.018 35.109 ;
        RECT  121.05 34.551 121.068 34.569 ;
        RECT  0 34.551 0.018 34.569 ;
        RECT  121.05 34.011 121.068 34.029 ;
        RECT  0 34.011 0.018 34.029 ;
        RECT  121.05 33.471 121.068 33.489 ;
        RECT  0 33.471 0.018 33.489 ;
        RECT  121.05 32.931 121.068 32.949 ;
        RECT  0 32.931 0.018 32.949 ;
        RECT  121.05 32.391 121.068 32.409 ;
        RECT  0 32.391 0.018 32.409 ;
        RECT  121.05 31.851 121.068 31.869 ;
        RECT  0 31.851 0.018 31.869 ;
        RECT  121.05 31.311 121.068 31.329 ;
        RECT  0 31.311 0.018 31.329 ;
        RECT  121.05 30.771 121.068 30.789 ;
        RECT  0 30.771 0.018 30.789 ;
        RECT  121.05 30.231 121.068 30.249 ;
        RECT  0 30.231 0.018 30.249 ;
        RECT  121.05 29.691 121.068 29.709 ;
        RECT  0 29.691 0.018 29.709 ;
        RECT  121.05 29.151 121.068 29.169 ;
        RECT  0 29.151 0.018 29.169 ;
        RECT  121.05 28.611 121.068 28.629 ;
        RECT  0 28.611 0.018 28.629 ;
        RECT  121.05 28.071 121.068 28.089 ;
        RECT  0 28.071 0.018 28.089 ;
        RECT  121.05 27.531 121.068 27.549 ;
        RECT  0 27.531 0.018 27.549 ;
        RECT  121.05 26.991 121.068 27.009 ;
        RECT  0 26.991 0.018 27.009 ;
        RECT  121.05 26.451 121.068 26.469 ;
        RECT  0 26.451 0.018 26.469 ;
        RECT  121.05 25.911 121.068 25.929 ;
        RECT  0 25.911 0.018 25.929 ;
        RECT  121.05 25.371 121.068 25.389 ;
        RECT  0 25.371 0.018 25.389 ;
        RECT  121.05 24.831 121.068 24.849 ;
        RECT  0 24.831 0.018 24.849 ;
        RECT  121.05 24.291 121.068 24.309 ;
        RECT  0 24.291 0.018 24.309 ;
        RECT  121.05 23.751 121.068 23.769 ;
        RECT  0 23.751 0.018 23.769 ;
        RECT  121.05 23.211 121.068 23.229 ;
        RECT  0 23.211 0.018 23.229 ;
        RECT  121.05 22.671 121.068 22.689 ;
        RECT  0 22.671 0.018 22.689 ;
        RECT  121.05 22.131 121.068 22.149 ;
        RECT  0 22.131 0.018 22.149 ;
        RECT  121.05 21.591 121.068 21.609 ;
        RECT  0 21.591 0.018 21.609 ;
        RECT  121.05 21.051 121.068 21.069 ;
        RECT  0 21.051 0.018 21.069 ;
        RECT  121.05 20.511 121.068 20.529 ;
        RECT  0 20.511 0.018 20.529 ;
        RECT  121.05 19.971 121.068 19.989 ;
        RECT  0 19.971 0.018 19.989 ;
        RECT  121.05 19.431 121.068 19.449 ;
        RECT  0 19.431 0.018 19.449 ;
        RECT  121.05 18.891 121.068 18.909 ;
        RECT  0 18.891 0.018 18.909 ;
        RECT  121.05 18.351 121.068 18.369 ;
        RECT  0 18.351 0.018 18.369 ;
        RECT  121.05 17.811 121.068 17.829 ;
        RECT  0 17.811 0.018 17.829 ;
        RECT  121.05 17.271 121.068 17.289 ;
        RECT  0 17.271 0.018 17.289 ;
        RECT  121.05 16.731 121.068 16.749 ;
        RECT  0 16.731 0.018 16.749 ;
        RECT  121.05 16.191 121.068 16.209 ;
        RECT  0 16.191 0.018 16.209 ;
        RECT  121.05 15.651 121.068 15.669 ;
        RECT  0 15.651 0.018 15.669 ;
        RECT  121.05 15.111 121.068 15.129 ;
        RECT  0 15.111 0.018 15.129 ;
        RECT  121.05 14.571 121.068 14.589 ;
        RECT  0 14.571 0.018 14.589 ;
        RECT  121.05 14.031 121.068 14.049 ;
        RECT  0 14.031 0.018 14.049 ;
        RECT  121.05 13.491 121.068 13.509 ;
        RECT  0 13.491 0.018 13.509 ;
        RECT  121.05 12.951 121.068 12.969 ;
        RECT  0 12.951 0.018 12.969 ;
        RECT  121.05 12.411 121.068 12.429 ;
        RECT  0 12.411 0.018 12.429 ;
        RECT  121.05 11.871 121.068 11.889 ;
        RECT  0 11.871 0.018 11.889 ;
        RECT  121.05 11.331 121.068 11.349 ;
        RECT  0 11.331 0.018 11.349 ;
        RECT  121.05 10.791 121.068 10.809 ;
        RECT  0 10.791 0.018 10.809 ;
        RECT  121.05 10.251 121.068 10.269 ;
        RECT  0 10.251 0.018 10.269 ;
        RECT  121.05 9.711 121.068 9.729 ;
        RECT  0 9.711 0.018 9.729 ;
        RECT  121.05 9.171 121.068 9.189 ;
        RECT  0 9.171 0.018 9.189 ;
        RECT  121.05 8.631 121.068 8.649 ;
        RECT  0 8.631 0.018 8.649 ;
        RECT  121.05 8.091 121.068 8.109 ;
        RECT  0 8.091 0.018 8.109 ;
        RECT  121.05 7.551 121.068 7.569 ;
        RECT  0 7.551 0.018 7.569 ;
        RECT  121.05 7.011 121.068 7.029 ;
        RECT  0 7.011 0.018 7.029 ;
        RECT  121.05 6.471 121.068 6.489 ;
        RECT  0 6.471 0.018 6.489 ;
        RECT  121.05 5.931 121.068 5.949 ;
        RECT  0 5.931 0.018 5.949 ;
        RECT  121.05 5.391 121.068 5.409 ;
        RECT  0 5.391 0.018 5.409 ;
        RECT  121.05 4.851 121.068 4.869 ;
        RECT  0 4.851 0.018 4.869 ;
        RECT  121.05 4.311 121.068 4.329 ;
        RECT  0 4.311 0.018 4.329 ;
        RECT  121.05 3.771 121.068 3.789 ;
        RECT  0 3.771 0.018 3.789 ;
        RECT  121.05 3.231 121.068 3.249 ;
        RECT  0 3.231 0.018 3.249 ;
        RECT  121.05 2.691 121.068 2.709 ;
        RECT  0 2.691 0.018 2.709 ;
        RECT  121.05 2.151 121.068 2.169 ;
        RECT  0 2.151 0.018 2.169 ;
        RECT  121.05 1.611 121.068 1.629 ;
        RECT  0 1.611 0.018 1.629 ;
        RECT  121.05 1.071 121.068 1.089 ;
        RECT  0 1.071 0.018 1.089 ;
        RECT  121.05 0.531 121.068 0.549 ;
        RECT  0 0.531 0.018 0.549 ;
    END
  END VSS
  OBS
    LAYER RVTN ;
     RECT  0 0.54 121.068 0.675 ;
     RECT  0 0.945 121.068 1.215 ;
     RECT  0 1.485 121.068 1.755 ;
     RECT  0 2.025 121.068 2.295 ;
     RECT  0 2.565 121.068 2.835 ;
     RECT  0 3.105 121.068 3.375 ;
     RECT  0 3.645 121.068 3.915 ;
     RECT  0 4.185 121.068 4.455 ;
     RECT  0 4.725 121.068 4.995 ;
     RECT  0 5.265 121.068 5.535 ;
     RECT  0 5.805 121.068 6.075 ;
     RECT  0 6.345 121.068 6.615 ;
     RECT  0 6.885 121.068 7.155 ;
     RECT  0 7.425 121.068 7.695 ;
     RECT  0 7.965 121.068 8.235 ;
     RECT  0 8.505 121.068 8.775 ;
     RECT  0 9.045 121.068 9.315 ;
     RECT  0 9.585 121.068 9.855 ;
     RECT  0 10.125 121.068 10.395 ;
     RECT  0 10.665 121.068 10.935 ;
     RECT  0 11.205 121.068 11.475 ;
     RECT  0 11.745 121.068 12.015 ;
     RECT  0 12.285 121.068 12.555 ;
     RECT  0 12.825 121.068 13.095 ;
     RECT  0 13.365 121.068 13.635 ;
     RECT  0 13.905 121.068 14.175 ;
     RECT  0 14.445 121.068 14.715 ;
     RECT  0 14.985 121.068 15.255 ;
     RECT  0 15.525 121.068 15.795 ;
     RECT  0 16.065 121.068 16.335 ;
     RECT  0 16.605 121.068 16.875 ;
     RECT  0 17.145 121.068 17.415 ;
     RECT  0 17.685 121.068 17.955 ;
     RECT  0 18.225 121.068 18.495 ;
     RECT  0 18.765 121.068 19.035 ;
     RECT  0 19.305 121.068 19.575 ;
     RECT  0 19.845 121.068 20.115 ;
     RECT  0 20.385 121.068 20.655 ;
     RECT  0 20.925 121.068 21.195 ;
     RECT  0 21.465 121.068 21.735 ;
     RECT  0 22.005 121.068 22.275 ;
     RECT  0 22.545 121.068 22.815 ;
     RECT  0 23.085 121.068 23.355 ;
     RECT  0 23.625 121.068 23.895 ;
     RECT  0 24.165 121.068 24.435 ;
     RECT  0 24.705 121.068 24.975 ;
     RECT  0 25.245 121.068 25.515 ;
     RECT  0 25.785 121.068 26.055 ;
     RECT  0 26.325 121.068 26.595 ;
     RECT  0 26.865 121.068 27.135 ;
     RECT  0 27.405 121.068 27.675 ;
     RECT  0 27.945 121.068 28.215 ;
     RECT  0 28.485 121.068 28.755 ;
     RECT  0 29.025 121.068 29.295 ;
     RECT  0 29.565 121.068 29.835 ;
     RECT  0 30.105 121.068 30.375 ;
     RECT  0 30.645 121.068 30.915 ;
     RECT  0 31.185 121.068 31.455 ;
     RECT  0 31.725 121.068 31.995 ;
     RECT  0 32.265 121.068 32.535 ;
     RECT  0 32.805 121.068 33.075 ;
     RECT  0 33.345 121.068 33.615 ;
     RECT  0 33.885 121.068 34.155 ;
     RECT  0 34.425 121.068 34.695 ;
     RECT  0 34.965 121.068 35.235 ;
     RECT  0 35.505 121.068 35.775 ;
     RECT  0 36.045 121.068 36.315 ;
     RECT  0 36.585 121.068 36.855 ;
     RECT  0 37.125 121.068 37.395 ;
     RECT  0 37.665 121.068 37.935 ;
     RECT  0 38.205 121.068 38.475 ;
     RECT  0 38.745 121.068 39.015 ;
     RECT  0 39.285 121.068 39.555 ;
     RECT  0 39.825 121.068 40.095 ;
     RECT  0 40.365 121.068 40.635 ;
     RECT  0 40.905 121.068 41.175 ;
     RECT  0 41.445 121.068 41.715 ;
     RECT  0 41.985 121.068 42.255 ;
     RECT  0 42.525 121.068 42.66 ;
    LAYER RVTP ;
     RECT  0 0.675 121.068 0.945 ;
     RECT  0 1.215 121.068 1.485 ;
     RECT  0 1.755 121.068 2.025 ;
     RECT  0 2.295 121.068 2.565 ;
     RECT  0 2.835 121.068 3.105 ;
     RECT  0 3.375 121.068 3.645 ;
     RECT  0 3.915 121.068 4.185 ;
     RECT  0 4.455 121.068 4.725 ;
     RECT  0 4.995 121.068 5.265 ;
     RECT  0 5.535 121.068 5.805 ;
     RECT  0 6.075 121.068 6.345 ;
     RECT  0 6.615 121.068 6.885 ;
     RECT  0 7.155 121.068 7.425 ;
     RECT  0 7.695 121.068 7.965 ;
     RECT  0 8.235 121.068 8.505 ;
     RECT  0 8.775 121.068 9.045 ;
     RECT  0 9.315 121.068 9.585 ;
     RECT  0 9.855 121.068 10.125 ;
     RECT  0 10.395 121.068 10.665 ;
     RECT  0 10.935 121.068 11.205 ;
     RECT  0 11.475 121.068 11.745 ;
     RECT  0 12.015 121.068 12.285 ;
     RECT  0 12.555 121.068 12.825 ;
     RECT  0 13.095 121.068 13.365 ;
     RECT  0 13.635 121.068 13.905 ;
     RECT  0 14.175 121.068 14.445 ;
     RECT  0 14.715 121.068 14.985 ;
     RECT  0 15.255 121.068 15.525 ;
     RECT  0 15.795 121.068 16.065 ;
     RECT  0 16.335 121.068 16.605 ;
     RECT  0 16.875 121.068 17.145 ;
     RECT  0 17.415 121.068 17.685 ;
     RECT  0 17.955 121.068 18.225 ;
     RECT  0 18.495 121.068 18.765 ;
     RECT  0 19.035 121.068 19.305 ;
     RECT  0 19.575 121.068 19.845 ;
     RECT  0 20.115 121.068 20.385 ;
     RECT  0 20.655 121.068 20.925 ;
     RECT  0 21.195 121.068 21.465 ;
     RECT  0 21.735 121.068 22.005 ;
     RECT  0 22.275 121.068 22.545 ;
     RECT  0 22.815 121.068 23.085 ;
     RECT  0 23.355 121.068 23.625 ;
     RECT  0 23.895 121.068 24.165 ;
     RECT  0 24.435 121.068 24.705 ;
     RECT  0 24.975 121.068 25.245 ;
     RECT  0 25.515 121.068 25.785 ;
     RECT  0 26.055 121.068 26.325 ;
     RECT  0 26.595 121.068 26.865 ;
     RECT  0 27.135 121.068 27.405 ;
     RECT  0 27.675 121.068 27.945 ;
     RECT  0 28.215 121.068 28.485 ;
     RECT  0 28.755 121.068 29.025 ;
     RECT  0 29.295 121.068 29.565 ;
     RECT  0 29.835 121.068 30.105 ;
     RECT  0 30.375 121.068 30.645 ;
     RECT  0 30.915 121.068 31.185 ;
     RECT  0 31.455 121.068 31.725 ;
     RECT  0 31.995 121.068 32.265 ;
     RECT  0 32.535 121.068 32.805 ;
     RECT  0 33.075 121.068 33.345 ;
     RECT  0 33.615 121.068 33.885 ;
     RECT  0 34.155 121.068 34.425 ;
     RECT  0 34.695 121.068 34.965 ;
     RECT  0 35.235 121.068 35.505 ;
     RECT  0 35.775 121.068 36.045 ;
     RECT  0 36.315 121.068 36.585 ;
     RECT  0 36.855 121.068 37.125 ;
     RECT  0 37.395 121.068 37.665 ;
     RECT  0 37.935 121.068 38.205 ;
     RECT  0 38.475 121.068 38.745 ;
     RECT  0 39.015 121.068 39.285 ;
     RECT  0 39.555 121.068 39.825 ;
     RECT  0 40.095 121.068 40.365 ;
     RECT  0 40.635 121.068 40.905 ;
     RECT  0 41.175 121.068 41.445 ;
     RECT  0 41.715 121.068 41.985 ;
     RECT  0 42.255 121.068 42.525 ;
    LAYER M1 ;
     RECT  0 0.531 121.068 42.669 ;
    LAYER M2 ;
     RECT  0 0.531 121.068 42.669 ;
    LAYER M3 ;
     RECT  17.532 0.187 18.486 0.235 ;
     RECT  27.9 0.187 27.918 0.235 ;
     RECT  28.98 0.187 28.998 0.235 ;
     RECT  30.024 0.187 31.662 0.235 ;
     RECT  33.048 0.187 34.326 0.235 ;
     RECT  35.208 0.187 36.558 0.235 ;
     RECT  37.476 0.187 37.494 0.235 ;
     RECT  38.448 0.187 43.794 0.235 ;
     RECT  49.536 0.187 49.554 0.235 ;
     RECT  92.592 0.187 95.31 0.235 ;
     RECT  102.24 0.187 102.258 0.235 ;
     RECT  103.212 0.187 106.866 0.235 ;
     RECT  96.048 0.187 97.614 0.283 ;
     RECT  98.424 0.187 100.386 0.283 ;
     RECT  88.416 0.187 91.314 0.331 ;
     RECT  92.52 0.235 95.31 0.331 ;
     RECT  19.584 0.187 21.582 0.379 ;
     RECT  22.788 0.187 26.478 0.379 ;
     RECT  27.9 0.235 29.178 0.379 ;
     RECT  32.796 0.235 37.494 0.379 ;
     RECT  38.376 0.235 44.01 0.379 ;
     RECT  48.6 0.187 48.618 0.379 ;
     RECT  49.428 0.235 49.554 0.379 ;
     RECT  84.96 0.187 85.95 0.379 ;
     RECT  86.796 0.187 87.642 0.379 ;
     RECT  32.796 0.379 44.01 0.475 ;
     RECT  44.82 0.187 45.018 0.475 ;
     RECT  17.532 0.235 18.702 0.523 ;
     RECT  19.584 0.379 22.014 0.523 ;
     RECT  22.788 0.379 29.178 0.523 ;
     RECT  30.024 0.235 31.734 0.523 ;
     RECT  32.796 0.475 45.018 0.523 ;
     RECT  80.532 0.187 82.998 0.523 ;
     RECT  17.532 0.523 18.81 0.571 ;
     RECT  19.584 0.523 31.734 0.571 ;
     RECT  32.655 0.523 45.018 0.571 ;
     RECT  48.6 0.379 49.554 0.571 ;
     RECT  50.292 0.523 50.31 0.571 ;
     RECT  84.96 0.379 87.642 0.571 ;
     RECT  84.96 0.571 87.678 0.751 ;
     RECT  88.416 0.331 95.31 0.751 ;
     RECT  0.255 0.523 0.345 0.793 ;
     RECT  5.655 0.523 5.745 0.793 ;
     RECT  11.055 0.523 11.145 0.793 ;
     RECT  16.455 0.523 16.545 0.793 ;
     RECT  54.255 0.523 54.345 0.793 ;
     RECT  59.655 0.523 59.745 0.793 ;
     RECT  65.055 0.523 65.145 0.793 ;
     RECT  70.455 0.523 70.545 0.793 ;
     RECT  75.855 0.523 75.945 0.793 ;
     RECT  108.255 0.523 108.345 0.793 ;
     RECT  113.655 0.523 113.745 0.793 ;
     RECT  119.055 0.523 119.145 0.793 ;
     RECT  84.96 0.751 95.31 1.021 ;
     RECT  96.048 0.283 100.386 1.021 ;
     RECT  102.24 0.235 106.866 1.021 ;
     RECT  45.756 0.187 47.61 1.099 ;
     RECT  48.6 0.571 50.31 1.099 ;
     RECT  80.208 0.523 83.394 1.099 ;
     RECT  80.208 1.099 83.79 1.111 ;
     RECT  84.96 1.021 100.386 1.111 ;
     RECT  17.532 0.571 45.018 1.147 ;
     RECT  45.756 1.099 50.31 1.147 ;
     RECT  80.208 1.111 100.386 1.147 ;
     RECT  102.132 1.021 106.974 1.147 ;
     RECT  79.992 1.147 106.974 1.243 ;
     RECT  79.956 1.243 106.974 1.489 ;
     RECT  17.532 1.147 50.31 1.561 ;
     RECT  108.255 0.793 108.537 1.651 ;
     RECT  79.92 1.489 106.974 1.715 ;
     RECT  79.92 1.715 106.542 2.641 ;
     RECT  79.776 2.641 106.542 3.335 ;
     RECT  17.532 1.561 50.346 3.379 ;
     RECT  17.532 3.379 50.49 3.403 ;
     RECT  79.812 3.335 106.542 3.839 ;
     RECT  17.532 3.403 50.562 4.531 ;
     RECT  79.92 3.839 106.542 4.555 ;
     RECT  17.532 4.531 50.67 4.649 ;
     RECT  79.92 4.555 106.65 4.955 ;
     RECT  17.532 4.649 50.598 5.035 ;
     RECT  17.46 5.035 50.598 5.459 ;
     RECT  17.46 5.459 50.49 5.495 ;
     RECT  79.92 4.955 106.578 6.283 ;
     RECT  16.455 0.793 16.737 6.547 ;
     RECT  79.92 6.283 106.686 6.691 ;
     RECT  16.452 6.547 16.737 6.845 ;
     RECT  16.455 6.845 16.737 6.961 ;
     RECT  17.46 5.495 50.454 6.961 ;
     RECT  16.455 6.961 50.454 7.159 ;
     RECT  16.455 7.159 50.706 7.349 ;
     RECT  16.455 7.349 50.67 8.545 ;
     RECT  16.455 8.545 50.778 9.121 ;
     RECT  16.455 9.121 50.886 9.625 ;
     RECT  16.455 9.625 50.922 9.779 ;
     RECT  79.92 6.691 106.902 12.587 ;
     RECT  107.712 1.651 108.537 13.981 ;
     RECT  16.455 9.779 50.346 16.105 ;
     RECT  16.455 16.105 50.85 16.411 ;
     RECT  16.455 16.411 51.03 16.799 ;
     RECT  16.455 16.799 50.994 17.339 ;
     RECT  79.92 12.587 106.794 19.373 ;
     RECT  79.92 19.373 106.65 20.039 ;
     RECT  107.532 13.981 108.537 20.191 ;
     RECT  61.92 21.091 61.938 21.093 ;
     RECT  61.917 21.093 61.941 21.192 ;
     RECT  61.92 21.192 61.938 21.197 ;
     RECT  59.655 0.793 59.937 21.211 ;
     RECT  59.655 21.211 60.03 21.341 ;
     RECT  63.468 21.235 63.486 21.485 ;
     RECT  79.92 20.039 106.542 22.081 ;
     RECT  107.28 20.191 108.537 22.081 ;
     RECT  79.92 22.081 108.537 31.955 ;
     RECT  80.244 31.955 108.537 34.727 ;
     RECT  16.455 17.339 50.346 36.461 ;
     RECT  16.455 36.461 16.737 37.975 ;
     RECT  17.46 36.461 50.346 37.975 ;
     RECT  16.455 37.975 50.346 38.309 ;
     RECT  80.244 34.727 106.974 40.099 ;
     RECT  107.712 34.727 108.537 40.099 ;
     RECT  80.244 40.099 108.537 40.171 ;
     RECT  80.244 40.171 108.846 40.397 ;
     RECT  108.255 40.397 108.846 40.441 ;
     RECT  108.255 40.441 108.918 40.531 ;
     RECT  108.255 40.531 109.134 40.631 ;
     RECT  112.896 40.567 112.914 40.675 ;
     RECT  108.255 40.631 108.918 40.901 ;
     RECT  111.636 40.369 111.654 40.981 ;
     RECT  112.5 40.675 112.914 40.981 ;
     RECT  113.655 0.793 113.937 40.981 ;
     RECT  16.455 38.309 50.31 41.069 ;
     RECT  111.636 40.981 113.937 41.243 ;
     RECT  26.064 41.069 50.31 41.279 ;
     RECT  80.244 40.397 106.974 41.341 ;
     RECT  111.636 41.243 112.878 41.369 ;
     RECT  80.244 41.341 107.154 41.405 ;
     RECT  111.636 41.369 111.654 41.405 ;
     RECT  26.064 41.279 42.498 41.477 ;
     RECT  108.255 40.901 108.774 41.513 ;
     RECT  43.308 41.279 50.31 41.639 ;
     RECT  112.5 41.369 112.878 41.789 ;
     RECT  112.5 41.789 112.662 41.909 ;
     RECT  80.244 41.405 106.974 41.945 ;
     RECT  112.5 41.909 112.518 41.945 ;
     RECT  80.244 41.945 106.578 42.017 ;
     RECT  16.455 41.069 25.29 42.025 ;
     RECT  26.064 41.477 37.206 42.025 ;
     RECT  37.944 41.477 42.498 42.025 ;
     RECT  16.455 42.025 37.206 42.221 ;
     RECT  80.244 42.017 83.214 42.221 ;
     RECT  83.988 42.017 106.578 42.221 ;
     RECT  84.096 42.221 88.722 42.269 ;
     RECT  89.532 42.221 89.55 42.269 ;
     RECT  91.98 42.221 94.05 42.269 ;
     RECT  95.292 42.221 95.526 42.269 ;
     RECT  96.588 42.221 99.414 42.269 ;
     RECT  100.44 42.221 101.43 42.269 ;
     RECT  102.276 42.221 104.778 42.269 ;
     RECT  106.092 42.221 106.542 42.269 ;
     RECT  83.16 42.221 83.178 42.317 ;
     RECT  84.096 42.269 87.174 42.317 ;
     RECT  88.056 42.269 88.074 42.317 ;
     RECT  90.648 42.221 90.666 42.317 ;
     RECT  91.98 42.269 93.834 42.317 ;
     RECT  95.292 42.269 95.49 42.317 ;
     RECT  100.98 42.269 101.214 42.317 ;
     RECT  102.276 42.269 104.058 42.317 ;
     RECT  106.488 42.269 106.542 42.317 ;
     RECT  17.892 42.221 34.182 42.365 ;
     RECT  43.308 41.639 50.166 42.365 ;
     RECT  81.108 42.221 82.386 42.365 ;
     RECT  84.096 42.317 84.438 42.365 ;
     RECT  93.708 42.317 93.834 42.365 ;
     RECT  95.472 42.317 95.49 42.365 ;
     RECT  0.255 0.793 0.537 42.407 ;
     RECT  5.655 0.793 5.937 42.407 ;
     RECT  11.055 0.793 11.337 42.407 ;
     RECT  16.455 42.221 16.737 42.407 ;
     RECT  54.255 0.793 54.537 42.407 ;
     RECT  59.655 21.341 59.937 42.407 ;
     RECT  65.055 0.793 65.337 42.407 ;
     RECT  70.455 0.793 70.737 42.407 ;
     RECT  75.855 0.793 76.137 42.407 ;
     RECT  108.255 41.513 108.537 42.407 ;
     RECT  113.655 41.243 113.937 42.407 ;
     RECT  119.055 0.793 119.337 42.407 ;
     RECT  43.308 42.365 46.098 42.413 ;
     RECT  81.108 42.365 82.278 42.413 ;
     RECT  93.708 42.365 93.726 42.413 ;
     RECT  106.488 42.317 106.506 42.413 ;
     RECT  17.892 42.365 34.074 42.449 ;
     RECT  37.944 42.025 42.57 42.449 ;
     RECT  43.308 42.413 44.982 42.449 ;
     RECT  47.844 42.365 50.166 42.449 ;
     RECT  84.096 42.365 84.258 42.449 ;
     RECT  84.096 42.449 84.114 42.485 ;
     RECT  97.455 42.269 98.91 42.485 ;
     RECT  81.108 42.413 81.63 42.557 ;
     RECT  91.98 42.317 92.79 42.557 ;
     RECT  17.892 42.449 18.882 42.605 ;
     RECT  19.836 42.449 30.402 42.605 ;
     RECT  31.14 42.449 33.966 42.605 ;
     RECT  35.28 42.221 37.206 42.605 ;
     RECT  37.944 42.449 42.426 42.605 ;
     RECT  43.308 42.449 44.91 42.605 ;
     RECT  45.72 42.413 46.098 42.605 ;
     RECT  47.844 42.449 50.058 42.605 ;
     RECT  97.455 42.485 97.974 42.605 ;
     RECT  18.396 42.605 18.414 42.629 ;
     RECT  20.376 42.605 20.79 42.629 ;
     RECT  35.748 42.605 35.766 42.629 ;
     RECT  85.356 42.317 87.174 42.629 ;
     RECT  20.376 42.629 20.394 42.653 ;
     RECT  27.144 42.605 27.738 42.653 ;
     RECT  32.364 42.605 33.03 42.653 ;
     RECT  43.308 42.605 44.37 42.653 ;
     RECT  98.892 42.485 98.91 42.653 ;
     RECT  102.384 42.317 104.058 42.653 ;
     RECT  0.255 42.407 0.345 42.677 ;
     RECT  5.655 42.407 5.745 42.677 ;
     RECT  11.055 42.407 11.145 42.677 ;
     RECT  16.455 42.407 16.545 42.677 ;
     RECT  21.636 42.605 21.945 42.677 ;
     RECT  27.255 42.653 27.738 42.677 ;
     RECT  32.364 42.653 32.745 42.677 ;
     RECT  47.844 42.605 48.945 42.677 ;
     RECT  54.255 42.407 54.345 42.677 ;
     RECT  59.655 42.407 59.745 42.677 ;
     RECT  65.055 42.407 65.145 42.677 ;
     RECT  70.455 42.407 70.545 42.677 ;
     RECT  75.855 42.407 75.945 42.677 ;
     RECT  81.108 42.557 81.345 42.677 ;
     RECT  92.016 42.557 92.145 42.677 ;
     RECT  97.455 42.605 97.794 42.677 ;
     RECT  102.855 42.653 103.626 42.677 ;
     RECT  108.255 42.407 108.345 42.677 ;
     RECT  113.655 42.407 113.745 42.677 ;
     RECT  119.055 42.407 119.145 42.677 ;
     RECT  86.004 42.629 87.174 42.749 ;
     RECT  37.944 42.605 38.214 42.797 ;
     RECT  43.308 42.653 43.866 42.797 ;
     RECT  47.844 42.677 48.798 42.797 ;
     RECT  81.108 42.677 81.126 42.797 ;
     RECT  86.004 42.749 87.102 42.797 ;
     RECT  92.016 42.677 92.034 42.797 ;
     RECT  102.996 42.677 103.626 42.797 ;
     RECT  21.636 42.677 21.654 42.845 ;
     RECT  37.944 42.797 37.962 42.845 ;
     RECT  103.608 42.797 103.626 42.845 ;
     RECT  27.72 42.677 27.738 42.893 ;
     RECT  32.364 42.677 32.598 42.893 ;
     RECT  47.844 42.797 48.582 42.893 ;
     RECT  36.684 42.605 37.206 42.955 ;
     RECT  97.776 42.677 97.794 42.989 ;
     RECT  23.076 42.605 23.706 43.085 ;
     RECT  31.176 42.605 31.194 43.085 ;
     RECT  32.364 42.893 32.382 43.085 ;
     RECT  36.684 42.955 37.602 43.085 ;
     RECT  46.08 42.605 46.098 43.085 ;
     RECT  46.944 42.365 46.962 43.085 ;
     RECT  47.844 42.893 48.042 43.085 ;
     RECT  86.004 42.797 86.022 43.085 ;
     RECT  37.584 43.085 37.602 43.133 ;
    LAYER M4 ;
     RECT  0.248 0.528 0.352 42.672 ;
     RECT  0.352 0.798 0.544 42.402 ;
     RECT  5.648 0.528 5.752 42.672 ;
     RECT  5.752 0.798 5.944 42.402 ;
     RECT  11.048 0.528 11.152 42.672 ;
     RECT  11.152 0.798 11.344 42.402 ;
     RECT  16.448 0.528 16.552 42.672 ;
     RECT  16.552 0.528 16.744 42.402 ;
     RECT  16.744 0.528 17.509 0.6 ;
     RECT  16.744 35.904 17.555 36.504 ;
     RECT  16.744 9.696 17.633 9.72 ;
     RECT  17.555 35.952 17.651 36.504 ;
     RECT  17.651 36.48 17.747 36.504 ;
     RECT  16.744 42.192 17.881 42.216 ;
     RECT  17.797 1.728 17.885 1.752 ;
     RECT  17.881 42.192 17.893 42.6 ;
     RECT  17.509 0.192 17.953 0.6 ;
     RECT  17.893 41.232 17.957 42.6 ;
     RECT  17.845 37.008 18.035 37.032 ;
     RECT  16.744 6.288 18.209 6.312 ;
     RECT  16.744 4.56 18.281 4.584 ;
     RECT  18.757 10.848 18.893 10.872 ;
     RECT  17.957 41.52 18.925 42.6 ;
     RECT  18.949 38.208 18.997 38.232 ;
     RECT  18.997 36.672 19.073 36.696 ;
     RECT  18.925 41.04 19.091 42.6 ;
     RECT  17.953 0.192 19.141 1.176 ;
     RECT  18.949 3.408 19.145 3.432 ;
     RECT  19.091 41.232 19.187 42.6 ;
     RECT  18.997 38.208 19.213 38.808 ;
     RECT  19.237 6.288 19.397 6.312 ;
     RECT  19.213 38.208 19.397 39.384 ;
     RECT  19.333 4.56 19.621 4.584 ;
     RECT  19.573 35.328 19.667 35.352 ;
     RECT  19.397 38.736 19.717 39.384 ;
     RECT  19.141 0.192 19.763 1.704 ;
     RECT  19.717 38.736 19.763 39.624 ;
     RECT  19.763 39.6 19.859 39.624 ;
     RECT  19.621 3.984 19.901 4.584 ;
     RECT  19.901 4.56 19.937 4.584 ;
     RECT  19.813 15.984 20.009 16.008 ;
     RECT  19.187 41.52 20.197 42.6 ;
     RECT  20.149 14.832 20.297 14.856 ;
     RECT  20.197 41.232 20.365 42.6 ;
     RECT  20.221 7.344 20.389 7.368 ;
     RECT  20.365 41.232 20.531 42.648 ;
     RECT  20.531 42.192 20.627 42.648 ;
     RECT  20.677 9.12 20.765 9.144 ;
     RECT  20.389 7.344 20.801 7.416 ;
     RECT  19.763 0.192 20.965 1.224 ;
     RECT  20.627 42.192 21.625 42.6 ;
     RECT  21.625 42.192 21.637 42.84 ;
     RECT  21.637 3.792 21.661 3.816 ;
     RECT  20.965 41.04 21.661 41.064 ;
     RECT  21.637 42.096 21.661 42.84 ;
     RECT  20.801 7.344 21.685 7.368 ;
     RECT  21.637 38.4 21.685 38.424 ;
     RECT  20.797 35.904 21.733 35.928 ;
     RECT  20.965 0.192 21.848 1.752 ;
     RECT  21.661 3.792 21.848 4.008 ;
     RECT  21.685 6.864 21.848 7.368 ;
     RECT  20.773 9.168 21.848 9.192 ;
     RECT  20.869 12 21.848 12.024 ;
     RECT  21.229 14.736 21.848 14.76 ;
     RECT  21.733 35.904 21.848 36.408 ;
     RECT  21.685 38.256 21.848 38.424 ;
     RECT  21.661 41.04 21.848 42.84 ;
     RECT  21.848 0.192 21.971 42.84 ;
     RECT  21.971 0.192 22.144 42.6 ;
     RECT  22.144 3.888 22.241 3.912 ;
     RECT  22.144 6.864 22.277 7.368 ;
     RECT  22.144 25.056 22.451 26.232 ;
     RECT  22.144 41.04 22.457 42.6 ;
     RECT  22.457 41.04 22.643 41.064 ;
     RECT  22.144 0.192 22.673 1.224 ;
     RECT  22.144 38.784 22.739 38.808 ;
     RECT  22.457 42.192 23.029 42.6 ;
     RECT  22.451 25.728 23.075 26.232 ;
     RECT  22.144 35.328 23.315 35.352 ;
     RECT  23.365 4.704 23.501 4.728 ;
     RECT  23.461 38.736 23.603 38.76 ;
     RECT  22.277 7.344 23.653 7.368 ;
     RECT  23.029 42.192 23.747 43.08 ;
     RECT  23.701 38.448 23.753 38.472 ;
     RECT  22.144 2.304 23.789 2.904 ;
     RECT  23.713 33.408 23.795 33.432 ;
     RECT  23.749 13.104 23.825 13.128 ;
     RECT  23.653 6.864 23.845 7.368 ;
     RECT  23.821 31.344 23.891 31.368 ;
     RECT  23.845 6.336 23.933 7.368 ;
     RECT  23.281 40.464 23.987 40.488 ;
     RECT  24.037 38.208 24.083 38.232 ;
     RECT  22.673 0.192 24.133 1.176 ;
     RECT  24.037 30.768 24.149 30.792 ;
     RECT  23.933 6.864 24.257 7.368 ;
     RECT  24.517 35.904 24.581 35.928 ;
     RECT  23.789 2.88 24.613 2.904 ;
     RECT  24.433 15.408 24.617 15.432 ;
     RECT  24.649 41.04 24.901 41.064 ;
     RECT  24.613 2.88 24.905 2.952 ;
     RECT  24.901 41.04 24.997 41.16 ;
     RECT  23.747 42.192 24.997 42.6 ;
     RECT  24.997 41.04 25.049 42.6 ;
     RECT  25.049 41.04 25.085 41.16 ;
     RECT  24.709 4.56 25.229 4.584 ;
     RECT  25.085 41.04 25.549 41.064 ;
     RECT  24.905 2.928 25.661 2.952 ;
     RECT  25.549 40.464 25.715 41.064 ;
     RECT  25.573 37.008 25.765 37.032 ;
     RECT  25.765 37.008 25.811 37.224 ;
     RECT  25.477 39.36 25.813 39.384 ;
     RECT  25.189 6.288 25.861 6.312 ;
     RECT  24.257 7.344 25.861 7.368 ;
     RECT  25.813 38.448 25.877 39.384 ;
     RECT  25.861 36.432 25.949 36.456 ;
     RECT  25.877 38.784 26.003 39.384 ;
     RECT  24.133 0.192 26.021 1.224 ;
     RECT  25.049 42.336 26.089 42.6 ;
     RECT  26.053 13.104 26.129 13.128 ;
     RECT  25.861 6.288 26.237 7.368 ;
     RECT  22.144 17.856 26.245 17.88 ;
     RECT  26.245 17.856 26.341 18.264 ;
     RECT  25.715 41.04 26.377 41.064 ;
     RECT  26.089 42.192 26.377 42.6 ;
     RECT  26.021 0.192 26.489 1.176 ;
     RECT  26.725 15.984 26.965 16.008 ;
     RECT  26.341 17.088 26.965 18.264 ;
     RECT  26.377 41.04 26.965 42.6 ;
     RECT  26.489 0.288 27.248 1.176 ;
     RECT  27.013 3.408 27.248 3.432 ;
     RECT  26.821 4.656 27.248 4.68 ;
     RECT  26.237 6.864 27.248 7.368 ;
     RECT  27.109 10.512 27.248 10.536 ;
     RECT  26.953 14.256 27.248 14.28 ;
     RECT  26.965 15.984 27.248 18.264 ;
     RECT  26.533 19.392 27.248 19.416 ;
     RECT  23.075 25.728 27.248 25.752 ;
     RECT  26.629 28.512 27.248 28.536 ;
     RECT  26.485 37.584 27.248 37.608 ;
     RECT  26.003 38.784 27.248 38.808 ;
     RECT  27.061 39.888 27.248 39.912 ;
     RECT  26.965 41.04 27.248 42.84 ;
     RECT  27.248 0.288 27.493 42.84 ;
     RECT  27.493 0.192 27.544 42.84 ;
     RECT  27.544 33.552 27.683 34.056 ;
     RECT  27.544 42.192 27.709 42.84 ;
     RECT  27.544 35.904 27.749 37.608 ;
     RECT  27.749 35.904 27.779 35.928 ;
     RECT  27.709 42.192 27.827 42.888 ;
     RECT  27.544 24.768 27.923 25.992 ;
     RECT  27.544 30.288 27.929 30.312 ;
     RECT  27.544 10.848 27.965 10.872 ;
     RECT  27.544 6.864 28.037 6.888 ;
     RECT  27.544 3.408 28.181 3.432 ;
     RECT  27.544 38.784 28.211 39.384 ;
     RECT  27.544 0.192 28.289 1.752 ;
     RECT  27.749 37.056 28.307 37.608 ;
     RECT  27.544 4.56 28.361 4.632 ;
     RECT  27.923 24.768 28.397 24.792 ;
     RECT  27.544 41.04 28.403 41.112 ;
     RECT  28.211 38.784 28.499 38.808 ;
     RECT  27.544 14.832 28.505 14.856 ;
     RECT  28.403 41.088 28.595 41.112 ;
     RECT  28.361 4.608 28.685 4.632 ;
     RECT  27.683 34.032 28.787 34.056 ;
     RECT  27.827 42.192 28.897 42.6 ;
     RECT  28.825 10.752 28.937 10.776 ;
     RECT  28.897 41.424 28.979 42.6 ;
     RECT  28.289 0.192 29.009 1.224 ;
     RECT  28.933 12.528 29.045 12.552 ;
     RECT  29.317 36.432 29.401 36.456 ;
     RECT  29.317 2.88 29.441 2.904 ;
     RECT  29.401 36.384 29.459 36.456 ;
     RECT  29.009 0.24 29.477 1.224 ;
     RECT  28.741 37.632 29.653 37.656 ;
     RECT  29.509 32.496 29.657 32.52 ;
     RECT  29.653 37.632 29.939 38.232 ;
     RECT  29.869 39.6 29.941 39.624 ;
     RECT  29.941 37.584 29.987 37.608 ;
     RECT  29.477 0.24 29.989 1.176 ;
     RECT  29.941 38.784 30.035 39.624 ;
     RECT  29.617 41.04 30.085 41.064 ;
     RECT  28.979 42.192 30.085 42.6 ;
     RECT  30.035 38.784 30.131 38.808 ;
     RECT  29.605 14.256 30.197 14.28 ;
     RECT  30.085 41.04 30.227 42.6 ;
     RECT  29.893 6.96 30.269 6.984 ;
     RECT  29.459 36.432 30.323 36.456 ;
     RECT  29.509 5.136 30.593 5.16 ;
     RECT  29.989 0.192 30.661 1.176 ;
     RECT  30.469 2.304 30.661 2.328 ;
     RECT  30.227 42.192 30.707 42.6 ;
     RECT  27.544 16.368 30.757 16.392 ;
     RECT  30.707 42.336 30.757 42.6 ;
     RECT  30.841 19.968 30.899 19.992 ;
     RECT  30.841 32.496 30.899 32.52 ;
     RECT  30.757 42.336 30.947 42.888 ;
     RECT  30.661 0.192 30.989 2.328 ;
     RECT  30.913 33.024 30.995 33.048 ;
     RECT  30.947 42.576 31.141 42.888 ;
     RECT  31.141 42.576 31.165 42.984 ;
     RECT  31.165 36.384 31.235 36.408 ;
     RECT  31.165 42.576 31.235 43.08 ;
     RECT  30.757 16.368 31.285 16.536 ;
     RECT  31.237 38.208 31.313 38.232 ;
     RECT  31.285 16.272 31.331 16.536 ;
     RECT  30.227 41.04 31.379 41.064 ;
     RECT  30.589 6.864 31.385 6.888 ;
     RECT  31.489 41.232 31.571 41.256 ;
     RECT  31.705 41.52 31.921 41.544 ;
     RECT  31.235 42.576 31.921 42.6 ;
     RECT  30.989 0.192 32.293 1.752 ;
     RECT  31.429 36.432 32.293 36.456 ;
     RECT  31.921 41.52 32.341 42.6 ;
     RECT  32.341 41.52 32.393 43.08 ;
     RECT  32.393 41.52 32.435 42.984 ;
     RECT  32.293 0.192 32.485 2.328 ;
     RECT  32.389 11.136 32.497 11.16 ;
     RECT  32.497 10.944 32.533 11.16 ;
     RECT  27.923 25.968 32.533 25.992 ;
     RECT  31.561 39.6 32.533 39.624 ;
     RECT  32.485 0.192 32.648 2.904 ;
     RECT  31.525 4.56 32.648 4.584 ;
     RECT  32.533 10.944 32.648 11.736 ;
     RECT  31.237 13.104 32.648 13.128 ;
     RECT  32.137 14.832 32.648 14.856 ;
     RECT  31.331 16.272 32.648 16.296 ;
     RECT  31.813 17.664 32.648 17.688 ;
     RECT  32.533 25.728 32.648 25.992 ;
     RECT  32.533 31.44 32.648 31.464 ;
     RECT  32.293 35.904 32.648 36.456 ;
     RECT  32.533 39.504 32.648 39.624 ;
     RECT  32.435 41.52 32.648 42.888 ;
     RECT  32.648 0.192 32.723 42.888 ;
     RECT  32.723 0.192 32.944 42.792 ;
     RECT  32.944 2.88 33.005 2.904 ;
     RECT  32.944 28.272 33.041 28.296 ;
     RECT  32.944 0.192 33.059 1.272 ;
     RECT  32.944 13.68 33.059 13.704 ;
     RECT  32.944 30.24 33.059 31.56 ;
     RECT  32.944 39.504 33.059 39.528 ;
     RECT  32.944 41.232 33.059 42.792 ;
     RECT  33.059 30.72 33.107 31.56 ;
     RECT  32.944 11.136 33.221 11.16 ;
     RECT  32.944 25.728 33.635 25.992 ;
     RECT  33.059 0.192 34.013 1.176 ;
     RECT  33.059 41.232 34.013 42.6 ;
     RECT  34.013 42.192 34.067 42.6 ;
     RECT  32.944 5.712 34.157 5.736 ;
     RECT  34.067 42.192 34.193 42.36 ;
     RECT  34.189 38.736 34.259 38.76 ;
     RECT  34.405 10.272 34.553 10.296 ;
     RECT  34.369 39.6 34.585 39.624 ;
     RECT  34.585 39.6 34.643 39.912 ;
     RECT  34.643 39.6 34.739 39.624 ;
     RECT  34.693 4.56 34.913 4.584 ;
     RECT  34.189 41.04 35.129 41.208 ;
     RECT  35.129 41.088 35.161 41.208 ;
     RECT  34.193 42.192 35.161 42.216 ;
     RECT  35.077 1.728 35.165 1.752 ;
     RECT  35.173 14.256 35.237 14.28 ;
     RECT  35.161 41.088 35.269 42.216 ;
     RECT  34.013 0.192 35.365 0.696 ;
     RECT  35.377 30.24 35.507 30.264 ;
     RECT  35.365 0.192 35.669 1.224 ;
     RECT  35.269 41.088 35.699 42.6 ;
     RECT  34.597 13.104 35.921 13.128 ;
     RECT  35.461 3.408 35.993 3.432 ;
     RECT  35.699 41.472 36.179 42.6 ;
     RECT  32.944 16.272 36.229 16.296 ;
     RECT  36.229 15.408 36.317 16.296 ;
     RECT  36.421 20.544 36.569 20.568 ;
     RECT  36.179 42.192 36.661 42.6 ;
     RECT  35.669 0.192 36.709 1.176 ;
     RECT  36.709 0.192 36.821 1.752 ;
     RECT  36.661 42.192 36.851 43.08 ;
     RECT  36.637 7.728 36.889 7.752 ;
     RECT  36.851 42.336 36.947 43.08 ;
     RECT  36.349 39.36 36.961 39.384 ;
     RECT  36.317 16.272 37.037 16.296 ;
     RECT  36.961 39.36 37.043 39.624 ;
     RECT  36.637 36.432 37.105 36.456 ;
     RECT  37.105 35.904 37.213 36.456 ;
     RECT  37.213 35.904 37.501 37.224 ;
     RECT  36.947 42.576 37.525 43.08 ;
     RECT  37.525 42.576 37.613 43.128 ;
     RECT  37.613 42.576 37.619 42.984 ;
     RECT  37.105 16.32 37.621 16.344 ;
     RECT  37.537 40.464 37.717 40.488 ;
     RECT  37.717 40.464 37.813 41.064 ;
     RECT  33.635 25.968 37.861 25.992 ;
     RECT  36.821 0.192 37.909 1.224 ;
     RECT  37.861 25.584 38.005 25.992 ;
     RECT  37.909 0.192 38.048 1.272 ;
     RECT  36.889 6.864 38.048 7.752 ;
     RECT  37.573 10.896 38.048 10.92 ;
     RECT  37.621 16.32 38.048 17.112 ;
     RECT  36.325 18.816 38.048 18.84 ;
     RECT  37.861 21.216 38.048 21.24 ;
     RECT  38.005 25.584 38.048 26.04 ;
     RECT  37.717 33.024 38.048 33.048 ;
     RECT  37.501 35.904 38.048 37.56 ;
     RECT  37.381 38.736 38.048 38.808 ;
     RECT  37.813 40.464 38.048 41.544 ;
     RECT  37.619 42.576 38.048 42.84 ;
     RECT  38.048 0.192 38.099 42.84 ;
     RECT  38.099 0.192 38.225 42.792 ;
     RECT  38.225 0.192 38.344 42.6 ;
     RECT  38.344 16.272 38.405 17.112 ;
     RECT  38.344 2.832 38.483 2.856 ;
     RECT  38.344 30.24 38.531 30.84 ;
     RECT  38.531 30.816 38.585 30.84 ;
     RECT  38.344 14.832 38.621 14.856 ;
     RECT  38.344 38.736 38.675 39.384 ;
     RECT  38.344 18.816 38.729 18.84 ;
     RECT  38.344 0.192 38.765 1.752 ;
     RECT  38.344 7.728 38.801 7.896 ;
     RECT  38.344 12.528 39.269 12.552 ;
     RECT  38.344 26.016 39.373 26.04 ;
     RECT  39.373 25.68 39.413 26.04 ;
     RECT  39.337 3.408 39.443 3.432 ;
     RECT  38.344 21.219 39.589 21.237 ;
     RECT  39.413 25.68 39.635 25.704 ;
     RECT  39.481 35.904 39.731 35.928 ;
     RECT  38.765 0.192 39.781 1.176 ;
     RECT  39.805 34.032 39.829 34.056 ;
     RECT  39.781 0.192 39.845 1.224 ;
     RECT  39.829 34.032 39.875 34.92 ;
     RECT  38.344 41.04 40.115 42.6 ;
     RECT  38.675 39.36 40.211 39.384 ;
     RECT  40.357 13.104 40.493 13.128 ;
     RECT  40.921 6.864 41.033 6.888 ;
     RECT  40.645 33.072 41.105 33.096 ;
     RECT  40.115 41.04 41.363 41.064 ;
     RECT  39.845 0.192 41.413 1.176 ;
     RECT  41.317 6.288 41.509 6.312 ;
     RECT  40.837 39.888 41.555 39.912 ;
     RECT  41.413 0.192 41.573 1.272 ;
     RECT  41.509 5.712 41.609 6.312 ;
     RECT  41.609 6.288 41.645 6.312 ;
     RECT  39.589 28.8 41.645 28.824 ;
     RECT  41.797 14.832 41.861 14.856 ;
     RECT  38.801 7.872 41.989 7.896 ;
     RECT  40.115 42.192 42.131 42.6 ;
     RECT  42.131 42.24 42.227 42.6 ;
     RECT  42.227 42.336 42.323 42.6 ;
     RECT  41.989 7.44 42.437 7.896 ;
     RECT  42.323 42.576 42.437 42.6 ;
     RECT  42.469 38.736 42.613 38.76 ;
     RECT  42.437 7.872 42.757 7.896 ;
     RECT  42.565 41.04 42.757 41.064 ;
     RECT  42.613 38.736 43.045 39.384 ;
     RECT  43.045 38.736 43.153 39.912 ;
     RECT  41.573 0.192 43.237 1.176 ;
     RECT  43.237 0.192 43.448 1.272 ;
     RECT  43.333 3.984 43.448 4.008 ;
     RECT  42.757 7.872 43.448 7.992 ;
     RECT  38.405 16.272 43.448 16.296 ;
     RECT  42.661 19.968 43.448 19.992 ;
     RECT  39.589 21.219 43.448 22.2 ;
     RECT  43.369 25.488 43.448 25.512 ;
     RECT  39.875 34.896 43.448 34.92 ;
     RECT  42.829 35.904 43.448 35.928 ;
     RECT  43.153 38.208 43.448 39.912 ;
     RECT  42.757 41.04 43.448 41.256 ;
     RECT  43.297 42.768 43.448 42.792 ;
     RECT  43.448 0.192 43.744 42.792 ;
     RECT  43.744 0.192 43.805 2.088 ;
     RECT  43.744 25.2 43.805 25.512 ;
     RECT  43.805 25.2 43.841 25.224 ;
     RECT  43.744 3.408 43.907 3.96 ;
     RECT  43.744 41.232 43.955 42.792 ;
     RECT  43.805 0.24 44.021 2.088 ;
     RECT  43.907 3.936 44.237 3.96 ;
     RECT  43.744 37.2 44.291 37.224 ;
     RECT  43.955 41.232 44.339 42.648 ;
     RECT  43.744 13.104 44.561 13.128 ;
     RECT  43.744 38.208 44.561 38.808 ;
     RECT  44.021 0.24 44.633 1.752 ;
     RECT  43.744 7.968 44.723 7.992 ;
     RECT  43.744 16.272 44.723 16.296 ;
     RECT  44.633 0.24 44.773 1.272 ;
     RECT  43.744 5.616 44.777 5.64 ;
     RECT  44.339 42.192 44.915 42.648 ;
     RECT  43.744 21.219 45.101 22.056 ;
     RECT  44.561 38.784 45.313 38.808 ;
     RECT  45.253 41.04 45.317 41.064 ;
     RECT  45.301 36.384 45.353 36.408 ;
     RECT  44.773 0.192 45.587 1.272 ;
     RECT  43.744 34.896 45.677 34.92 ;
     RECT  45.445 17.664 45.965 17.688 ;
     RECT  44.915 42.192 46.021 42.6 ;
     RECT  46.021 42.192 46.069 42.984 ;
     RECT  45.925 2.304 46.109 2.328 ;
     RECT  45.313 38.784 46.177 39.384 ;
     RECT  46.177 38.736 46.397 39.384 ;
     RECT  46.885 37.584 46.937 37.608 ;
     RECT  46.033 36.432 46.979 36.456 ;
     RECT  43.744 10.56 46.981 10.584 ;
     RECT  46.397 38.736 47.149 38.952 ;
     RECT  47.077 6.288 47.153 6.312 ;
     RECT  47.149 38.208 47.219 38.952 ;
     RECT  45.587 0.192 47.257 1.176 ;
     RECT  47.173 13.68 47.261 13.704 ;
     RECT  47.257 0.192 47.315 1.272 ;
     RECT  46.981 10.56 47.369 10.872 ;
     RECT  46.573 41.04 47.513 41.064 ;
     RECT  47.557 37.056 47.621 37.128 ;
     RECT  47.219 38.736 47.653 38.952 ;
     RECT  47.653 38.736 47.725 39.624 ;
     RECT  47.725 38.736 47.795 39.912 ;
     RECT  47.315 0.192 47.801 1.176 ;
     RECT  47.369 10.56 47.801 10.584 ;
     RECT  47.749 12.528 47.837 12.552 ;
     RECT  47.845 3.408 47.977 3.432 ;
     RECT  46.069 42.192 48.053 43.08 ;
     RECT  48.053 42.192 48.083 42.984 ;
     RECT  47.621 37.104 48.085 37.128 ;
     RECT  47.977 3.36 48.133 3.432 ;
     RECT  48.133 2.88 48.193 3.432 ;
     RECT  48.083 42.192 48.661 42.888 ;
     RECT  47.801 0.192 48.848 1.128 ;
     RECT  48.193 2.256 48.848 3.432 ;
     RECT  48.325 4.56 48.848 4.584 ;
     RECT  48.421 20.064 48.848 20.088 ;
     RECT  45.101 21.219 48.848 21.237 ;
     RECT  48.013 30.432 48.848 30.456 ;
     RECT  48.085 37.104 48.848 37.608 ;
     RECT  47.795 38.736 48.848 39.384 ;
     RECT  48.661 41.52 48.848 42.888 ;
     RECT  48.848 0.192 49.043 42.888 ;
     RECT  49.043 0.192 49.144 42.6 ;
     RECT  49.144 6.24 49.283 6.312 ;
     RECT  49.144 41.04 49.493 42.6 ;
     RECT  49.144 0.192 49.565 1.176 ;
     RECT  49.493 42.192 49.619 42.6 ;
     RECT  49.619 42.24 49.715 42.6 ;
     RECT  49.715 42.336 49.961 42.6 ;
     RECT  49.961 42.576 50.069 42.6 ;
     RECT  49.565 0.528 50.099 1.176 ;
     RECT  49.283 6.288 50.141 6.312 ;
     RECT  49.493 41.04 50.177 41.16 ;
     RECT  50.099 0.528 50.195 0.6 ;
     RECT  50.177 41.136 50.195 41.16 ;
     RECT  49.144 4.56 50.213 4.584 ;
     RECT  50.195 0.528 50.321 0.552 ;
     RECT  49.144 3.408 50.573 3.432 ;
     RECT  49.144 21.219 54.248 21.237 ;
     RECT  54.248 0.528 54.352 42.672 ;
     RECT  54.352 0.798 54.544 42.402 ;
     RECT  54.544 21.219 59.648 21.237 ;
     RECT  59.648 0.528 59.752 42.672 ;
     RECT  59.752 0.798 59.944 42.402 ;
     RECT  59.944 21.216 60.041 21.336 ;
     RECT  60.041 21.315 61.909 21.333 ;
     RECT  61.909 21.168 63.457 21.333 ;
     RECT  63.457 21.168 63.497 21.48 ;
     RECT  63.497 21.168 65.048 21.477 ;
     RECT  65.048 0.528 65.152 42.672 ;
     RECT  65.152 0.798 65.344 42.402 ;
     RECT  65.344 21.168 70.448 21.477 ;
     RECT  70.448 0.528 70.552 42.672 ;
     RECT  70.552 0.798 70.744 42.402 ;
     RECT  70.744 21.168 75.848 21.477 ;
     RECT  75.848 0.528 75.952 42.672 ;
     RECT  75.952 0.798 76.144 42.402 ;
     RECT  79.945 1.248 79.981 1.272 ;
     RECT  79.981 1.152 80.197 1.272 ;
     RECT  80.197 0.528 80.521 1.272 ;
     RECT  80.233 42.192 80.629 42.216 ;
     RECT  80.341 25.056 80.965 25.08 ;
     RECT  80.629 41.616 80.965 42.216 ;
     RECT  80.821 37.68 81.061 37.704 ;
     RECT  80.521 0.192 81.109 1.272 ;
     RECT  81.109 0.192 81.248 1.56 ;
     RECT  80.305 2.88 81.248 2.904 ;
     RECT  76.144 21.168 81.248 21.477 ;
     RECT  81.109 22.8 81.248 22.824 ;
     RECT  80.965 24.48 81.248 25.08 ;
     RECT  80.149 26.16 81.248 26.184 ;
     RECT  81.061 37.632 81.248 37.704 ;
     RECT  80.917 40.464 81.248 40.488 ;
     RECT  80.965 41.616 81.248 42.888 ;
     RECT  81.248 0.192 81.443 42.888 ;
     RECT  81.443 0.192 81.544 42.552 ;
     RECT  81.544 41.28 81.641 42.552 ;
     RECT  81.544 37.008 81.677 37.656 ;
     RECT  81.544 0.192 81.683 1.704 ;
     RECT  81.544 2.88 81.731 2.904 ;
     RECT  81.544 38.736 81.779 38.856 ;
     RECT  81.641 41.28 81.779 42.504 ;
     RECT  81.544 5.136 81.827 5.208 ;
     RECT  81.827 5.184 81.923 5.208 ;
     RECT  81.779 38.736 81.965 38.76 ;
     RECT  81.544 30.192 82.001 30.216 ;
     RECT  81.677 37.008 82.037 37.032 ;
     RECT  81.544 6.768 82.145 6.792 ;
     RECT  81.683 0.192 82.307 1.272 ;
     RECT  81.779 41.28 82.645 42.408 ;
     RECT  82.645 41.04 82.649 42.408 ;
     RECT  82.573 34.896 82.741 34.92 ;
     RECT  82.649 42.096 82.979 42.408 ;
     RECT  82.897 6.864 83.009 6.888 ;
     RECT  82.307 0.192 83.075 1.224 ;
     RECT  83.221 3.984 83.293 4.008 ;
     RECT  82.649 41.04 83.317 41.064 ;
     RECT  83.293 3.984 83.363 4.056 ;
     RECT  83.413 2.88 83.477 2.904 ;
     RECT  83.075 0.528 83.555 1.224 ;
     RECT  82.979 42.192 83.555 42.408 ;
     RECT  83.555 1.104 83.581 1.224 ;
     RECT  82.741 34.896 83.605 35.352 ;
     RECT  83.605 5.136 83.657 5.16 ;
     RECT  83.317 40.464 83.729 41.064 ;
     RECT  83.653 38.784 83.765 38.808 ;
     RECT  83.729 41.04 83.833 41.064 ;
     RECT  83.581 1.104 83.843 1.704 ;
     RECT  83.843 1.104 83.939 1.32 ;
     RECT  83.125 31.872 83.981 31.896 ;
     RECT  83.363 3.984 84.035 4.008 ;
     RECT  83.555 42.192 84.085 42.36 ;
     RECT  83.833 41.04 84.161 41.112 ;
     RECT  84.085 42.096 84.181 42.36 ;
     RECT  84.181 41.28 84.377 42.36 ;
     RECT  84.277 29.616 84.449 29.64 ;
     RECT  83.605 34.896 84.469 35.928 ;
     RECT  83.939 1.152 84.611 1.32 ;
     RECT  84.469 34.896 84.665 36.456 ;
     RECT  84.611 1.152 84.949 1.224 ;
     RECT  84.565 25.632 84.953 25.656 ;
     RECT  84.665 36.384 85.097 36.456 ;
     RECT  85.129 30.72 85.241 30.744 ;
     RECT  85.097 36.432 85.241 36.456 ;
     RECT  84.377 42.096 85.429 42.36 ;
     RECT  85.429 41.424 85.493 42.36 ;
     RECT  84.949 0.192 85.667 1.224 ;
     RECT  85.493 42.096 85.957 42.36 ;
     RECT  85.957 42.096 86.033 43.08 ;
     RECT  86.033 42.096 86.051 42.984 ;
     RECT  84.665 34.896 86.197 34.92 ;
     RECT  86.101 26.208 86.293 26.232 ;
     RECT  81.544 21.168 86.389 21.477 ;
     RECT  86.389 20.736 86.533 21.477 ;
     RECT  85.667 0.192 86.648 1.176 ;
     RECT  85.813 2.88 86.648 2.904 ;
     RECT  86.389 3.984 86.648 4.008 ;
     RECT  86.101 5.136 86.648 5.16 ;
     RECT  85.921 6.288 86.648 6.312 ;
     RECT  81.544 8.16 86.648 8.184 ;
     RECT  86.245 9.696 86.648 9.72 ;
     RECT  86.137 11.904 86.648 11.928 ;
     RECT  86.533 20.352 86.648 21.477 ;
     RECT  83.437 22.752 86.648 22.776 ;
     RECT  85.957 24.192 86.648 24.216 ;
     RECT  86.293 25.296 86.648 26.232 ;
     RECT  86.485 29.616 86.648 29.64 ;
     RECT  86.197 34.896 86.648 35.448 ;
     RECT  86.425 36.72 86.648 36.744 ;
     RECT  85.621 41.04 86.648 41.064 ;
     RECT  86.051 42.096 86.648 42.792 ;
     RECT  86.648 0.192 86.944 42.792 ;
     RECT  86.944 3.984 87.059 4.152 ;
     RECT  86.944 34.896 87.059 35.448 ;
     RECT  87.059 35.424 87.077 35.448 ;
     RECT  86.944 17.52 87.107 17.64 ;
     RECT  86.944 21.168 87.107 21.48 ;
     RECT  86.944 41.616 87.113 42.792 ;
     RECT  86.944 8.16 87.155 8.424 ;
     RECT  86.944 15.984 87.155 16.008 ;
     RECT  86.944 29.952 87.155 29.976 ;
     RECT  86.944 23.328 87.203 23.448 ;
     RECT  87.113 41.616 87.203 42.744 ;
     RECT  87.107 17.52 87.251 17.544 ;
     RECT  86.944 18.816 87.251 18.84 ;
     RECT  86.944 26.496 87.251 26.904 ;
     RECT  87.203 23.424 87.257 23.448 ;
     RECT  86.944 0.192 87.971 1.704 ;
     RECT  87.059 3.984 88.085 4.008 ;
     RECT  87.203 41.616 88.085 42.312 ;
     RECT  88.009 14.832 88.121 14.856 ;
     RECT  88.213 5.136 88.301 5.16 ;
     RECT  88.117 31.872 88.309 31.896 ;
     RECT  87.973 6.816 88.355 6.84 ;
     RECT  88.213 23.328 88.445 23.352 ;
     RECT  88.309 31.824 88.445 31.896 ;
     RECT  87.251 26.88 88.477 26.904 ;
     RECT  88.477 26.88 88.517 27.096 ;
     RECT  88.021 29.376 88.517 29.4 ;
     RECT  88.445 31.872 88.517 31.896 ;
     RECT  88.693 39.888 88.805 39.912 ;
     RECT  88.801 7.392 88.913 7.416 ;
     RECT  87.971 0.192 88.931 1.224 ;
     RECT  88.405 2.88 89.017 2.904 ;
     RECT  88.789 6.24 89.057 6.264 ;
     RECT  89.017 2.88 89.123 3.432 ;
     RECT  88.085 41.616 89.173 42.264 ;
     RECT  89.233 13.056 89.315 13.08 ;
     RECT  89.123 3.408 89.411 3.432 ;
     RECT  89.269 35.904 89.489 35.928 ;
     RECT  89.173 41.568 89.489 42.264 ;
     RECT  89.449 3.984 89.507 4.008 ;
     RECT  89.489 41.808 89.603 42.264 ;
     RECT  87.155 8.4 89.701 8.424 ;
     RECT  89.701 8.4 89.773 8.568 ;
     RECT  89.749 37.584 89.881 37.608 ;
     RECT  89.701 6.288 89.891 6.312 ;
     RECT  89.773 8.4 89.987 8.616 ;
     RECT  89.881 37.584 89.987 38.232 ;
     RECT  89.987 37.584 89.993 37.608 ;
     RECT  89.845 40.464 90.061 40.488 ;
     RECT  90.061 39.888 90.065 40.488 ;
     RECT  90.025 2.256 90.083 2.28 ;
     RECT  89.987 8.4 90.137 8.472 ;
     RECT  90.065 39.888 90.179 39.912 ;
     RECT  90.133 5.136 90.209 5.16 ;
     RECT  90.229 5.184 90.281 5.208 ;
     RECT  88.931 0.192 90.349 0.6 ;
     RECT  88.517 27.072 90.517 27.096 ;
     RECT  89.603 41.808 90.613 42.216 ;
     RECT  90.325 29.376 90.641 29.4 ;
     RECT  90.613 41.808 90.677 42.312 ;
     RECT  90.517 26.208 91.001 27.096 ;
     RECT  90.709 37.008 91.037 37.032 ;
     RECT  90.349 0.192 91.331 1.224 ;
     RECT  90.677 41.808 91.381 42.216 ;
     RECT  91.381 41.616 91.573 42.216 ;
     RECT  91.321 6.24 91.609 6.264 ;
     RECT  91.753 3.984 91.813 4.008 ;
     RECT  91.573 41.04 91.813 42.216 ;
     RECT  91.609 5.712 91.825 6.264 ;
     RECT  91.813 3.984 91.861 4.152 ;
     RECT  90.997 29.088 91.909 29.112 ;
     RECT  91.813 41.04 91.909 42.84 ;
     RECT  91.331 0.288 92.048 1.224 ;
     RECT  91.381 2.88 92.048 2.904 ;
     RECT  91.861 3.984 92.048 4.344 ;
     RECT  91.825 5.712 92.048 6.84 ;
     RECT  90.137 8.448 92.048 8.472 ;
     RECT  91.429 10.848 92.048 10.872 ;
     RECT  87.107 21.168 92.048 21.192 ;
     RECT  91.897 22.8 92.048 22.824 ;
     RECT  91.001 27.072 92.048 27.096 ;
     RECT  91.909 28.464 92.048 29.112 ;
     RECT  91.813 31.392 92.048 31.416 ;
     RECT  91.093 38.16 92.048 38.184 ;
     RECT  91.909 41.04 92.048 42.888 ;
     RECT  92.048 0.288 92.099 42.888 ;
     RECT  92.099 0.288 92.195 42.84 ;
     RECT  92.195 0.288 92.344 42.552 ;
     RECT  92.344 0.288 92.437 1.224 ;
     RECT  92.344 31.392 92.477 31.416 ;
     RECT  92.344 26.784 92.693 27.096 ;
     RECT  92.344 41.376 92.801 42.552 ;
     RECT  92.437 0.192 92.873 1.224 ;
     RECT  92.344 2.88 93.251 3.432 ;
     RECT  92.801 41.376 93.337 42.408 ;
     RECT  93.251 2.88 93.347 2.904 ;
     RECT  92.344 17.76 93.443 17.784 ;
     RECT  93.337 41.04 93.923 42.408 ;
     RECT  93.949 6.24 94.019 6.264 ;
     RECT  93.923 41.04 94.061 42.264 ;
     RECT  92.873 0.192 94.129 1.176 ;
     RECT  92.693 27.072 94.381 27.096 ;
     RECT  94.069 39.36 94.385 39.384 ;
     RECT  94.129 0.192 94.403 1.224 ;
     RECT  94.381 26.784 94.493 27.096 ;
     RECT  94.165 36.432 94.529 36.456 ;
     RECT  94.061 41.04 94.529 42.216 ;
     RECT  94.529 41.04 94.565 41.064 ;
     RECT  94.777 10.8 94.883 10.824 ;
     RECT  94.777 14.832 94.889 14.856 ;
     RECT  94.549 33.6 94.889 33.624 ;
     RECT  94.529 42.192 95.029 42.216 ;
     RECT  95.125 38.208 95.177 38.232 ;
     RECT  94.933 25.056 95.213 25.08 ;
     RECT  94.741 39.888 95.213 40.2 ;
     RECT  95.029 42.192 95.281 42.264 ;
     RECT  94.403 0.192 95.389 1.176 ;
     RECT  94.837 35.856 95.429 35.88 ;
     RECT  95.389 0.192 95.459 1.512 ;
     RECT  95.281 42.192 95.461 42.312 ;
     RECT  95.497 3.984 95.555 4.008 ;
     RECT  95.461 42.192 95.555 42.36 ;
     RECT  95.213 39.888 95.573 39.912 ;
     RECT  95.459 0.192 95.747 1.224 ;
     RECT  95.605 25.872 95.789 25.896 ;
     RECT  94.957 2.88 95.861 2.904 ;
     RECT  95.555 42.192 95.989 42.216 ;
     RECT  95.701 31.872 96.113 31.896 ;
     RECT  96.037 5.136 96.227 5.16 ;
     RECT  96.181 36.432 96.257 36.456 ;
     RECT  95.989 41.808 96.565 42.216 ;
     RECT  96.565 41.808 96.757 42.264 ;
     RECT  96.949 25.632 97.045 25.656 ;
     RECT  92.344 8.448 97.117 8.472 ;
     RECT  96.469 5.712 97.261 5.736 ;
     RECT  96.373 3.408 97.285 3.48 ;
     RECT  96.757 41.376 97.285 42.264 ;
     RECT  97.285 10.896 97.333 10.92 ;
     RECT  97.285 23.904 97.333 23.928 ;
     RECT  95.747 0.192 97.448 1.176 ;
     RECT  97.285 2.88 97.448 3.48 ;
     RECT  97.261 5.712 97.448 6.216 ;
     RECT  97.117 7.968 97.448 8.472 ;
     RECT  97.333 10.896 97.448 11.064 ;
     RECT  97.333 15.984 97.448 16.008 ;
     RECT  95.101 18.816 97.448 18.84 ;
     RECT  92.344 21.168 97.448 21.192 ;
     RECT  97.333 23.328 97.448 23.928 ;
     RECT  97.045 25.44 97.448 25.656 ;
     RECT  94.493 27.072 97.448 27.096 ;
     RECT  97.237 36.432 97.448 36.456 ;
     RECT  95.893 38.784 97.448 38.808 ;
     RECT  97.141 39.84 97.448 39.864 ;
     RECT  97.285 41.376 97.448 42.792 ;
     RECT  97.448 0.192 97.744 42.792 ;
     RECT  97.744 41.04 97.765 42.792 ;
     RECT  97.744 39.888 97.859 39.912 ;
     RECT  97.744 6.288 98.003 6.312 ;
     RECT  97.744 2.88 98.051 4.056 ;
     RECT  97.744 36.048 98.051 37.176 ;
     RECT  97.765 41.04 98.051 42.984 ;
     RECT  97.744 23.904 98.057 23.928 ;
     RECT  98.051 36.048 98.129 36.984 ;
     RECT  98.051 2.88 98.531 3.432 ;
     RECT  97.744 14.832 98.597 14.856 ;
     RECT  97.744 33.648 98.597 33.672 ;
     RECT  98.129 36.96 98.597 36.984 ;
     RECT  97.744 27.072 98.819 27.096 ;
     RECT  98.773 30.48 98.819 30.504 ;
     RECT  97.744 38.784 98.819 38.808 ;
     RECT  98.531 3.408 99.011 3.432 ;
     RECT  98.051 41.04 99.299 42.648 ;
     RECT  99.169 14.736 99.353 14.76 ;
     RECT  99.349 3.984 99.395 4.008 ;
     RECT  99.601 6.24 99.683 6.888 ;
     RECT  99.683 6.864 99.713 6.888 ;
     RECT  98.773 35.952 99.733 35.976 ;
     RECT  99.637 2.256 99.779 2.28 ;
     RECT  99.445 25.872 99.785 25.896 ;
     RECT  99.733 35.952 99.785 36.456 ;
     RECT  99.299 41.04 99.829 42.264 ;
     RECT  99.829 40.416 100.001 42.264 ;
     RECT  99.997 34.752 100.145 34.776 ;
     RECT  100.069 5.712 100.163 5.736 ;
     RECT  99.997 14.832 100.181 14.856 ;
     RECT  100.001 41.04 100.217 42.264 ;
     RECT  97.744 0.192 100.309 1.176 ;
     RECT  100.309 0.192 100.433 1.752 ;
     RECT  100.433 0.192 100.451 1.272 ;
     RECT  100.609 10.8 100.793 10.824 ;
     RECT  100.753 33.552 100.835 33.576 ;
     RECT  100.217 41.616 100.969 42.264 ;
     RECT  99.785 35.952 101.365 35.976 ;
     RECT  98.773 24.816 101.405 24.84 ;
     RECT  100.969 41.616 101.557 42.312 ;
     RECT  101.653 3.984 101.699 4.008 ;
     RECT  101.653 39.888 101.699 39.912 ;
     RECT  100.501 2.88 101.801 2.904 ;
     RECT  101.557 41.568 101.845 42.312 ;
     RECT  100.451 1.152 102.229 1.272 ;
     RECT  102.325 31.344 102.613 31.368 ;
     RECT  101.365 35.856 102.661 35.976 ;
     RECT  101.845 41.568 102.661 42.648 ;
     RECT  102.445 5.136 102.709 5.16 ;
     RECT  102.697 19.68 102.709 19.704 ;
     RECT  97.744 21.168 102.709 21.192 ;
     RECT  102.661 41.568 102.709 42.792 ;
     RECT  102.229 0.192 102.848 1.272 ;
     RECT  102.709 5.136 102.848 5.208 ;
     RECT  101.365 6.288 102.848 6.312 ;
     RECT  97.744 15.984 102.848 16.008 ;
     RECT  102.517 18.192 102.848 18.216 ;
     RECT  102.709 19.68 102.848 21.192 ;
     RECT  102.085 26.688 102.848 26.712 ;
     RECT  102.613 30.384 102.848 31.368 ;
     RECT  102.661 35.328 102.848 35.976 ;
     RECT  102.709 41.136 102.848 42.792 ;
     RECT  102.848 0.192 102.997 42.792 ;
     RECT  102.997 0.192 103.144 42.84 ;
     RECT  103.144 41.04 103.637 42.84 ;
     RECT  103.144 10.8 103.673 10.824 ;
     RECT  103.144 6.864 103.745 6.888 ;
     RECT  103.637 41.04 103.745 42.648 ;
     RECT  103.745 41.616 104.069 42.648 ;
     RECT  103.144 0.192 104.099 1.272 ;
     RECT  104.099 0.192 104.195 0.552 ;
     RECT  104.137 1.68 104.195 1.704 ;
     RECT  103.144 39.888 104.195 39.912 ;
     RECT  104.137 34.8 104.285 34.824 ;
     RECT  104.497 2.88 104.579 2.904 ;
     RECT  104.069 41.616 104.717 42.264 ;
     RECT  104.677 3.984 104.771 4.008 ;
     RECT  104.717 41.808 104.789 42.264 ;
     RECT  104.245 39.216 104.825 39.48 ;
     RECT  104.825 39.36 104.933 39.48 ;
     RECT  104.789 41.808 105.059 42.216 ;
     RECT  104.195 0.192 105.181 0.264 ;
     RECT  105.253 40.464 105.347 40.488 ;
     RECT  105.181 0.192 105.433 0.36 ;
     RECT  105.301 5.136 105.433 5.16 ;
     RECT  104.605 6.816 105.443 6.84 ;
     RECT  105.361 34.176 105.443 34.2 ;
     RECT  104.821 35.904 105.493 35.928 ;
     RECT  105.433 5.136 105.539 5.544 ;
     RECT  105.685 38.16 105.761 38.184 ;
     RECT  105.493 35.904 105.781 36.456 ;
     RECT  105.539 5.136 105.827 5.16 ;
     RECT  104.933 39.36 105.833 39.384 ;
     RECT  105.781 35.856 105.877 36.456 ;
     RECT  105.877 35.808 106.013 36.456 ;
     RECT  105.059 42.048 106.069 42.216 ;
     RECT  106.013 35.808 106.085 35.88 ;
     RECT  106.085 35.808 106.157 35.832 ;
     RECT  106.069 42.048 106.165 42.264 ;
     RECT  106.165 41.616 106.261 42.264 ;
     RECT  106.225 38.736 106.337 38.76 ;
     RECT  105.433 0.192 106.403 1.176 ;
     RECT  106.261 41.616 106.517 42.408 ;
     RECT  106.517 41.616 106.553 42.312 ;
     RECT  106.549 31.872 106.585 31.896 ;
     RECT  106.553 41.616 106.589 42.216 ;
     RECT  106.585 31.44 106.625 31.896 ;
     RECT  106.549 4.56 106.661 4.584 ;
     RECT  106.645 6.288 106.697 6.312 ;
     RECT  106.403 0.192 106.877 0.216 ;
     RECT  106.625 31.44 107.021 31.848 ;
     RECT  106.741 41.376 107.165 41.4 ;
     RECT  107.021 31.824 107.273 31.848 ;
     RECT  103.144 21.168 108.248 21.192 ;
     RECT  108.248 0.528 108.352 42.672 ;
     RECT  108.352 0.798 108.544 42.402 ;
     RECT  108.544 21.168 112.355 21.192 ;
     RECT  112.849 41.76 113.648 41.784 ;
     RECT  113.648 0.528 113.752 42.672 ;
     RECT  113.752 0.798 113.944 42.402 ;
     RECT  119.048 0.528 119.152 42.672 ;
     RECT  119.152 0.798 119.344 42.402 ;
    LAYER M5 ;
     RECT  80.16 0.144 106.776 0.227 ;
     RECT  17.328 0.144 50.184 0.517 ;
     RECT  16.44 0.517 50.184 0.611 ;
     RECT  0.24 0.517 0.36 0.787 ;
     RECT  5.64 0.517 5.76 0.787 ;
     RECT  11.04 0.517 11.16 0.787 ;
     RECT  54.24 0.517 54.36 0.787 ;
     RECT  59.64 0.517 59.76 0.787 ;
     RECT  65.04 0.517 65.16 0.787 ;
     RECT  70.44 0.517 70.56 0.787 ;
     RECT  75.84 0.517 75.96 0.787 ;
     RECT  108.24 0.517 108.36 0.787 ;
     RECT  113.64 0.517 113.76 0.787 ;
     RECT  119.04 0.517 119.16 0.787 ;
     RECT  16.44 0.611 50.088 1.187 ;
     RECT  80.16 0.227 106.68 1.187 ;
     RECT  80.256 1.187 106.68 1.235 ;
     RECT  80.256 1.235 84.6 1.283 ;
     RECT  91.392 1.235 106.68 1.283 ;
     RECT  83.232 1.283 84.6 1.331 ;
     RECT  16.44 1.187 45.96 1.763 ;
     RECT  16.44 1.763 44.232 2.339 ;
     RECT  45.456 1.763 45.96 2.339 ;
     RECT  16.44 2.339 29.928 2.915 ;
     RECT  80.352 1.283 81.912 2.915 ;
     RECT  85.824 1.235 90.264 2.915 ;
     RECT  91.392 1.283 103.152 2.915 ;
     RECT  30.96 2.339 44.232 3.443 ;
     RECT  91.488 2.915 100.152 3.443 ;
     RECT  83.232 1.331 84.024 4.019 ;
     RECT  93.408 3.443 98.04 4.019 ;
     RECT  99.36 3.443 100.152 4.019 ;
     RECT  83.328 4.019 83.64 4.067 ;
     RECT  96.192 4.019 98.04 4.067 ;
     RECT  23.376 2.915 29.928 4.595 ;
     RECT  25.2 4.595 29.928 4.643 ;
     RECT  23.376 4.595 23.88 4.739 ;
     RECT  83.616 4.067 83.64 5.171 ;
     RECT  96.192 4.067 97.992 5.171 ;
     RECT  104.16 1.283 106.68 5.171 ;
     RECT  81.12 2.915 81.912 5.219 ;
     RECT  86.016 2.915 90.264 5.219 ;
     RECT  104.16 5.171 105.528 5.555 ;
     RECT  40.368 3.443 44.232 5.605 ;
     RECT  45.456 2.339 45.48 5.605 ;
     RECT  30.96 3.443 39.24 5.747 ;
     RECT  96.576 5.171 97.992 5.747 ;
     RECT  99.648 4.019 100.152 5.747 ;
     RECT  93.408 4.019 94.872 6.275 ;
     RECT  99.648 5.747 99.672 6.275 ;
     RECT  16.44 2.915 22.152 6.323 ;
     RECT  25.2 4.643 27.912 6.323 ;
     RECT  40.368 5.605 45.48 6.323 ;
     RECT  46.992 1.187 49.896 6.323 ;
     RECT  86.016 5.219 89.976 6.323 ;
     RECT  97.152 5.747 97.992 6.323 ;
     RECT  101.376 2.915 103.152 6.323 ;
     RECT  106.656 5.171 106.68 6.323 ;
     RECT  23.664 4.739 23.88 6.371 ;
     RECT  86.208 6.323 89.976 6.851 ;
     RECT  104.16 5.555 105.432 6.851 ;
     RECT  23.664 6.371 23.784 6.899 ;
     RECT  25.872 6.323 27.912 6.899 ;
     RECT  30.96 5.747 32.952 6.899 ;
     RECT  28.944 4.643 29.928 6.995 ;
     RECT  97.152 6.323 97.848 8.003 ;
     RECT  97.248 8.003 97.848 8.051 ;
     RECT  88.8 6.851 89.976 8.627 ;
     RECT  19.824 6.323 22.152 9.203 ;
     RECT  16.44 6.323 17.352 9.731 ;
     RECT  34.416 5.747 39.24 10.307 ;
     RECT  31.248 6.899 32.952 10.805 ;
     RECT  94.848 6.275 94.872 10.835 ;
     RECT  18.768 6.323 18.792 10.883 ;
     RECT  26.064 6.899 27.672 10.883 ;
     RECT  46.992 6.323 49.272 10.883 ;
     RECT  91.488 3.443 92.352 10.883 ;
     RECT  97.296 8.051 97.848 10.931 ;
     RECT  86.208 6.851 87.192 11.939 ;
     RECT  20.88 9.203 22.152 12.035 ;
     RECT  28.944 6.995 29.64 12.563 ;
     RECT  34.608 10.307 39.24 12.563 ;
     RECT  47.184 10.883 49.272 12.563 ;
     RECT  88.8 8.627 89.304 13.091 ;
     RECT  23.76 6.899 23.784 13.139 ;
     RECT  26.064 10.883 27.552 13.139 ;
     RECT  31.248 10.805 33.048 13.139 ;
     RECT  34.608 12.563 38.664 13.139 ;
     RECT  40.368 6.323 40.68 13.139 ;
     RECT  31.824 13.139 33.048 13.715 ;
     RECT  47.184 12.563 47.208 13.715 ;
     RECT  29.616 12.563 29.64 14.291 ;
     RECT  35.184 13.139 35.208 14.291 ;
     RECT  41.808 6.323 45.48 14.867 ;
     RECT  36.24 13.139 38.664 15.443 ;
     RECT  19.824 9.203 19.848 16.019 ;
     RECT  31.824 13.715 32.952 16.261 ;
     RECT  42.672 14.867 45.48 16.307 ;
     RECT  31.296 16.261 32.952 16.357 ;
     RECT  30.768 16.357 32.952 16.547 ;
     RECT  86.64 11.939 87.192 17.509 ;
     RECT  30.864 16.547 32.952 17.699 ;
     RECT  45.456 16.307 45.48 17.699 ;
     RECT  93.408 6.275 93.432 17.795 ;
     RECT  102.84 6.323 103.152 18.181 ;
     RECT  26.256 13.139 27.552 18.275 ;
     RECT  36.336 15.443 38.664 18.851 ;
     RECT  86.64 17.509 87.24 18.851 ;
     RECT  97.344 10.931 97.848 18.851 ;
     RECT  26.544 18.275 27.552 19.427 ;
     RECT  30.864 17.699 30.888 20.003 ;
     RECT  42.672 16.307 43.752 20.003 ;
     RECT  48.432 12.563 49.272 20.099 ;
     RECT  86.64 18.851 87.192 20.341 ;
     RECT  36.432 18.851 36.456 20.579 ;
     RECT  86.544 20.341 87.192 20.725 ;
     RECT  37.875 18.851 38.568 21.205 ;
     RECT  86.4 20.725 87.192 22.741 ;
     RECT  81.12 5.219 81.552 22.835 ;
     RECT  88.8 13.091 88.824 23.317 ;
     RECT  97.44 18.851 97.848 23.317 ;
     RECT  97.344 23.317 97.848 23.893 ;
     RECT  86.304 22.741 87.192 24.181 ;
     RECT  81.24 22.835 81.552 24.469 ;
     RECT  26.64 19.427 27.552 24.757 ;
     RECT  97.296 23.893 97.848 24.805 ;
     RECT  21.84 12.035 22.152 25.045 ;
     RECT  80.976 24.469 81.552 25.045 ;
     RECT  97.296 24.805 98.808 25.429 ;
     RECT  37.872 21.205 38.568 25.619 ;
     RECT  97.056 25.429 98.808 25.621 ;
     RECT  32.64 17.699 32.952 25.717 ;
     RECT  94.944 25.045 94.968 25.861 ;
     RECT  96.96 25.621 98.808 25.861 ;
     RECT  32.544 25.717 33.624 26.003 ;
     RECT  80.352 25.045 81.552 26.149 ;
     RECT  21.84 25.045 22.44 26.197 ;
     RECT  85.968 24.181 87.192 26.485 ;
     RECT  85.968 26.485 87.24 26.771 ;
     RECT  92.04 10.883 92.352 28.453 ;
     RECT  26.64 24.757 28.344 28.547 ;
     RECT  39.6 22.165 39.624 28.789 ;
     RECT  40.656 13.139 40.68 28.789 ;
     RECT  39.6 28.789 40.68 28.835 ;
     RECT  90.528 26.197 90.552 29.077 ;
     RECT  91.92 28.453 92.352 29.077 ;
     RECT  85.968 26.771 87.192 29.365 ;
     RECT  88.224 23.317 88.824 29.365 ;
     RECT  90.528 29.077 92.352 29.365 ;
     RECT  84.576 25.621 84.6 29.605 ;
     RECT  80.16 26.149 81.552 30.181 ;
     RECT  32.64 26.003 32.952 30.229 ;
     RECT  48.84 20.099 49.272 30.421 ;
     RECT  32.64 30.229 33.048 30.709 ;
     RECT  38.04 25.619 38.568 30.851 ;
     RECT  21.84 26.197 23.064 31.333 ;
     RECT  102.528 18.181 103.152 31.333 ;
     RECT  32.64 30.709 33.096 31.571 ;
     RECT  84.288 29.605 84.6 31.861 ;
     RECT  94.944 25.861 95.64 31.861 ;
     RECT  106.656 31.813 106.68 31.861 ;
     RECT  30.864 32.485 30.888 33.013 ;
     RECT  38.04 30.851 38.52 33.013 ;
     RECT  39.84 28.835 40.68 33.107 ;
     RECT  94.944 31.861 95.736 33.589 ;
     RECT  27.24 28.547 28.344 34.021 ;
     RECT  29.52 32.485 29.544 34.021 ;
     RECT  39.84 33.107 39.864 34.931 ;
     RECT  80.16 30.181 81.912 35.317 ;
     RECT  83.136 31.861 84.6 35.317 ;
     RECT  105.408 34.165 105.432 35.797 ;
     RECT  106.56 31.861 106.68 35.797 ;
     RECT  100.8 33.541 100.824 35.845 ;
     RECT  102.336 31.333 103.152 35.845 ;
     RECT  16.44 9.731 16.752 35.893 ;
     RECT  21.84 31.333 23.88 35.893 ;
     RECT  32.64 31.571 32.952 35.893 ;
     RECT  37.728 33.013 38.52 35.893 ;
     RECT  43.44 20.003 43.752 35.893 ;
     RECT  85.968 29.365 88.824 35.893 ;
     RECT  104.16 6.851 104.184 35.893 ;
     RECT  105.408 35.797 106.68 35.893 ;
     RECT  16.44 35.893 17.544 35.941 ;
     RECT  30.864 33.013 30.984 36.373 ;
     RECT  80.16 35.317 84.6 36.373 ;
     RECT  27.24 34.021 29.544 36.421 ;
     RECT  30.864 36.373 31.224 36.421 ;
     RECT  32.304 35.893 32.952 36.421 ;
     RECT  37.2 35.893 38.52 36.421 ;
     RECT  45.312 36.373 45.336 36.421 ;
     RECT  94.56 33.589 95.736 36.421 ;
     RECT  96.96 25.861 99.48 36.421 ;
     RECT  16.44 35.941 17.64 36.469 ;
     RECT  19.632 35.317 19.656 36.661 ;
     RECT  16.44 36.469 17.736 36.997 ;
     RECT  25.872 36.421 25.896 36.997 ;
     RECT  45.312 36.421 46.968 37.045 ;
     RECT  48.048 30.421 49.272 37.045 ;
     RECT  42.864 35.893 43.752 37.189 ;
     RECT  25.584 36.997 25.896 37.573 ;
     RECT  27.24 36.421 32.952 37.573 ;
     RECT  85.968 35.893 89.304 37.573 ;
     RECT  90.336 29.365 92.352 37.573 ;
     RECT  25.584 37.573 32.952 37.667 ;
     RECT  16.44 36.997 18.024 38.197 ;
     RECT  19.008 36.661 19.656 38.197 ;
     RECT  42.864 37.189 44.28 38.197 ;
     RECT  45.312 37.045 49.272 38.197 ;
     RECT  16.44 38.197 19.656 38.725 ;
     RECT  36.672 36.421 38.52 38.725 ;
     RECT  42.864 38.197 49.272 38.725 ;
     RECT  25.584 37.667 28.344 38.773 ;
     RECT  29.328 37.667 32.952 38.773 ;
     RECT  20.88 35.893 24.552 39.349 ;
     RECT  25.584 38.773 32.952 39.349 ;
     RECT  35.472 30.229 35.496 39.349 ;
     RECT  36.672 38.725 38.664 39.349 ;
     RECT  39.696 35.893 39.72 39.349 ;
     RECT  94.176 36.421 99.768 39.349 ;
     RECT  20.88 39.349 32.952 39.493 ;
     RECT  16.44 38.725 19.752 39.589 ;
     RECT  34.224 38.725 34.248 39.589 ;
     RECT  35.472 39.349 40.2 39.589 ;
     RECT  34.224 39.589 40.2 39.877 ;
     RECT  42.48 38.725 49.272 39.877 ;
     RECT  104.16 35.893 106.68 39.923 ;
     RECT  94.08 39.349 99.768 40.405 ;
     RECT  100.8 35.845 103.152 40.405 ;
     RECT  34.224 39.877 49.272 41.029 ;
     RECT  80.16 36.373 84.696 41.029 ;
     RECT  85.968 37.573 92.352 41.029 ;
     RECT  94.08 40.405 103.152 41.029 ;
     RECT  104.256 39.923 106.68 41.029 ;
     RECT  34.224 41.029 50.088 41.125 ;
     RECT  16.44 39.589 19.848 41.221 ;
     RECT  20.88 39.493 33.048 41.221 ;
     RECT  34.224 41.125 50.184 41.221 ;
     RECT  80.16 41.029 92.352 41.365 ;
     RECT  93.408 41.029 106.68 41.365 ;
     RECT  112.32 21.157 112.344 41.749 ;
     RECT  113.64 0.787 113.952 41.749 ;
     RECT  0.24 0.787 0.552 42.413 ;
     RECT  5.64 0.787 5.952 42.413 ;
     RECT  11.04 0.787 11.352 42.413 ;
     RECT  54.24 0.787 54.552 42.413 ;
     RECT  59.64 0.787 59.952 42.413 ;
     RECT  65.04 0.787 65.352 42.413 ;
     RECT  70.44 0.787 70.752 42.413 ;
     RECT  75.84 0.787 76.152 42.413 ;
     RECT  108.24 0.787 108.552 42.413 ;
     RECT  112.32 41.749 113.952 42.413 ;
     RECT  119.04 0.787 119.352 42.413 ;
     RECT  0.24 42.413 0.36 42.683 ;
     RECT  5.64 42.413 5.76 42.683 ;
     RECT  11.04 42.413 11.16 42.683 ;
     RECT  16.44 41.221 50.184 42.683 ;
     RECT  54.24 42.413 54.36 42.683 ;
     RECT  59.64 42.413 59.76 42.683 ;
     RECT  65.04 42.413 65.16 42.683 ;
     RECT  70.44 42.413 70.56 42.683 ;
     RECT  75.84 42.413 75.96 42.683 ;
     RECT  108.24 42.413 108.36 42.683 ;
     RECT  112.32 42.413 113.76 42.683 ;
     RECT  119.04 42.413 119.16 42.683 ;
     RECT  17.328 42.683 50.184 43.024 ;
     RECT  80.16 41.365 106.776 43.024 ;
     RECT  112.32 42.683 113.304 43.024 ;
     RECT  23.04 43.024 23.736 43.091 ;
     RECT  31.2 43.024 31.224 43.091 ;
     RECT  32.352 43.024 32.376 43.091 ;
     RECT  36.672 43.024 37.56 43.091 ;
     RECT  46.08 43.024 48.024 43.091 ;
     RECT  85.968 43.024 85.992 43.091 ;
     RECT  37.536 43.091 37.56 43.139 ;
    LAYER M6 ;
     RECT  0 11.796 32.533 12.66 ;
     RECT  32.533 10.816 33.059 12.66 ;
     RECT  86.533 20.352 86.699 20.384 ;
     RECT  86.645 42.816 86.723 42.848 ;
     RECT  0 0.996 97.909 1.86 ;
     RECT  97.909 0.256 97.963 1.86 ;
     RECT  97.963 0.384 98.051 1.86 ;
     RECT  98.051 0.996 121.068 1.86 ;
     RECT  0 6.396 121.068 7.26 ;
     RECT  33.059 11.796 121.068 12.66 ;
     RECT  0 17.196 121.068 18.06 ;
     RECT  0 22.596 121.068 23.46 ;
     RECT  0 27.996 121.068 28.86 ;
     RECT  0 33.396 121.068 34.26 ;
     RECT  0 38.796 121.068 39.66 ;
    LAYER M7 ;
     RECT  97.92 0.245 97.952 0.427 ;
     RECT  87.256 0.531 87.544 20.341 ;
     RECT  0.856 0.531 1.144 42.669 ;
     RECT  6.256 0.531 6.544 42.669 ;
     RECT  11.656 0.531 11.944 42.669 ;
     RECT  17.056 0.531 17.344 42.669 ;
     RECT  22.456 0.531 22.744 42.669 ;
     RECT  27.856 0.531 28.144 42.669 ;
     RECT  33.256 0.531 33.544 42.669 ;
     RECT  38.656 0.531 38.944 42.669 ;
     RECT  44.056 0.531 44.344 42.669 ;
     RECT  49.456 0.531 49.744 42.669 ;
     RECT  54.856 0.531 55.144 42.669 ;
     RECT  60.256 0.531 60.544 42.669 ;
     RECT  65.656 0.531 65.944 42.669 ;
     RECT  71.056 0.531 71.344 42.669 ;
     RECT  76.456 0.531 76.744 42.669 ;
     RECT  81.856 0.531 82.144 42.669 ;
     RECT  86.656 20.341 87.544 42.669 ;
     RECT  92.656 0.531 92.944 42.669 ;
     RECT  98.056 0.531 98.344 42.669 ;
     RECT  103.456 0.531 103.744 42.669 ;
     RECT  108.856 0.531 109.144 42.669 ;
     RECT  114.256 0.531 114.544 42.669 ;
     RECT  119.656 0.531 119.944 42.669 ;
     RECT  86.656 42.669 86.688 42.859 ;
  END
END dsfd_svc_pc
END LIBRARY
